VERSION 5.7 ;
  NOWIREEXTENSIONATPIN ON ;
  DIVIDERCHAR "/" ;
  BUSBITCHARS "[]" ;
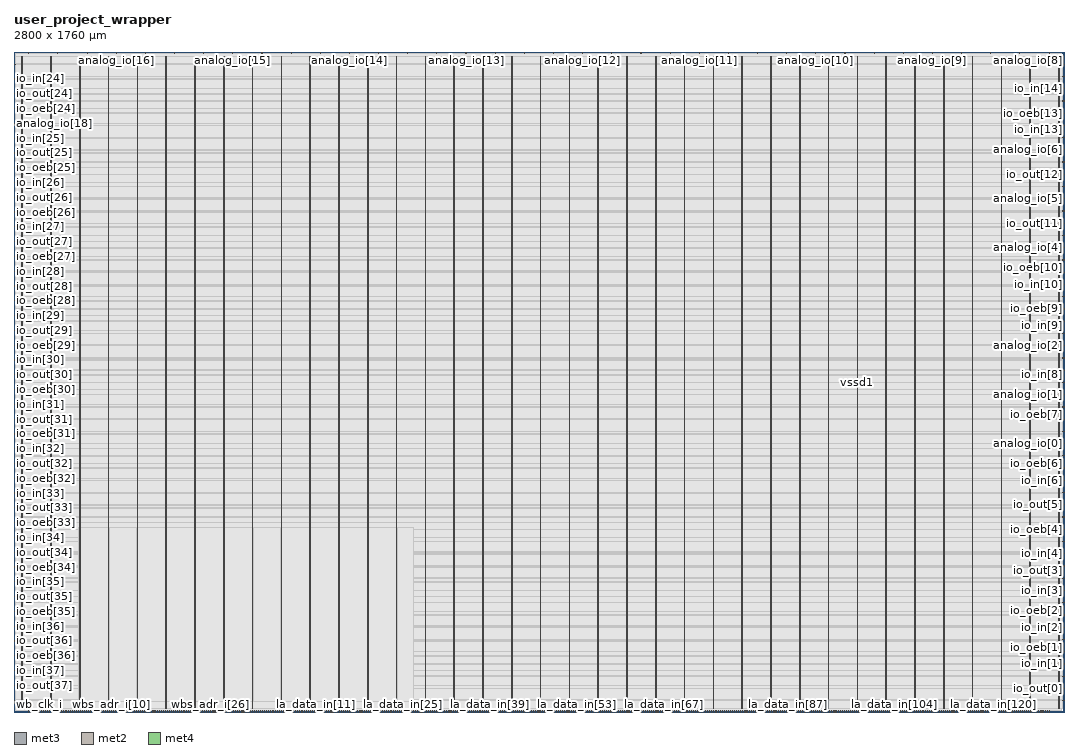
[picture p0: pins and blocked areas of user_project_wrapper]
MACRO user_project_wrapper
  CLASS BLOCK ;
  FOREIGN user_project_wrapper ;
  ORIGIN 0.000 0.000 ;
  SIZE 2800.000 BY 1760.000 ;
  PIN analog_io[0]
    DIRECTION INOUT ;
    USE SIGNAL ;
    PORT
      LAYER met3 ;
        RECT 2796.000 715.400 2800.000 716.000 ;
    END
  END analog_io[0]
  PIN analog_io[10]
    DIRECTION INOUT ;
    USE SIGNAL ;
    PORT
      LAYER met2 ;
        RECT 2138.170 1756.000 2138.450 1760.000 ;
    END
  END analog_io[10]
  PIN analog_io[11]
    DIRECTION INOUT ;
    USE SIGNAL ;
    PORT
      LAYER met2 ;
        RECT 1827.210 1756.000 1827.490 1760.000 ;
    END
  END analog_io[11]
  PIN analog_io[12]
    DIRECTION INOUT ;
    USE SIGNAL ;
    PORT
      LAYER met2 ;
        RECT 1516.250 1756.000 1516.530 1760.000 ;
    END
  END analog_io[12]
  PIN analog_io[13]
    DIRECTION INOUT ;
    USE SIGNAL ;
    PORT
      LAYER met2 ;
        RECT 1205.290 1756.000 1205.570 1760.000 ;
    END
  END analog_io[13]
  PIN analog_io[14]
    DIRECTION INOUT ;
    USE SIGNAL ;
    PORT
      LAYER met2 ;
        RECT 894.330 1756.000 894.610 1760.000 ;
    END
  END analog_io[14]
  PIN analog_io[15]
    DIRECTION INOUT ;
    USE SIGNAL ;
    PORT
      LAYER met2 ;
        RECT 583.370 1756.000 583.650 1760.000 ;
    END
  END analog_io[15]
  PIN analog_io[16]
    DIRECTION INOUT ;
    USE SIGNAL ;
    PORT
      LAYER met2 ;
        RECT 272.410 1756.000 272.690 1760.000 ;
    END
  END analog_io[16]
  PIN analog_io[17]
    DIRECTION INOUT ;
    USE SIGNAL ;
    PORT
      LAYER met3 ;
        RECT 0.000 1727.240 4.000 1727.840 ;
    END
  END analog_io[17]
  PIN analog_io[18]
    DIRECTION INOUT ;
    USE SIGNAL ;
    PORT
      LAYER met3 ;
        RECT 0.000 1569.480 4.000 1570.080 ;
    END
  END analog_io[18]
  PIN analog_io[1]
    DIRECTION INOUT ;
    USE SIGNAL ;
    PORT
      LAYER met3 ;
        RECT 2796.000 845.960 2800.000 846.560 ;
    END
  END analog_io[1]
  PIN analog_io[2]
    DIRECTION INOUT ;
    USE SIGNAL ;
    PORT
      LAYER met3 ;
        RECT 2796.000 976.520 2800.000 977.120 ;
    END
  END analog_io[2]
  PIN analog_io[3]
    DIRECTION INOUT ;
    USE SIGNAL ;
    PORT
      LAYER met3 ;
        RECT 2796.000 1107.080 2800.000 1107.680 ;
    END
  END analog_io[3]
  PIN analog_io[4]
    DIRECTION INOUT ;
    USE SIGNAL ;
    PORT
      LAYER met3 ;
        RECT 2796.000 1237.640 2800.000 1238.240 ;
    END
  END analog_io[4]
  PIN analog_io[5]
    DIRECTION INOUT ;
    USE SIGNAL ;
    PORT
      LAYER met3 ;
        RECT 2796.000 1368.200 2800.000 1368.800 ;
    END
  END analog_io[5]
  PIN analog_io[6]
    DIRECTION INOUT ;
    USE SIGNAL ;
    PORT
      LAYER met3 ;
        RECT 2796.000 1498.760 2800.000 1499.360 ;
    END
  END analog_io[6]
  PIN analog_io[7]
    DIRECTION INOUT ;
    USE SIGNAL ;
    PORT
      LAYER met3 ;
        RECT 2796.000 1629.320 2800.000 1629.920 ;
    END
  END analog_io[7]
  PIN analog_io[8]
    DIRECTION INOUT ;
    USE SIGNAL ;
    PORT
      LAYER met2 ;
        RECT 2760.090 1756.000 2760.370 1760.000 ;
    END
  END analog_io[8]
  PIN analog_io[9]
    DIRECTION INOUT ;
    USE SIGNAL ;
    PORT
      LAYER met2 ;
        RECT 2449.130 1756.000 2449.410 1760.000 ;
    END
  END analog_io[9]
  PIN io_in[0]
    DIRECTION INPUT ;
    USE SIGNAL ;
    PORT
      LAYER met3 ;
        RECT 2796.000 29.960 2800.000 30.560 ;
    END
  END io_in[0]
  PIN io_in[10]
    DIRECTION INPUT ;
    USE SIGNAL ;
    PORT
      LAYER met3 ;
        RECT 2796.000 1139.720 2800.000 1140.320 ;
    END
  END io_in[10]
  PIN io_in[11]
    DIRECTION INPUT ;
    USE SIGNAL ;
    PORT
      LAYER met3 ;
        RECT 2796.000 1270.280 2800.000 1270.880 ;
    END
  END io_in[11]
  PIN io_in[12]
    DIRECTION INPUT ;
    USE SIGNAL ;
    PORT
      LAYER met3 ;
        RECT 2796.000 1400.840 2800.000 1401.440 ;
    END
  END io_in[12]
  PIN io_in[13]
    DIRECTION INPUT ;
    USE SIGNAL ;
    PORT
      LAYER met3 ;
        RECT 2796.000 1531.400 2800.000 1532.000 ;
    END
  END io_in[13]
  PIN io_in[14]
    DIRECTION INPUT ;
    USE SIGNAL ;
    PORT
      LAYER met3 ;
        RECT 2796.000 1661.960 2800.000 1662.560 ;
    END
  END io_in[14]
  PIN io_in[15]
    DIRECTION INPUT ;
    USE SIGNAL ;
    PORT
      LAYER met2 ;
        RECT 2682.350 1756.000 2682.630 1760.000 ;
    END
  END io_in[15]
  PIN io_in[16]
    DIRECTION INPUT ;
    USE SIGNAL ;
    PORT
      LAYER met2 ;
        RECT 2371.390 1756.000 2371.670 1760.000 ;
    END
  END io_in[16]
  PIN io_in[17]
    DIRECTION INPUT ;
    USE SIGNAL ;
    PORT
      LAYER met2 ;
        RECT 2060.430 1756.000 2060.710 1760.000 ;
    END
  END io_in[17]
  PIN io_in[18]
    DIRECTION INPUT ;
    USE SIGNAL ;
    PORT
      LAYER met2 ;
        RECT 1749.470 1756.000 1749.750 1760.000 ;
    END
  END io_in[18]
  PIN io_in[19]
    DIRECTION INPUT ;
    USE SIGNAL ;
    PORT
      LAYER met2 ;
        RECT 1438.510 1756.000 1438.790 1760.000 ;
    END
  END io_in[19]
  PIN io_in[1]
    DIRECTION INPUT ;
    USE SIGNAL ;
    PORT
      LAYER met3 ;
        RECT 2796.000 127.880 2800.000 128.480 ;
    END
  END io_in[1]
  PIN io_in[20]
    DIRECTION INPUT ;
    USE SIGNAL ;
    PORT
      LAYER met2 ;
        RECT 1127.550 1756.000 1127.830 1760.000 ;
    END
  END io_in[20]
  PIN io_in[21]
    DIRECTION INPUT ;
    USE SIGNAL ;
    PORT
      LAYER met2 ;
        RECT 816.590 1756.000 816.870 1760.000 ;
    END
  END io_in[21]
  PIN io_in[22]
    DIRECTION INPUT ;
    USE SIGNAL ;
    PORT
      LAYER met2 ;
        RECT 505.630 1756.000 505.910 1760.000 ;
    END
  END io_in[22]
  PIN io_in[23]
    DIRECTION INPUT ;
    USE SIGNAL ;
    PORT
      LAYER met2 ;
        RECT 194.670 1756.000 194.950 1760.000 ;
    END
  END io_in[23]
  PIN io_in[24]
    DIRECTION INPUT ;
    USE SIGNAL ;
    PORT
      LAYER met3 ;
        RECT 0.000 1687.800 4.000 1688.400 ;
    END
  END io_in[24]
  PIN io_in[25]
    DIRECTION INPUT ;
    USE SIGNAL ;
    PORT
      LAYER met3 ;
        RECT 0.000 1530.040 4.000 1530.640 ;
    END
  END io_in[25]
  PIN io_in[26]
    DIRECTION INPUT ;
    USE SIGNAL ;
    PORT
      LAYER met3 ;
        RECT 0.000 1411.720 4.000 1412.320 ;
    END
  END io_in[26]
  PIN io_in[27]
    DIRECTION INPUT ;
    USE SIGNAL ;
    PORT
      LAYER met3 ;
        RECT 0.000 1293.400 4.000 1294.000 ;
    END
  END io_in[27]
  PIN io_in[28]
    DIRECTION INPUT ;
    USE SIGNAL ;
    PORT
      LAYER met3 ;
        RECT 0.000 1175.080 4.000 1175.680 ;
    END
  END io_in[28]
  PIN io_in[29]
    DIRECTION INPUT ;
    USE SIGNAL ;
    PORT
      LAYER met3 ;
        RECT 0.000 1056.760 4.000 1057.360 ;
    END
  END io_in[29]
  PIN io_in[2]
    DIRECTION INPUT ;
    USE SIGNAL ;
    PORT
      LAYER met3 ;
        RECT 2796.000 225.800 2800.000 226.400 ;
    END
  END io_in[2]
  PIN io_in[30]
    DIRECTION INPUT ;
    USE SIGNAL ;
    PORT
      LAYER met3 ;
        RECT 0.000 938.440 4.000 939.040 ;
    END
  END io_in[30]
  PIN io_in[31]
    DIRECTION INPUT ;
    USE SIGNAL ;
    PORT
      LAYER met3 ;
        RECT 0.000 820.120 4.000 820.720 ;
    END
  END io_in[31]
  PIN io_in[32]
    DIRECTION INPUT ;
    USE SIGNAL ;
    PORT
      LAYER met3 ;
        RECT 0.000 701.800 4.000 702.400 ;
    END
  END io_in[32]
  PIN io_in[33]
    DIRECTION INPUT ;
    USE SIGNAL ;
    PORT
      LAYER met3 ;
        RECT 0.000 583.480 4.000 584.080 ;
    END
  END io_in[33]
  PIN io_in[34]
    DIRECTION INPUT ;
    USE SIGNAL ;
    PORT
      LAYER met3 ;
        RECT 0.000 465.160 4.000 465.760 ;
    END
  END io_in[34]
  PIN io_in[35]
    DIRECTION INPUT ;
    USE SIGNAL ;
    PORT
      LAYER met3 ;
        RECT 0.000 346.840 4.000 347.440 ;
    END
  END io_in[35]
  PIN io_in[36]
    DIRECTION INPUT ;
    USE SIGNAL ;
    PORT
      LAYER met3 ;
        RECT 0.000 228.520 4.000 229.120 ;
    END
  END io_in[36]
  PIN io_in[37]
    DIRECTION INPUT ;
    USE SIGNAL ;
    PORT
      LAYER met3 ;
        RECT 0.000 110.200 4.000 110.800 ;
    END
  END io_in[37]
  PIN io_in[3]
    DIRECTION INPUT ;
    USE SIGNAL ;
    PORT
      LAYER met3 ;
        RECT 2796.000 323.720 2800.000 324.320 ;
    END
  END io_in[3]
  PIN io_in[4]
    DIRECTION INPUT ;
    USE SIGNAL ;
    PORT
      LAYER met3 ;
        RECT 2796.000 421.640 2800.000 422.240 ;
    END
  END io_in[4]
  PIN io_in[5]
    DIRECTION INPUT ;
    USE SIGNAL ;
    PORT
      LAYER met3 ;
        RECT 2796.000 519.560 2800.000 520.160 ;
    END
  END io_in[5]
  PIN io_in[6]
    DIRECTION INPUT ;
    USE SIGNAL ;
    PORT
      LAYER met3 ;
        RECT 2796.000 617.480 2800.000 618.080 ;
    END
  END io_in[6]
  PIN io_in[7]
    DIRECTION INPUT ;
    USE SIGNAL ;
    PORT
      LAYER met3 ;
        RECT 2796.000 748.040 2800.000 748.640 ;
    END
  END io_in[7]
  PIN io_in[8]
    DIRECTION INPUT ;
    USE SIGNAL ;
    ANTENNAGATEAREA 0.990000 ;
    PORT
      LAYER met3 ;
        RECT 2796.000 878.600 2800.000 879.200 ;
    END
  END io_in[8]
  PIN io_in[9]
    DIRECTION INPUT ;
    USE SIGNAL ;
    PORT
      LAYER met3 ;
        RECT 2796.000 1009.160 2800.000 1009.760 ;
    END
  END io_in[9]
  PIN io_oeb[0]
    DIRECTION OUTPUT TRISTATE ;
    USE SIGNAL ;
    PORT
      LAYER met3 ;
        RECT 2796.000 95.240 2800.000 95.840 ;
    END
  END io_oeb[0]
  PIN io_oeb[10]
    DIRECTION OUTPUT TRISTATE ;
    USE SIGNAL ;
    PORT
      LAYER met3 ;
        RECT 2796.000 1205.000 2800.000 1205.600 ;
    END
  END io_oeb[10]
  PIN io_oeb[11]
    DIRECTION OUTPUT TRISTATE ;
    USE SIGNAL ;
    PORT
      LAYER met3 ;
        RECT 2796.000 1335.560 2800.000 1336.160 ;
    END
  END io_oeb[11]
  PIN io_oeb[12]
    DIRECTION OUTPUT TRISTATE ;
    USE SIGNAL ;
    PORT
      LAYER met3 ;
        RECT 2796.000 1466.120 2800.000 1466.720 ;
    END
  END io_oeb[12]
  PIN io_oeb[13]
    DIRECTION OUTPUT TRISTATE ;
    USE SIGNAL ;
    PORT
      LAYER met3 ;
        RECT 2796.000 1596.680 2800.000 1597.280 ;
    END
  END io_oeb[13]
  PIN io_oeb[14]
    DIRECTION OUTPUT TRISTATE ;
    USE SIGNAL ;
    PORT
      LAYER met3 ;
        RECT 2796.000 1727.240 2800.000 1727.840 ;
    END
  END io_oeb[14]
  PIN io_oeb[15]
    DIRECTION OUTPUT TRISTATE ;
    USE SIGNAL ;
    PORT
      LAYER met2 ;
        RECT 2526.870 1756.000 2527.150 1760.000 ;
    END
  END io_oeb[15]
  PIN io_oeb[16]
    DIRECTION OUTPUT TRISTATE ;
    USE SIGNAL ;
    PORT
      LAYER met2 ;
        RECT 2215.910 1756.000 2216.190 1760.000 ;
    END
  END io_oeb[16]
  PIN io_oeb[17]
    DIRECTION OUTPUT TRISTATE ;
    USE SIGNAL ;
    PORT
      LAYER met2 ;
        RECT 1904.950 1756.000 1905.230 1760.000 ;
    END
  END io_oeb[17]
  PIN io_oeb[18]
    DIRECTION OUTPUT TRISTATE ;
    USE SIGNAL ;
    PORT
      LAYER met2 ;
        RECT 1593.990 1756.000 1594.270 1760.000 ;
    END
  END io_oeb[18]
  PIN io_oeb[19]
    DIRECTION OUTPUT TRISTATE ;
    USE SIGNAL ;
    PORT
      LAYER met2 ;
        RECT 1283.030 1756.000 1283.310 1760.000 ;
    END
  END io_oeb[19]
  PIN io_oeb[1]
    DIRECTION OUTPUT TRISTATE ;
    USE SIGNAL ;
    PORT
      LAYER met3 ;
        RECT 2796.000 193.160 2800.000 193.760 ;
    END
  END io_oeb[1]
  PIN io_oeb[20]
    DIRECTION OUTPUT TRISTATE ;
    USE SIGNAL ;
    PORT
      LAYER met2 ;
        RECT 972.070 1756.000 972.350 1760.000 ;
    END
  END io_oeb[20]
  PIN io_oeb[21]
    DIRECTION OUTPUT TRISTATE ;
    USE SIGNAL ;
    PORT
      LAYER met2 ;
        RECT 661.110 1756.000 661.390 1760.000 ;
    END
  END io_oeb[21]
  PIN io_oeb[22]
    DIRECTION OUTPUT TRISTATE ;
    USE SIGNAL ;
    PORT
      LAYER met2 ;
        RECT 350.150 1756.000 350.430 1760.000 ;
    END
  END io_oeb[22]
  PIN io_oeb[23]
    DIRECTION OUTPUT TRISTATE ;
    USE SIGNAL ;
    PORT
      LAYER met2 ;
        RECT 39.190 1756.000 39.470 1760.000 ;
    END
  END io_oeb[23]
  PIN io_oeb[24]
    DIRECTION OUTPUT TRISTATE ;
    USE SIGNAL ;
    PORT
      LAYER met3 ;
        RECT 0.000 1608.920 4.000 1609.520 ;
    END
  END io_oeb[24]
  PIN io_oeb[25]
    DIRECTION OUTPUT TRISTATE ;
    USE SIGNAL ;
    PORT
      LAYER met3 ;
        RECT 0.000 1451.160 4.000 1451.760 ;
    END
  END io_oeb[25]
  PIN io_oeb[26]
    DIRECTION OUTPUT TRISTATE ;
    USE SIGNAL ;
    PORT
      LAYER met3 ;
        RECT 0.000 1332.840 4.000 1333.440 ;
    END
  END io_oeb[26]
  PIN io_oeb[27]
    DIRECTION OUTPUT TRISTATE ;
    USE SIGNAL ;
    PORT
      LAYER met3 ;
        RECT 0.000 1214.520 4.000 1215.120 ;
    END
  END io_oeb[27]
  PIN io_oeb[28]
    DIRECTION OUTPUT TRISTATE ;
    USE SIGNAL ;
    PORT
      LAYER met3 ;
        RECT 0.000 1096.200 4.000 1096.800 ;
    END
  END io_oeb[28]
  PIN io_oeb[29]
    DIRECTION OUTPUT TRISTATE ;
    USE SIGNAL ;
    PORT
      LAYER met3 ;
        RECT 0.000 977.880 4.000 978.480 ;
    END
  END io_oeb[29]
  PIN io_oeb[2]
    DIRECTION OUTPUT TRISTATE ;
    USE SIGNAL ;
    PORT
      LAYER met3 ;
        RECT 2796.000 291.080 2800.000 291.680 ;
    END
  END io_oeb[2]
  PIN io_oeb[30]
    DIRECTION OUTPUT TRISTATE ;
    USE SIGNAL ;
    PORT
      LAYER met3 ;
        RECT 0.000 859.560 4.000 860.160 ;
    END
  END io_oeb[30]
  PIN io_oeb[31]
    DIRECTION OUTPUT TRISTATE ;
    USE SIGNAL ;
    PORT
      LAYER met3 ;
        RECT 0.000 741.240 4.000 741.840 ;
    END
  END io_oeb[31]
  PIN io_oeb[32]
    DIRECTION OUTPUT TRISTATE ;
    USE SIGNAL ;
    PORT
      LAYER met3 ;
        RECT 0.000 622.920 4.000 623.520 ;
    END
  END io_oeb[32]
  PIN io_oeb[33]
    DIRECTION OUTPUT TRISTATE ;
    USE SIGNAL ;
    PORT
      LAYER met3 ;
        RECT 0.000 504.600 4.000 505.200 ;
    END
  END io_oeb[33]
  PIN io_oeb[34]
    DIRECTION OUTPUT TRISTATE ;
    USE SIGNAL ;
    PORT
      LAYER met3 ;
        RECT 0.000 386.280 4.000 386.880 ;
    END
  END io_oeb[34]
  PIN io_oeb[35]
    DIRECTION OUTPUT TRISTATE ;
    USE SIGNAL ;
    PORT
      LAYER met3 ;
        RECT 0.000 267.960 4.000 268.560 ;
    END
  END io_oeb[35]
  PIN io_oeb[36]
    DIRECTION OUTPUT TRISTATE ;
    USE SIGNAL ;
    PORT
      LAYER met3 ;
        RECT 0.000 149.640 4.000 150.240 ;
    END
  END io_oeb[36]
  PIN io_oeb[37]
    DIRECTION OUTPUT TRISTATE ;
    USE SIGNAL ;
    PORT
      LAYER met3 ;
        RECT 0.000 31.320 4.000 31.920 ;
    END
  END io_oeb[37]
  PIN io_oeb[3]
    DIRECTION OUTPUT TRISTATE ;
    USE SIGNAL ;
    PORT
      LAYER met3 ;
        RECT 2796.000 389.000 2800.000 389.600 ;
    END
  END io_oeb[3]
  PIN io_oeb[4]
    DIRECTION OUTPUT TRISTATE ;
    USE SIGNAL ;
    PORT
      LAYER met3 ;
        RECT 2796.000 486.920 2800.000 487.520 ;
    END
  END io_oeb[4]
  PIN io_oeb[5]
    DIRECTION OUTPUT TRISTATE ;
    USE SIGNAL ;
    PORT
      LAYER met3 ;
        RECT 2796.000 584.840 2800.000 585.440 ;
    END
  END io_oeb[5]
  PIN io_oeb[6]
    DIRECTION OUTPUT TRISTATE ;
    USE SIGNAL ;
    PORT
      LAYER met3 ;
        RECT 2796.000 682.760 2800.000 683.360 ;
    END
  END io_oeb[6]
  PIN io_oeb[7]
    DIRECTION OUTPUT TRISTATE ;
    USE SIGNAL ;
    PORT
      LAYER met3 ;
        RECT 2796.000 813.320 2800.000 813.920 ;
    END
  END io_oeb[7]
  PIN io_oeb[8]
    DIRECTION OUTPUT TRISTATE ;
    USE SIGNAL ;
    PORT
      LAYER met3 ;
        RECT 2796.000 943.880 2800.000 944.480 ;
    END
  END io_oeb[8]
  PIN io_oeb[9]
    DIRECTION OUTPUT TRISTATE ;
    USE SIGNAL ;
    PORT
      LAYER met3 ;
        RECT 2796.000 1074.440 2800.000 1075.040 ;
    END
  END io_oeb[9]
  PIN io_out[0]
    DIRECTION OUTPUT TRISTATE ;
    USE SIGNAL ;
    PORT
      LAYER met3 ;
        RECT 2796.000 62.600 2800.000 63.200 ;
    END
  END io_out[0]
  PIN io_out[10]
    DIRECTION OUTPUT TRISTATE ;
    USE SIGNAL ;
    PORT
      LAYER met3 ;
        RECT 2796.000 1172.360 2800.000 1172.960 ;
    END
  END io_out[10]
  PIN io_out[11]
    DIRECTION OUTPUT TRISTATE ;
    USE SIGNAL ;
    PORT
      LAYER met3 ;
        RECT 2796.000 1302.920 2800.000 1303.520 ;
    END
  END io_out[11]
  PIN io_out[12]
    DIRECTION OUTPUT TRISTATE ;
    USE SIGNAL ;
    PORT
      LAYER met3 ;
        RECT 2796.000 1433.480 2800.000 1434.080 ;
    END
  END io_out[12]
  PIN io_out[13]
    DIRECTION OUTPUT TRISTATE ;
    USE SIGNAL ;
    PORT
      LAYER met3 ;
        RECT 2796.000 1564.040 2800.000 1564.640 ;
    END
  END io_out[13]
  PIN io_out[14]
    DIRECTION OUTPUT TRISTATE ;
    USE SIGNAL ;
    PORT
      LAYER met3 ;
        RECT 2796.000 1694.600 2800.000 1695.200 ;
    END
  END io_out[14]
  PIN io_out[15]
    DIRECTION OUTPUT TRISTATE ;
    USE SIGNAL ;
    PORT
      LAYER met2 ;
        RECT 2604.610 1756.000 2604.890 1760.000 ;
    END
  END io_out[15]
  PIN io_out[16]
    DIRECTION OUTPUT TRISTATE ;
    USE SIGNAL ;
    PORT
      LAYER met2 ;
        RECT 2293.650 1756.000 2293.930 1760.000 ;
    END
  END io_out[16]
  PIN io_out[17]
    DIRECTION OUTPUT TRISTATE ;
    USE SIGNAL ;
    PORT
      LAYER met2 ;
        RECT 1982.690 1756.000 1982.970 1760.000 ;
    END
  END io_out[17]
  PIN io_out[18]
    DIRECTION OUTPUT TRISTATE ;
    USE SIGNAL ;
    PORT
      LAYER met2 ;
        RECT 1671.730 1756.000 1672.010 1760.000 ;
    END
  END io_out[18]
  PIN io_out[19]
    DIRECTION OUTPUT TRISTATE ;
    USE SIGNAL ;
    PORT
      LAYER met2 ;
        RECT 1360.770 1756.000 1361.050 1760.000 ;
    END
  END io_out[19]
  PIN io_out[1]
    DIRECTION OUTPUT TRISTATE ;
    USE SIGNAL ;
    PORT
      LAYER met3 ;
        RECT 2796.000 160.520 2800.000 161.120 ;
    END
  END io_out[1]
  PIN io_out[20]
    DIRECTION OUTPUT TRISTATE ;
    USE SIGNAL ;
    PORT
      LAYER met2 ;
        RECT 1049.810 1756.000 1050.090 1760.000 ;
    END
  END io_out[20]
  PIN io_out[21]
    DIRECTION OUTPUT TRISTATE ;
    USE SIGNAL ;
    PORT
      LAYER met2 ;
        RECT 738.850 1756.000 739.130 1760.000 ;
    END
  END io_out[21]
  PIN io_out[22]
    DIRECTION OUTPUT TRISTATE ;
    USE SIGNAL ;
    PORT
      LAYER met2 ;
        RECT 427.890 1756.000 428.170 1760.000 ;
    END
  END io_out[22]
  PIN io_out[23]
    DIRECTION OUTPUT TRISTATE ;
    USE SIGNAL ;
    PORT
      LAYER met2 ;
        RECT 116.930 1756.000 117.210 1760.000 ;
    END
  END io_out[23]
  PIN io_out[24]
    DIRECTION OUTPUT TRISTATE ;
    USE SIGNAL ;
    PORT
      LAYER met3 ;
        RECT 0.000 1648.360 4.000 1648.960 ;
    END
  END io_out[24]
  PIN io_out[25]
    DIRECTION OUTPUT TRISTATE ;
    USE SIGNAL ;
    PORT
      LAYER met3 ;
        RECT 0.000 1490.600 4.000 1491.200 ;
    END
  END io_out[25]
  PIN io_out[26]
    DIRECTION OUTPUT TRISTATE ;
    USE SIGNAL ;
    PORT
      LAYER met3 ;
        RECT 0.000 1372.280 4.000 1372.880 ;
    END
  END io_out[26]
  PIN io_out[27]
    DIRECTION OUTPUT TRISTATE ;
    USE SIGNAL ;
    PORT
      LAYER met3 ;
        RECT 0.000 1253.960 4.000 1254.560 ;
    END
  END io_out[27]
  PIN io_out[28]
    DIRECTION OUTPUT TRISTATE ;
    USE SIGNAL ;
    PORT
      LAYER met3 ;
        RECT 0.000 1135.640 4.000 1136.240 ;
    END
  END io_out[28]
  PIN io_out[29]
    DIRECTION OUTPUT TRISTATE ;
    USE SIGNAL ;
    PORT
      LAYER met3 ;
        RECT 0.000 1017.320 4.000 1017.920 ;
    END
  END io_out[29]
  PIN io_out[2]
    DIRECTION OUTPUT TRISTATE ;
    USE SIGNAL ;
    PORT
      LAYER met3 ;
        RECT 2796.000 258.440 2800.000 259.040 ;
    END
  END io_out[2]
  PIN io_out[30]
    DIRECTION OUTPUT TRISTATE ;
    USE SIGNAL ;
    PORT
      LAYER met3 ;
        RECT 0.000 899.000 4.000 899.600 ;
    END
  END io_out[30]
  PIN io_out[31]
    DIRECTION OUTPUT TRISTATE ;
    USE SIGNAL ;
    PORT
      LAYER met3 ;
        RECT 0.000 780.680 4.000 781.280 ;
    END
  END io_out[31]
  PIN io_out[32]
    DIRECTION OUTPUT TRISTATE ;
    USE SIGNAL ;
    PORT
      LAYER met3 ;
        RECT 0.000 662.360 4.000 662.960 ;
    END
  END io_out[32]
  PIN io_out[33]
    DIRECTION OUTPUT TRISTATE ;
    USE SIGNAL ;
    PORT
      LAYER met3 ;
        RECT 0.000 544.040 4.000 544.640 ;
    END
  END io_out[33]
  PIN io_out[34]
    DIRECTION OUTPUT TRISTATE ;
    USE SIGNAL ;
    PORT
      LAYER met3 ;
        RECT 0.000 425.720 4.000 426.320 ;
    END
  END io_out[34]
  PIN io_out[35]
    DIRECTION OUTPUT TRISTATE ;
    USE SIGNAL ;
    PORT
      LAYER met3 ;
        RECT 0.000 307.400 4.000 308.000 ;
    END
  END io_out[35]
  PIN io_out[36]
    DIRECTION OUTPUT TRISTATE ;
    USE SIGNAL ;
    PORT
      LAYER met3 ;
        RECT 0.000 189.080 4.000 189.680 ;
    END
  END io_out[36]
  PIN io_out[37]
    DIRECTION OUTPUT TRISTATE ;
    USE SIGNAL ;
    PORT
      LAYER met3 ;
        RECT 0.000 70.760 4.000 71.360 ;
    END
  END io_out[37]
  PIN io_out[3]
    DIRECTION OUTPUT TRISTATE ;
    USE SIGNAL ;
    PORT
      LAYER met3 ;
        RECT 2796.000 356.360 2800.000 356.960 ;
    END
  END io_out[3]
  PIN io_out[4]
    DIRECTION OUTPUT TRISTATE ;
    USE SIGNAL ;
    PORT
      LAYER met3 ;
        RECT 2796.000 454.280 2800.000 454.880 ;
    END
  END io_out[4]
  PIN io_out[5]
    DIRECTION OUTPUT TRISTATE ;
    USE SIGNAL ;
    PORT
      LAYER met3 ;
        RECT 2796.000 552.200 2800.000 552.800 ;
    END
  END io_out[5]
  PIN io_out[6]
    DIRECTION OUTPUT TRISTATE ;
    USE SIGNAL ;
    PORT
      LAYER met3 ;
        RECT 2796.000 650.120 2800.000 650.720 ;
    END
  END io_out[6]
  PIN io_out[7]
    DIRECTION OUTPUT TRISTATE ;
    USE SIGNAL ;
    PORT
      LAYER met3 ;
        RECT 2796.000 780.680 2800.000 781.280 ;
    END
  END io_out[7]
  PIN io_out[8]
    DIRECTION OUTPUT TRISTATE ;
    USE SIGNAL ;
    PORT
      LAYER met3 ;
        RECT 2796.000 911.240 2800.000 911.840 ;
    END
  END io_out[8]
  PIN io_out[9]
    DIRECTION OUTPUT TRISTATE ;
    USE SIGNAL ;
    ANTENNADIFFAREA 2.673000 ;
    PORT
      LAYER met3 ;
        RECT 2796.000 1041.800 2800.000 1042.400 ;
    END
  END io_out[9]
  PIN la_data_in[0]
    DIRECTION INPUT ;
    USE SIGNAL ;
    PORT
      LAYER met2 ;
        RECT 624.310 0.000 624.590 4.000 ;
    END
  END la_data_in[0]
  PIN la_data_in[100]
    DIRECTION INPUT ;
    USE SIGNAL ;
    PORT
      LAYER met2 ;
        RECT 2280.310 0.000 2280.590 4.000 ;
    END
  END la_data_in[100]
  PIN la_data_in[101]
    DIRECTION INPUT ;
    USE SIGNAL ;
    PORT
      LAYER met2 ;
        RECT 2296.870 0.000 2297.150 4.000 ;
    END
  END la_data_in[101]
  PIN la_data_in[102]
    DIRECTION INPUT ;
    USE SIGNAL ;
    PORT
      LAYER met2 ;
        RECT 2313.430 0.000 2313.710 4.000 ;
    END
  END la_data_in[102]
  PIN la_data_in[103]
    DIRECTION INPUT ;
    USE SIGNAL ;
    PORT
      LAYER met2 ;
        RECT 2329.990 0.000 2330.270 4.000 ;
    END
  END la_data_in[103]
  PIN la_data_in[104]
    DIRECTION INPUT ;
    USE SIGNAL ;
    PORT
      LAYER met2 ;
        RECT 2346.550 0.000 2346.830 4.000 ;
    END
  END la_data_in[104]
  PIN la_data_in[105]
    DIRECTION INPUT ;
    USE SIGNAL ;
    PORT
      LAYER met2 ;
        RECT 2363.110 0.000 2363.390 4.000 ;
    END
  END la_data_in[105]
  PIN la_data_in[106]
    DIRECTION INPUT ;
    USE SIGNAL ;
    PORT
      LAYER met2 ;
        RECT 2379.670 0.000 2379.950 4.000 ;
    END
  END la_data_in[106]
  PIN la_data_in[107]
    DIRECTION INPUT ;
    USE SIGNAL ;
    PORT
      LAYER met2 ;
        RECT 2396.230 0.000 2396.510 4.000 ;
    END
  END la_data_in[107]
  PIN la_data_in[108]
    DIRECTION INPUT ;
    USE SIGNAL ;
    PORT
      LAYER met2 ;
        RECT 2412.790 0.000 2413.070 4.000 ;
    END
  END la_data_in[108]
  PIN la_data_in[109]
    DIRECTION INPUT ;
    USE SIGNAL ;
    PORT
      LAYER met2 ;
        RECT 2429.350 0.000 2429.630 4.000 ;
    END
  END la_data_in[109]
  PIN la_data_in[10]
    DIRECTION INPUT ;
    USE SIGNAL ;
    PORT
      LAYER met2 ;
        RECT 789.910 0.000 790.190 4.000 ;
    END
  END la_data_in[10]
  PIN la_data_in[110]
    DIRECTION INPUT ;
    USE SIGNAL ;
    PORT
      LAYER met2 ;
        RECT 2445.910 0.000 2446.190 4.000 ;
    END
  END la_data_in[110]
  PIN la_data_in[111]
    DIRECTION INPUT ;
    USE SIGNAL ;
    PORT
      LAYER met2 ;
        RECT 2462.470 0.000 2462.750 4.000 ;
    END
  END la_data_in[111]
  PIN la_data_in[112]
    DIRECTION INPUT ;
    USE SIGNAL ;
    PORT
      LAYER met2 ;
        RECT 2479.030 0.000 2479.310 4.000 ;
    END
  END la_data_in[112]
  PIN la_data_in[113]
    DIRECTION INPUT ;
    USE SIGNAL ;
    PORT
      LAYER met2 ;
        RECT 2495.590 0.000 2495.870 4.000 ;
    END
  END la_data_in[113]
  PIN la_data_in[114]
    DIRECTION INPUT ;
    USE SIGNAL ;
    PORT
      LAYER met2 ;
        RECT 2512.150 0.000 2512.430 4.000 ;
    END
  END la_data_in[114]
  PIN la_data_in[115]
    DIRECTION INPUT ;
    USE SIGNAL ;
    PORT
      LAYER met2 ;
        RECT 2528.710 0.000 2528.990 4.000 ;
    END
  END la_data_in[115]
  PIN la_data_in[116]
    DIRECTION INPUT ;
    USE SIGNAL ;
    PORT
      LAYER met2 ;
        RECT 2545.270 0.000 2545.550 4.000 ;
    END
  END la_data_in[116]
  PIN la_data_in[117]
    DIRECTION INPUT ;
    USE SIGNAL ;
    PORT
      LAYER met2 ;
        RECT 2561.830 0.000 2562.110 4.000 ;
    END
  END la_data_in[117]
  PIN la_data_in[118]
    DIRECTION INPUT ;
    USE SIGNAL ;
    PORT
      LAYER met2 ;
        RECT 2578.390 0.000 2578.670 4.000 ;
    END
  END la_data_in[118]
  PIN la_data_in[119]
    DIRECTION INPUT ;
    USE SIGNAL ;
    PORT
      LAYER met2 ;
        RECT 2594.950 0.000 2595.230 4.000 ;
    END
  END la_data_in[119]
  PIN la_data_in[11]
    DIRECTION INPUT ;
    USE SIGNAL ;
    PORT
      LAYER met2 ;
        RECT 806.470 0.000 806.750 4.000 ;
    END
  END la_data_in[11]
  PIN la_data_in[120]
    DIRECTION INPUT ;
    USE SIGNAL ;
    PORT
      LAYER met2 ;
        RECT 2611.510 0.000 2611.790 4.000 ;
    END
  END la_data_in[120]
  PIN la_data_in[121]
    DIRECTION INPUT ;
    USE SIGNAL ;
    PORT
      LAYER met2 ;
        RECT 2628.070 0.000 2628.350 4.000 ;
    END
  END la_data_in[121]
  PIN la_data_in[122]
    DIRECTION INPUT ;
    USE SIGNAL ;
    PORT
      LAYER met2 ;
        RECT 2644.630 0.000 2644.910 4.000 ;
    END
  END la_data_in[122]
  PIN la_data_in[123]
    DIRECTION INPUT ;
    USE SIGNAL ;
    PORT
      LAYER met2 ;
        RECT 2661.190 0.000 2661.470 4.000 ;
    END
  END la_data_in[123]
  PIN la_data_in[124]
    DIRECTION INPUT ;
    USE SIGNAL ;
    PORT
      LAYER met2 ;
        RECT 2677.750 0.000 2678.030 4.000 ;
    END
  END la_data_in[124]
  PIN la_data_in[125]
    DIRECTION INPUT ;
    USE SIGNAL ;
    PORT
      LAYER met2 ;
        RECT 2694.310 0.000 2694.590 4.000 ;
    END
  END la_data_in[125]
  PIN la_data_in[126]
    DIRECTION INPUT ;
    USE SIGNAL ;
    PORT
      LAYER met2 ;
        RECT 2710.870 0.000 2711.150 4.000 ;
    END
  END la_data_in[126]
  PIN la_data_in[127]
    DIRECTION INPUT ;
    USE SIGNAL ;
    PORT
      LAYER met2 ;
        RECT 2727.430 0.000 2727.710 4.000 ;
    END
  END la_data_in[127]
  PIN la_data_in[12]
    DIRECTION INPUT ;
    USE SIGNAL ;
    PORT
      LAYER met2 ;
        RECT 823.030 0.000 823.310 4.000 ;
    END
  END la_data_in[12]
  PIN la_data_in[13]
    DIRECTION INPUT ;
    USE SIGNAL ;
    PORT
      LAYER met2 ;
        RECT 839.590 0.000 839.870 4.000 ;
    END
  END la_data_in[13]
  PIN la_data_in[14]
    DIRECTION INPUT ;
    USE SIGNAL ;
    PORT
      LAYER met2 ;
        RECT 856.150 0.000 856.430 4.000 ;
    END
  END la_data_in[14]
  PIN la_data_in[15]
    DIRECTION INPUT ;
    USE SIGNAL ;
    PORT
      LAYER met2 ;
        RECT 872.710 0.000 872.990 4.000 ;
    END
  END la_data_in[15]
  PIN la_data_in[16]
    DIRECTION INPUT ;
    USE SIGNAL ;
    PORT
      LAYER met2 ;
        RECT 889.270 0.000 889.550 4.000 ;
    END
  END la_data_in[16]
  PIN la_data_in[17]
    DIRECTION INPUT ;
    USE SIGNAL ;
    PORT
      LAYER met2 ;
        RECT 905.830 0.000 906.110 4.000 ;
    END
  END la_data_in[17]
  PIN la_data_in[18]
    DIRECTION INPUT ;
    USE SIGNAL ;
    PORT
      LAYER met2 ;
        RECT 922.390 0.000 922.670 4.000 ;
    END
  END la_data_in[18]
  PIN la_data_in[19]
    DIRECTION INPUT ;
    USE SIGNAL ;
    PORT
      LAYER met2 ;
        RECT 938.950 0.000 939.230 4.000 ;
    END
  END la_data_in[19]
  PIN la_data_in[1]
    DIRECTION INPUT ;
    USE SIGNAL ;
    PORT
      LAYER met2 ;
        RECT 640.870 0.000 641.150 4.000 ;
    END
  END la_data_in[1]
  PIN la_data_in[20]
    DIRECTION INPUT ;
    USE SIGNAL ;
    PORT
      LAYER met2 ;
        RECT 955.510 0.000 955.790 4.000 ;
    END
  END la_data_in[20]
  PIN la_data_in[21]
    DIRECTION INPUT ;
    USE SIGNAL ;
    PORT
      LAYER met2 ;
        RECT 972.070 0.000 972.350 4.000 ;
    END
  END la_data_in[21]
  PIN la_data_in[22]
    DIRECTION INPUT ;
    USE SIGNAL ;
    PORT
      LAYER met2 ;
        RECT 988.630 0.000 988.910 4.000 ;
    END
  END la_data_in[22]
  PIN la_data_in[23]
    DIRECTION INPUT ;
    USE SIGNAL ;
    PORT
      LAYER met2 ;
        RECT 1005.190 0.000 1005.470 4.000 ;
    END
  END la_data_in[23]
  PIN la_data_in[24]
    DIRECTION INPUT ;
    USE SIGNAL ;
    PORT
      LAYER met2 ;
        RECT 1021.750 0.000 1022.030 4.000 ;
    END
  END la_data_in[24]
  PIN la_data_in[25]
    DIRECTION INPUT ;
    USE SIGNAL ;
    PORT
      LAYER met2 ;
        RECT 1038.310 0.000 1038.590 4.000 ;
    END
  END la_data_in[25]
  PIN la_data_in[26]
    DIRECTION INPUT ;
    USE SIGNAL ;
    PORT
      LAYER met2 ;
        RECT 1054.870 0.000 1055.150 4.000 ;
    END
  END la_data_in[26]
  PIN la_data_in[27]
    DIRECTION INPUT ;
    USE SIGNAL ;
    PORT
      LAYER met2 ;
        RECT 1071.430 0.000 1071.710 4.000 ;
    END
  END la_data_in[27]
  PIN la_data_in[28]
    DIRECTION INPUT ;
    USE SIGNAL ;
    PORT
      LAYER met2 ;
        RECT 1087.990 0.000 1088.270 4.000 ;
    END
  END la_data_in[28]
  PIN la_data_in[29]
    DIRECTION INPUT ;
    USE SIGNAL ;
    PORT
      LAYER met2 ;
        RECT 1104.550 0.000 1104.830 4.000 ;
    END
  END la_data_in[29]
  PIN la_data_in[2]
    DIRECTION INPUT ;
    USE SIGNAL ;
    PORT
      LAYER met2 ;
        RECT 657.430 0.000 657.710 4.000 ;
    END
  END la_data_in[2]
  PIN la_data_in[30]
    DIRECTION INPUT ;
    USE SIGNAL ;
    PORT
      LAYER met2 ;
        RECT 1121.110 0.000 1121.390 4.000 ;
    END
  END la_data_in[30]
  PIN la_data_in[31]
    DIRECTION INPUT ;
    USE SIGNAL ;
    PORT
      LAYER met2 ;
        RECT 1137.670 0.000 1137.950 4.000 ;
    END
  END la_data_in[31]
  PIN la_data_in[32]
    DIRECTION INPUT ;
    USE SIGNAL ;
    PORT
      LAYER met2 ;
        RECT 1154.230 0.000 1154.510 4.000 ;
    END
  END la_data_in[32]
  PIN la_data_in[33]
    DIRECTION INPUT ;
    USE SIGNAL ;
    PORT
      LAYER met2 ;
        RECT 1170.790 0.000 1171.070 4.000 ;
    END
  END la_data_in[33]
  PIN la_data_in[34]
    DIRECTION INPUT ;
    USE SIGNAL ;
    PORT
      LAYER met2 ;
        RECT 1187.350 0.000 1187.630 4.000 ;
    END
  END la_data_in[34]
  PIN la_data_in[35]
    DIRECTION INPUT ;
    USE SIGNAL ;
    PORT
      LAYER met2 ;
        RECT 1203.910 0.000 1204.190 4.000 ;
    END
  END la_data_in[35]
  PIN la_data_in[36]
    DIRECTION INPUT ;
    USE SIGNAL ;
    PORT
      LAYER met2 ;
        RECT 1220.470 0.000 1220.750 4.000 ;
    END
  END la_data_in[36]
  PIN la_data_in[37]
    DIRECTION INPUT ;
    USE SIGNAL ;
    PORT
      LAYER met2 ;
        RECT 1237.030 0.000 1237.310 4.000 ;
    END
  END la_data_in[37]
  PIN la_data_in[38]
    DIRECTION INPUT ;
    USE SIGNAL ;
    PORT
      LAYER met2 ;
        RECT 1253.590 0.000 1253.870 4.000 ;
    END
  END la_data_in[38]
  PIN la_data_in[39]
    DIRECTION INPUT ;
    USE SIGNAL ;
    PORT
      LAYER met2 ;
        RECT 1270.150 0.000 1270.430 4.000 ;
    END
  END la_data_in[39]
  PIN la_data_in[3]
    DIRECTION INPUT ;
    USE SIGNAL ;
    PORT
      LAYER met2 ;
        RECT 673.990 0.000 674.270 4.000 ;
    END
  END la_data_in[3]
  PIN la_data_in[40]
    DIRECTION INPUT ;
    USE SIGNAL ;
    PORT
      LAYER met2 ;
        RECT 1286.710 0.000 1286.990 4.000 ;
    END
  END la_data_in[40]
  PIN la_data_in[41]
    DIRECTION INPUT ;
    USE SIGNAL ;
    PORT
      LAYER met2 ;
        RECT 1303.270 0.000 1303.550 4.000 ;
    END
  END la_data_in[41]
  PIN la_data_in[42]
    DIRECTION INPUT ;
    USE SIGNAL ;
    PORT
      LAYER met2 ;
        RECT 1319.830 0.000 1320.110 4.000 ;
    END
  END la_data_in[42]
  PIN la_data_in[43]
    DIRECTION INPUT ;
    USE SIGNAL ;
    PORT
      LAYER met2 ;
        RECT 1336.390 0.000 1336.670 4.000 ;
    END
  END la_data_in[43]
  PIN la_data_in[44]
    DIRECTION INPUT ;
    USE SIGNAL ;
    PORT
      LAYER met2 ;
        RECT 1352.950 0.000 1353.230 4.000 ;
    END
  END la_data_in[44]
  PIN la_data_in[45]
    DIRECTION INPUT ;
    USE SIGNAL ;
    PORT
      LAYER met2 ;
        RECT 1369.510 0.000 1369.790 4.000 ;
    END
  END la_data_in[45]
  PIN la_data_in[46]
    DIRECTION INPUT ;
    USE SIGNAL ;
    PORT
      LAYER met2 ;
        RECT 1386.070 0.000 1386.350 4.000 ;
    END
  END la_data_in[46]
  PIN la_data_in[47]
    DIRECTION INPUT ;
    USE SIGNAL ;
    PORT
      LAYER met2 ;
        RECT 1402.630 0.000 1402.910 4.000 ;
    END
  END la_data_in[47]
  PIN la_data_in[48]
    DIRECTION INPUT ;
    USE SIGNAL ;
    PORT
      LAYER met2 ;
        RECT 1419.190 0.000 1419.470 4.000 ;
    END
  END la_data_in[48]
  PIN la_data_in[49]
    DIRECTION INPUT ;
    USE SIGNAL ;
    PORT
      LAYER met2 ;
        RECT 1435.750 0.000 1436.030 4.000 ;
    END
  END la_data_in[49]
  PIN la_data_in[4]
    DIRECTION INPUT ;
    USE SIGNAL ;
    PORT
      LAYER met2 ;
        RECT 690.550 0.000 690.830 4.000 ;
    END
  END la_data_in[4]
  PIN la_data_in[50]
    DIRECTION INPUT ;
    USE SIGNAL ;
    PORT
      LAYER met2 ;
        RECT 1452.310 0.000 1452.590 4.000 ;
    END
  END la_data_in[50]
  PIN la_data_in[51]
    DIRECTION INPUT ;
    USE SIGNAL ;
    PORT
      LAYER met2 ;
        RECT 1468.870 0.000 1469.150 4.000 ;
    END
  END la_data_in[51]
  PIN la_data_in[52]
    DIRECTION INPUT ;
    USE SIGNAL ;
    PORT
      LAYER met2 ;
        RECT 1485.430 0.000 1485.710 4.000 ;
    END
  END la_data_in[52]
  PIN la_data_in[53]
    DIRECTION INPUT ;
    USE SIGNAL ;
    PORT
      LAYER met2 ;
        RECT 1501.990 0.000 1502.270 4.000 ;
    END
  END la_data_in[53]
  PIN la_data_in[54]
    DIRECTION INPUT ;
    USE SIGNAL ;
    PORT
      LAYER met2 ;
        RECT 1518.550 0.000 1518.830 4.000 ;
    END
  END la_data_in[54]
  PIN la_data_in[55]
    DIRECTION INPUT ;
    USE SIGNAL ;
    PORT
      LAYER met2 ;
        RECT 1535.110 0.000 1535.390 4.000 ;
    END
  END la_data_in[55]
  PIN la_data_in[56]
    DIRECTION INPUT ;
    USE SIGNAL ;
    PORT
      LAYER met2 ;
        RECT 1551.670 0.000 1551.950 4.000 ;
    END
  END la_data_in[56]
  PIN la_data_in[57]
    DIRECTION INPUT ;
    USE SIGNAL ;
    PORT
      LAYER met2 ;
        RECT 1568.230 0.000 1568.510 4.000 ;
    END
  END la_data_in[57]
  PIN la_data_in[58]
    DIRECTION INPUT ;
    USE SIGNAL ;
    PORT
      LAYER met2 ;
        RECT 1584.790 0.000 1585.070 4.000 ;
    END
  END la_data_in[58]
  PIN la_data_in[59]
    DIRECTION INPUT ;
    USE SIGNAL ;
    PORT
      LAYER met2 ;
        RECT 1601.350 0.000 1601.630 4.000 ;
    END
  END la_data_in[59]
  PIN la_data_in[5]
    DIRECTION INPUT ;
    USE SIGNAL ;
    PORT
      LAYER met2 ;
        RECT 707.110 0.000 707.390 4.000 ;
    END
  END la_data_in[5]
  PIN la_data_in[60]
    DIRECTION INPUT ;
    USE SIGNAL ;
    PORT
      LAYER met2 ;
        RECT 1617.910 0.000 1618.190 4.000 ;
    END
  END la_data_in[60]
  PIN la_data_in[61]
    DIRECTION INPUT ;
    USE SIGNAL ;
    PORT
      LAYER met2 ;
        RECT 1634.470 0.000 1634.750 4.000 ;
    END
  END la_data_in[61]
  PIN la_data_in[62]
    DIRECTION INPUT ;
    USE SIGNAL ;
    PORT
      LAYER met2 ;
        RECT 1651.030 0.000 1651.310 4.000 ;
    END
  END la_data_in[62]
  PIN la_data_in[63]
    DIRECTION INPUT ;
    USE SIGNAL ;
    PORT
      LAYER met2 ;
        RECT 1667.590 0.000 1667.870 4.000 ;
    END
  END la_data_in[63]
  PIN la_data_in[64]
    DIRECTION INPUT ;
    USE SIGNAL ;
    PORT
      LAYER met2 ;
        RECT 1684.150 0.000 1684.430 4.000 ;
    END
  END la_data_in[64]
  PIN la_data_in[65]
    DIRECTION INPUT ;
    USE SIGNAL ;
    PORT
      LAYER met2 ;
        RECT 1700.710 0.000 1700.990 4.000 ;
    END
  END la_data_in[65]
  PIN la_data_in[66]
    DIRECTION INPUT ;
    USE SIGNAL ;
    PORT
      LAYER met2 ;
        RECT 1717.270 0.000 1717.550 4.000 ;
    END
  END la_data_in[66]
  PIN la_data_in[67]
    DIRECTION INPUT ;
    USE SIGNAL ;
    PORT
      LAYER met2 ;
        RECT 1733.830 0.000 1734.110 4.000 ;
    END
  END la_data_in[67]
  PIN la_data_in[68]
    DIRECTION INPUT ;
    USE SIGNAL ;
    PORT
      LAYER met2 ;
        RECT 1750.390 0.000 1750.670 4.000 ;
    END
  END la_data_in[68]
  PIN la_data_in[69]
    DIRECTION INPUT ;
    USE SIGNAL ;
    PORT
      LAYER met2 ;
        RECT 1766.950 0.000 1767.230 4.000 ;
    END
  END la_data_in[69]
  PIN la_data_in[6]
    DIRECTION INPUT ;
    USE SIGNAL ;
    PORT
      LAYER met2 ;
        RECT 723.670 0.000 723.950 4.000 ;
    END
  END la_data_in[6]
  PIN la_data_in[70]
    DIRECTION INPUT ;
    USE SIGNAL ;
    PORT
      LAYER met2 ;
        RECT 1783.510 0.000 1783.790 4.000 ;
    END
  END la_data_in[70]
  PIN la_data_in[71]
    DIRECTION INPUT ;
    USE SIGNAL ;
    PORT
      LAYER met2 ;
        RECT 1800.070 0.000 1800.350 4.000 ;
    END
  END la_data_in[71]
  PIN la_data_in[72]
    DIRECTION INPUT ;
    USE SIGNAL ;
    PORT
      LAYER met2 ;
        RECT 1816.630 0.000 1816.910 4.000 ;
    END
  END la_data_in[72]
  PIN la_data_in[73]
    DIRECTION INPUT ;
    USE SIGNAL ;
    PORT
      LAYER met2 ;
        RECT 1833.190 0.000 1833.470 4.000 ;
    END
  END la_data_in[73]
  PIN la_data_in[74]
    DIRECTION INPUT ;
    USE SIGNAL ;
    PORT
      LAYER met2 ;
        RECT 1849.750 0.000 1850.030 4.000 ;
    END
  END la_data_in[74]
  PIN la_data_in[75]
    DIRECTION INPUT ;
    USE SIGNAL ;
    PORT
      LAYER met2 ;
        RECT 1866.310 0.000 1866.590 4.000 ;
    END
  END la_data_in[75]
  PIN la_data_in[76]
    DIRECTION INPUT ;
    USE SIGNAL ;
    PORT
      LAYER met2 ;
        RECT 1882.870 0.000 1883.150 4.000 ;
    END
  END la_data_in[76]
  PIN la_data_in[77]
    DIRECTION INPUT ;
    USE SIGNAL ;
    PORT
      LAYER met2 ;
        RECT 1899.430 0.000 1899.710 4.000 ;
    END
  END la_data_in[77]
  PIN la_data_in[78]
    DIRECTION INPUT ;
    USE SIGNAL ;
    PORT
      LAYER met2 ;
        RECT 1915.990 0.000 1916.270 4.000 ;
    END
  END la_data_in[78]
  PIN la_data_in[79]
    DIRECTION INPUT ;
    USE SIGNAL ;
    PORT
      LAYER met2 ;
        RECT 1932.550 0.000 1932.830 4.000 ;
    END
  END la_data_in[79]
  PIN la_data_in[7]
    DIRECTION INPUT ;
    USE SIGNAL ;
    PORT
      LAYER met2 ;
        RECT 740.230 0.000 740.510 4.000 ;
    END
  END la_data_in[7]
  PIN la_data_in[80]
    DIRECTION INPUT ;
    USE SIGNAL ;
    PORT
      LAYER met2 ;
        RECT 1949.110 0.000 1949.390 4.000 ;
    END
  END la_data_in[80]
  PIN la_data_in[81]
    DIRECTION INPUT ;
    USE SIGNAL ;
    PORT
      LAYER met2 ;
        RECT 1965.670 0.000 1965.950 4.000 ;
    END
  END la_data_in[81]
  PIN la_data_in[82]
    DIRECTION INPUT ;
    USE SIGNAL ;
    PORT
      LAYER met2 ;
        RECT 1982.230 0.000 1982.510 4.000 ;
    END
  END la_data_in[82]
  PIN la_data_in[83]
    DIRECTION INPUT ;
    USE SIGNAL ;
    PORT
      LAYER met2 ;
        RECT 1998.790 0.000 1999.070 4.000 ;
    END
  END la_data_in[83]
  PIN la_data_in[84]
    DIRECTION INPUT ;
    USE SIGNAL ;
    PORT
      LAYER met2 ;
        RECT 2015.350 0.000 2015.630 4.000 ;
    END
  END la_data_in[84]
  PIN la_data_in[85]
    DIRECTION INPUT ;
    USE SIGNAL ;
    PORT
      LAYER met2 ;
        RECT 2031.910 0.000 2032.190 4.000 ;
    END
  END la_data_in[85]
  PIN la_data_in[86]
    DIRECTION INPUT ;
    USE SIGNAL ;
    PORT
      LAYER met2 ;
        RECT 2048.470 0.000 2048.750 4.000 ;
    END
  END la_data_in[86]
  PIN la_data_in[87]
    DIRECTION INPUT ;
    USE SIGNAL ;
    PORT
      LAYER met2 ;
        RECT 2065.030 0.000 2065.310 4.000 ;
    END
  END la_data_in[87]
  PIN la_data_in[88]
    DIRECTION INPUT ;
    USE SIGNAL ;
    PORT
      LAYER met2 ;
        RECT 2081.590 0.000 2081.870 4.000 ;
    END
  END la_data_in[88]
  PIN la_data_in[89]
    DIRECTION INPUT ;
    USE SIGNAL ;
    PORT
      LAYER met2 ;
        RECT 2098.150 0.000 2098.430 4.000 ;
    END
  END la_data_in[89]
  PIN la_data_in[8]
    DIRECTION INPUT ;
    USE SIGNAL ;
    PORT
      LAYER met2 ;
        RECT 756.790 0.000 757.070 4.000 ;
    END
  END la_data_in[8]
  PIN la_data_in[90]
    DIRECTION INPUT ;
    USE SIGNAL ;
    PORT
      LAYER met2 ;
        RECT 2114.710 0.000 2114.990 4.000 ;
    END
  END la_data_in[90]
  PIN la_data_in[91]
    DIRECTION INPUT ;
    USE SIGNAL ;
    PORT
      LAYER met2 ;
        RECT 2131.270 0.000 2131.550 4.000 ;
    END
  END la_data_in[91]
  PIN la_data_in[92]
    DIRECTION INPUT ;
    USE SIGNAL ;
    PORT
      LAYER met2 ;
        RECT 2147.830 0.000 2148.110 4.000 ;
    END
  END la_data_in[92]
  PIN la_data_in[93]
    DIRECTION INPUT ;
    USE SIGNAL ;
    PORT
      LAYER met2 ;
        RECT 2164.390 0.000 2164.670 4.000 ;
    END
  END la_data_in[93]
  PIN la_data_in[94]
    DIRECTION INPUT ;
    USE SIGNAL ;
    PORT
      LAYER met2 ;
        RECT 2180.950 0.000 2181.230 4.000 ;
    END
  END la_data_in[94]
  PIN la_data_in[95]
    DIRECTION INPUT ;
    USE SIGNAL ;
    PORT
      LAYER met2 ;
        RECT 2197.510 0.000 2197.790 4.000 ;
    END
  END la_data_in[95]
  PIN la_data_in[96]
    DIRECTION INPUT ;
    USE SIGNAL ;
    PORT
      LAYER met2 ;
        RECT 2214.070 0.000 2214.350 4.000 ;
    END
  END la_data_in[96]
  PIN la_data_in[97]
    DIRECTION INPUT ;
    USE SIGNAL ;
    PORT
      LAYER met2 ;
        RECT 2230.630 0.000 2230.910 4.000 ;
    END
  END la_data_in[97]
  PIN la_data_in[98]
    DIRECTION INPUT ;
    USE SIGNAL ;
    PORT
      LAYER met2 ;
        RECT 2247.190 0.000 2247.470 4.000 ;
    END
  END la_data_in[98]
  PIN la_data_in[99]
    DIRECTION INPUT ;
    USE SIGNAL ;
    PORT
      LAYER met2 ;
        RECT 2263.750 0.000 2264.030 4.000 ;
    END
  END la_data_in[99]
  PIN la_data_in[9]
    DIRECTION INPUT ;
    USE SIGNAL ;
    PORT
      LAYER met2 ;
        RECT 773.350 0.000 773.630 4.000 ;
    END
  END la_data_in[9]
  PIN la_data_out[0]
    DIRECTION OUTPUT TRISTATE ;
    USE SIGNAL ;
    PORT
      LAYER met2 ;
        RECT 629.830 0.000 630.110 4.000 ;
    END
  END la_data_out[0]
  PIN la_data_out[100]
    DIRECTION OUTPUT TRISTATE ;
    USE SIGNAL ;
    PORT
      LAYER met2 ;
        RECT 2285.830 0.000 2286.110 4.000 ;
    END
  END la_data_out[100]
  PIN la_data_out[101]
    DIRECTION OUTPUT TRISTATE ;
    USE SIGNAL ;
    PORT
      LAYER met2 ;
        RECT 2302.390 0.000 2302.670 4.000 ;
    END
  END la_data_out[101]
  PIN la_data_out[102]
    DIRECTION OUTPUT TRISTATE ;
    USE SIGNAL ;
    PORT
      LAYER met2 ;
        RECT 2318.950 0.000 2319.230 4.000 ;
    END
  END la_data_out[102]
  PIN la_data_out[103]
    DIRECTION OUTPUT TRISTATE ;
    USE SIGNAL ;
    PORT
      LAYER met2 ;
        RECT 2335.510 0.000 2335.790 4.000 ;
    END
  END la_data_out[103]
  PIN la_data_out[104]
    DIRECTION OUTPUT TRISTATE ;
    USE SIGNAL ;
    PORT
      LAYER met2 ;
        RECT 2352.070 0.000 2352.350 4.000 ;
    END
  END la_data_out[104]
  PIN la_data_out[105]
    DIRECTION OUTPUT TRISTATE ;
    USE SIGNAL ;
    PORT
      LAYER met2 ;
        RECT 2368.630 0.000 2368.910 4.000 ;
    END
  END la_data_out[105]
  PIN la_data_out[106]
    DIRECTION OUTPUT TRISTATE ;
    USE SIGNAL ;
    PORT
      LAYER met2 ;
        RECT 2385.190 0.000 2385.470 4.000 ;
    END
  END la_data_out[106]
  PIN la_data_out[107]
    DIRECTION OUTPUT TRISTATE ;
    USE SIGNAL ;
    PORT
      LAYER met2 ;
        RECT 2401.750 0.000 2402.030 4.000 ;
    END
  END la_data_out[107]
  PIN la_data_out[108]
    DIRECTION OUTPUT TRISTATE ;
    USE SIGNAL ;
    PORT
      LAYER met2 ;
        RECT 2418.310 0.000 2418.590 4.000 ;
    END
  END la_data_out[108]
  PIN la_data_out[109]
    DIRECTION OUTPUT TRISTATE ;
    USE SIGNAL ;
    PORT
      LAYER met2 ;
        RECT 2434.870 0.000 2435.150 4.000 ;
    END
  END la_data_out[109]
  PIN la_data_out[10]
    DIRECTION OUTPUT TRISTATE ;
    USE SIGNAL ;
    PORT
      LAYER met2 ;
        RECT 795.430 0.000 795.710 4.000 ;
    END
  END la_data_out[10]
  PIN la_data_out[110]
    DIRECTION OUTPUT TRISTATE ;
    USE SIGNAL ;
    PORT
      LAYER met2 ;
        RECT 2451.430 0.000 2451.710 4.000 ;
    END
  END la_data_out[110]
  PIN la_data_out[111]
    DIRECTION OUTPUT TRISTATE ;
    USE SIGNAL ;
    PORT
      LAYER met2 ;
        RECT 2467.990 0.000 2468.270 4.000 ;
    END
  END la_data_out[111]
  PIN la_data_out[112]
    DIRECTION OUTPUT TRISTATE ;
    USE SIGNAL ;
    PORT
      LAYER met2 ;
        RECT 2484.550 0.000 2484.830 4.000 ;
    END
  END la_data_out[112]
  PIN la_data_out[113]
    DIRECTION OUTPUT TRISTATE ;
    USE SIGNAL ;
    PORT
      LAYER met2 ;
        RECT 2501.110 0.000 2501.390 4.000 ;
    END
  END la_data_out[113]
  PIN la_data_out[114]
    DIRECTION OUTPUT TRISTATE ;
    USE SIGNAL ;
    PORT
      LAYER met2 ;
        RECT 2517.670 0.000 2517.950 4.000 ;
    END
  END la_data_out[114]
  PIN la_data_out[115]
    DIRECTION OUTPUT TRISTATE ;
    USE SIGNAL ;
    PORT
      LAYER met2 ;
        RECT 2534.230 0.000 2534.510 4.000 ;
    END
  END la_data_out[115]
  PIN la_data_out[116]
    DIRECTION OUTPUT TRISTATE ;
    USE SIGNAL ;
    PORT
      LAYER met2 ;
        RECT 2550.790 0.000 2551.070 4.000 ;
    END
  END la_data_out[116]
  PIN la_data_out[117]
    DIRECTION OUTPUT TRISTATE ;
    USE SIGNAL ;
    PORT
      LAYER met2 ;
        RECT 2567.350 0.000 2567.630 4.000 ;
    END
  END la_data_out[117]
  PIN la_data_out[118]
    DIRECTION OUTPUT TRISTATE ;
    USE SIGNAL ;
    PORT
      LAYER met2 ;
        RECT 2583.910 0.000 2584.190 4.000 ;
    END
  END la_data_out[118]
  PIN la_data_out[119]
    DIRECTION OUTPUT TRISTATE ;
    USE SIGNAL ;
    PORT
      LAYER met2 ;
        RECT 2600.470 0.000 2600.750 4.000 ;
    END
  END la_data_out[119]
  PIN la_data_out[11]
    DIRECTION OUTPUT TRISTATE ;
    USE SIGNAL ;
    PORT
      LAYER met2 ;
        RECT 811.990 0.000 812.270 4.000 ;
    END
  END la_data_out[11]
  PIN la_data_out[120]
    DIRECTION OUTPUT TRISTATE ;
    USE SIGNAL ;
    PORT
      LAYER met2 ;
        RECT 2617.030 0.000 2617.310 4.000 ;
    END
  END la_data_out[120]
  PIN la_data_out[121]
    DIRECTION OUTPUT TRISTATE ;
    USE SIGNAL ;
    PORT
      LAYER met2 ;
        RECT 2633.590 0.000 2633.870 4.000 ;
    END
  END la_data_out[121]
  PIN la_data_out[122]
    DIRECTION OUTPUT TRISTATE ;
    USE SIGNAL ;
    PORT
      LAYER met2 ;
        RECT 2650.150 0.000 2650.430 4.000 ;
    END
  END la_data_out[122]
  PIN la_data_out[123]
    DIRECTION OUTPUT TRISTATE ;
    USE SIGNAL ;
    PORT
      LAYER met2 ;
        RECT 2666.710 0.000 2666.990 4.000 ;
    END
  END la_data_out[123]
  PIN la_data_out[124]
    DIRECTION OUTPUT TRISTATE ;
    USE SIGNAL ;
    PORT
      LAYER met2 ;
        RECT 2683.270 0.000 2683.550 4.000 ;
    END
  END la_data_out[124]
  PIN la_data_out[125]
    DIRECTION OUTPUT TRISTATE ;
    USE SIGNAL ;
    PORT
      LAYER met2 ;
        RECT 2699.830 0.000 2700.110 4.000 ;
    END
  END la_data_out[125]
  PIN la_data_out[126]
    DIRECTION OUTPUT TRISTATE ;
    USE SIGNAL ;
    PORT
      LAYER met2 ;
        RECT 2716.390 0.000 2716.670 4.000 ;
    END
  END la_data_out[126]
  PIN la_data_out[127]
    DIRECTION OUTPUT TRISTATE ;
    USE SIGNAL ;
    PORT
      LAYER met2 ;
        RECT 2732.950 0.000 2733.230 4.000 ;
    END
  END la_data_out[127]
  PIN la_data_out[12]
    DIRECTION OUTPUT TRISTATE ;
    USE SIGNAL ;
    PORT
      LAYER met2 ;
        RECT 828.550 0.000 828.830 4.000 ;
    END
  END la_data_out[12]
  PIN la_data_out[13]
    DIRECTION OUTPUT TRISTATE ;
    USE SIGNAL ;
    PORT
      LAYER met2 ;
        RECT 845.110 0.000 845.390 4.000 ;
    END
  END la_data_out[13]
  PIN la_data_out[14]
    DIRECTION OUTPUT TRISTATE ;
    USE SIGNAL ;
    PORT
      LAYER met2 ;
        RECT 861.670 0.000 861.950 4.000 ;
    END
  END la_data_out[14]
  PIN la_data_out[15]
    DIRECTION OUTPUT TRISTATE ;
    USE SIGNAL ;
    PORT
      LAYER met2 ;
        RECT 878.230 0.000 878.510 4.000 ;
    END
  END la_data_out[15]
  PIN la_data_out[16]
    DIRECTION OUTPUT TRISTATE ;
    USE SIGNAL ;
    PORT
      LAYER met2 ;
        RECT 894.790 0.000 895.070 4.000 ;
    END
  END la_data_out[16]
  PIN la_data_out[17]
    DIRECTION OUTPUT TRISTATE ;
    USE SIGNAL ;
    PORT
      LAYER met2 ;
        RECT 911.350 0.000 911.630 4.000 ;
    END
  END la_data_out[17]
  PIN la_data_out[18]
    DIRECTION OUTPUT TRISTATE ;
    USE SIGNAL ;
    PORT
      LAYER met2 ;
        RECT 927.910 0.000 928.190 4.000 ;
    END
  END la_data_out[18]
  PIN la_data_out[19]
    DIRECTION OUTPUT TRISTATE ;
    USE SIGNAL ;
    PORT
      LAYER met2 ;
        RECT 944.470 0.000 944.750 4.000 ;
    END
  END la_data_out[19]
  PIN la_data_out[1]
    DIRECTION OUTPUT TRISTATE ;
    USE SIGNAL ;
    PORT
      LAYER met2 ;
        RECT 646.390 0.000 646.670 4.000 ;
    END
  END la_data_out[1]
  PIN la_data_out[20]
    DIRECTION OUTPUT TRISTATE ;
    USE SIGNAL ;
    PORT
      LAYER met2 ;
        RECT 961.030 0.000 961.310 4.000 ;
    END
  END la_data_out[20]
  PIN la_data_out[21]
    DIRECTION OUTPUT TRISTATE ;
    USE SIGNAL ;
    PORT
      LAYER met2 ;
        RECT 977.590 0.000 977.870 4.000 ;
    END
  END la_data_out[21]
  PIN la_data_out[22]
    DIRECTION OUTPUT TRISTATE ;
    USE SIGNAL ;
    PORT
      LAYER met2 ;
        RECT 994.150 0.000 994.430 4.000 ;
    END
  END la_data_out[22]
  PIN la_data_out[23]
    DIRECTION OUTPUT TRISTATE ;
    USE SIGNAL ;
    PORT
      LAYER met2 ;
        RECT 1010.710 0.000 1010.990 4.000 ;
    END
  END la_data_out[23]
  PIN la_data_out[24]
    DIRECTION OUTPUT TRISTATE ;
    USE SIGNAL ;
    PORT
      LAYER met2 ;
        RECT 1027.270 0.000 1027.550 4.000 ;
    END
  END la_data_out[24]
  PIN la_data_out[25]
    DIRECTION OUTPUT TRISTATE ;
    USE SIGNAL ;
    PORT
      LAYER met2 ;
        RECT 1043.830 0.000 1044.110 4.000 ;
    END
  END la_data_out[25]
  PIN la_data_out[26]
    DIRECTION OUTPUT TRISTATE ;
    USE SIGNAL ;
    PORT
      LAYER met2 ;
        RECT 1060.390 0.000 1060.670 4.000 ;
    END
  END la_data_out[26]
  PIN la_data_out[27]
    DIRECTION OUTPUT TRISTATE ;
    USE SIGNAL ;
    PORT
      LAYER met2 ;
        RECT 1076.950 0.000 1077.230 4.000 ;
    END
  END la_data_out[27]
  PIN la_data_out[28]
    DIRECTION OUTPUT TRISTATE ;
    USE SIGNAL ;
    PORT
      LAYER met2 ;
        RECT 1093.510 0.000 1093.790 4.000 ;
    END
  END la_data_out[28]
  PIN la_data_out[29]
    DIRECTION OUTPUT TRISTATE ;
    USE SIGNAL ;
    PORT
      LAYER met2 ;
        RECT 1110.070 0.000 1110.350 4.000 ;
    END
  END la_data_out[29]
  PIN la_data_out[2]
    DIRECTION OUTPUT TRISTATE ;
    USE SIGNAL ;
    PORT
      LAYER met2 ;
        RECT 662.950 0.000 663.230 4.000 ;
    END
  END la_data_out[2]
  PIN la_data_out[30]
    DIRECTION OUTPUT TRISTATE ;
    USE SIGNAL ;
    PORT
      LAYER met2 ;
        RECT 1126.630 0.000 1126.910 4.000 ;
    END
  END la_data_out[30]
  PIN la_data_out[31]
    DIRECTION OUTPUT TRISTATE ;
    USE SIGNAL ;
    PORT
      LAYER met2 ;
        RECT 1143.190 0.000 1143.470 4.000 ;
    END
  END la_data_out[31]
  PIN la_data_out[32]
    DIRECTION OUTPUT TRISTATE ;
    USE SIGNAL ;
    PORT
      LAYER met2 ;
        RECT 1159.750 0.000 1160.030 4.000 ;
    END
  END la_data_out[32]
  PIN la_data_out[33]
    DIRECTION OUTPUT TRISTATE ;
    USE SIGNAL ;
    PORT
      LAYER met2 ;
        RECT 1176.310 0.000 1176.590 4.000 ;
    END
  END la_data_out[33]
  PIN la_data_out[34]
    DIRECTION OUTPUT TRISTATE ;
    USE SIGNAL ;
    PORT
      LAYER met2 ;
        RECT 1192.870 0.000 1193.150 4.000 ;
    END
  END la_data_out[34]
  PIN la_data_out[35]
    DIRECTION OUTPUT TRISTATE ;
    USE SIGNAL ;
    PORT
      LAYER met2 ;
        RECT 1209.430 0.000 1209.710 4.000 ;
    END
  END la_data_out[35]
  PIN la_data_out[36]
    DIRECTION OUTPUT TRISTATE ;
    USE SIGNAL ;
    PORT
      LAYER met2 ;
        RECT 1225.990 0.000 1226.270 4.000 ;
    END
  END la_data_out[36]
  PIN la_data_out[37]
    DIRECTION OUTPUT TRISTATE ;
    USE SIGNAL ;
    PORT
      LAYER met2 ;
        RECT 1242.550 0.000 1242.830 4.000 ;
    END
  END la_data_out[37]
  PIN la_data_out[38]
    DIRECTION OUTPUT TRISTATE ;
    USE SIGNAL ;
    PORT
      LAYER met2 ;
        RECT 1259.110 0.000 1259.390 4.000 ;
    END
  END la_data_out[38]
  PIN la_data_out[39]
    DIRECTION OUTPUT TRISTATE ;
    USE SIGNAL ;
    PORT
      LAYER met2 ;
        RECT 1275.670 0.000 1275.950 4.000 ;
    END
  END la_data_out[39]
  PIN la_data_out[3]
    DIRECTION OUTPUT TRISTATE ;
    USE SIGNAL ;
    PORT
      LAYER met2 ;
        RECT 679.510 0.000 679.790 4.000 ;
    END
  END la_data_out[3]
  PIN la_data_out[40]
    DIRECTION OUTPUT TRISTATE ;
    USE SIGNAL ;
    PORT
      LAYER met2 ;
        RECT 1292.230 0.000 1292.510 4.000 ;
    END
  END la_data_out[40]
  PIN la_data_out[41]
    DIRECTION OUTPUT TRISTATE ;
    USE SIGNAL ;
    PORT
      LAYER met2 ;
        RECT 1308.790 0.000 1309.070 4.000 ;
    END
  END la_data_out[41]
  PIN la_data_out[42]
    DIRECTION OUTPUT TRISTATE ;
    USE SIGNAL ;
    PORT
      LAYER met2 ;
        RECT 1325.350 0.000 1325.630 4.000 ;
    END
  END la_data_out[42]
  PIN la_data_out[43]
    DIRECTION OUTPUT TRISTATE ;
    USE SIGNAL ;
    PORT
      LAYER met2 ;
        RECT 1341.910 0.000 1342.190 4.000 ;
    END
  END la_data_out[43]
  PIN la_data_out[44]
    DIRECTION OUTPUT TRISTATE ;
    USE SIGNAL ;
    PORT
      LAYER met2 ;
        RECT 1358.470 0.000 1358.750 4.000 ;
    END
  END la_data_out[44]
  PIN la_data_out[45]
    DIRECTION OUTPUT TRISTATE ;
    USE SIGNAL ;
    PORT
      LAYER met2 ;
        RECT 1375.030 0.000 1375.310 4.000 ;
    END
  END la_data_out[45]
  PIN la_data_out[46]
    DIRECTION OUTPUT TRISTATE ;
    USE SIGNAL ;
    PORT
      LAYER met2 ;
        RECT 1391.590 0.000 1391.870 4.000 ;
    END
  END la_data_out[46]
  PIN la_data_out[47]
    DIRECTION OUTPUT TRISTATE ;
    USE SIGNAL ;
    PORT
      LAYER met2 ;
        RECT 1408.150 0.000 1408.430 4.000 ;
    END
  END la_data_out[47]
  PIN la_data_out[48]
    DIRECTION OUTPUT TRISTATE ;
    USE SIGNAL ;
    PORT
      LAYER met2 ;
        RECT 1424.710 0.000 1424.990 4.000 ;
    END
  END la_data_out[48]
  PIN la_data_out[49]
    DIRECTION OUTPUT TRISTATE ;
    USE SIGNAL ;
    PORT
      LAYER met2 ;
        RECT 1441.270 0.000 1441.550 4.000 ;
    END
  END la_data_out[49]
  PIN la_data_out[4]
    DIRECTION OUTPUT TRISTATE ;
    USE SIGNAL ;
    PORT
      LAYER met2 ;
        RECT 696.070 0.000 696.350 4.000 ;
    END
  END la_data_out[4]
  PIN la_data_out[50]
    DIRECTION OUTPUT TRISTATE ;
    USE SIGNAL ;
    PORT
      LAYER met2 ;
        RECT 1457.830 0.000 1458.110 4.000 ;
    END
  END la_data_out[50]
  PIN la_data_out[51]
    DIRECTION OUTPUT TRISTATE ;
    USE SIGNAL ;
    PORT
      LAYER met2 ;
        RECT 1474.390 0.000 1474.670 4.000 ;
    END
  END la_data_out[51]
  PIN la_data_out[52]
    DIRECTION OUTPUT TRISTATE ;
    USE SIGNAL ;
    PORT
      LAYER met2 ;
        RECT 1490.950 0.000 1491.230 4.000 ;
    END
  END la_data_out[52]
  PIN la_data_out[53]
    DIRECTION OUTPUT TRISTATE ;
    USE SIGNAL ;
    PORT
      LAYER met2 ;
        RECT 1507.510 0.000 1507.790 4.000 ;
    END
  END la_data_out[53]
  PIN la_data_out[54]
    DIRECTION OUTPUT TRISTATE ;
    USE SIGNAL ;
    PORT
      LAYER met2 ;
        RECT 1524.070 0.000 1524.350 4.000 ;
    END
  END la_data_out[54]
  PIN la_data_out[55]
    DIRECTION OUTPUT TRISTATE ;
    USE SIGNAL ;
    PORT
      LAYER met2 ;
        RECT 1540.630 0.000 1540.910 4.000 ;
    END
  END la_data_out[55]
  PIN la_data_out[56]
    DIRECTION OUTPUT TRISTATE ;
    USE SIGNAL ;
    PORT
      LAYER met2 ;
        RECT 1557.190 0.000 1557.470 4.000 ;
    END
  END la_data_out[56]
  PIN la_data_out[57]
    DIRECTION OUTPUT TRISTATE ;
    USE SIGNAL ;
    PORT
      LAYER met2 ;
        RECT 1573.750 0.000 1574.030 4.000 ;
    END
  END la_data_out[57]
  PIN la_data_out[58]
    DIRECTION OUTPUT TRISTATE ;
    USE SIGNAL ;
    PORT
      LAYER met2 ;
        RECT 1590.310 0.000 1590.590 4.000 ;
    END
  END la_data_out[58]
  PIN la_data_out[59]
    DIRECTION OUTPUT TRISTATE ;
    USE SIGNAL ;
    PORT
      LAYER met2 ;
        RECT 1606.870 0.000 1607.150 4.000 ;
    END
  END la_data_out[59]
  PIN la_data_out[5]
    DIRECTION OUTPUT TRISTATE ;
    USE SIGNAL ;
    PORT
      LAYER met2 ;
        RECT 712.630 0.000 712.910 4.000 ;
    END
  END la_data_out[5]
  PIN la_data_out[60]
    DIRECTION OUTPUT TRISTATE ;
    USE SIGNAL ;
    PORT
      LAYER met2 ;
        RECT 1623.430 0.000 1623.710 4.000 ;
    END
  END la_data_out[60]
  PIN la_data_out[61]
    DIRECTION OUTPUT TRISTATE ;
    USE SIGNAL ;
    PORT
      LAYER met2 ;
        RECT 1639.990 0.000 1640.270 4.000 ;
    END
  END la_data_out[61]
  PIN la_data_out[62]
    DIRECTION OUTPUT TRISTATE ;
    USE SIGNAL ;
    PORT
      LAYER met2 ;
        RECT 1656.550 0.000 1656.830 4.000 ;
    END
  END la_data_out[62]
  PIN la_data_out[63]
    DIRECTION OUTPUT TRISTATE ;
    USE SIGNAL ;
    PORT
      LAYER met2 ;
        RECT 1673.110 0.000 1673.390 4.000 ;
    END
  END la_data_out[63]
  PIN la_data_out[64]
    DIRECTION OUTPUT TRISTATE ;
    USE SIGNAL ;
    PORT
      LAYER met2 ;
        RECT 1689.670 0.000 1689.950 4.000 ;
    END
  END la_data_out[64]
  PIN la_data_out[65]
    DIRECTION OUTPUT TRISTATE ;
    USE SIGNAL ;
    PORT
      LAYER met2 ;
        RECT 1706.230 0.000 1706.510 4.000 ;
    END
  END la_data_out[65]
  PIN la_data_out[66]
    DIRECTION OUTPUT TRISTATE ;
    USE SIGNAL ;
    PORT
      LAYER met2 ;
        RECT 1722.790 0.000 1723.070 4.000 ;
    END
  END la_data_out[66]
  PIN la_data_out[67]
    DIRECTION OUTPUT TRISTATE ;
    USE SIGNAL ;
    PORT
      LAYER met2 ;
        RECT 1739.350 0.000 1739.630 4.000 ;
    END
  END la_data_out[67]
  PIN la_data_out[68]
    DIRECTION OUTPUT TRISTATE ;
    USE SIGNAL ;
    PORT
      LAYER met2 ;
        RECT 1755.910 0.000 1756.190 4.000 ;
    END
  END la_data_out[68]
  PIN la_data_out[69]
    DIRECTION OUTPUT TRISTATE ;
    USE SIGNAL ;
    PORT
      LAYER met2 ;
        RECT 1772.470 0.000 1772.750 4.000 ;
    END
  END la_data_out[69]
  PIN la_data_out[6]
    DIRECTION OUTPUT TRISTATE ;
    USE SIGNAL ;
    PORT
      LAYER met2 ;
        RECT 729.190 0.000 729.470 4.000 ;
    END
  END la_data_out[6]
  PIN la_data_out[70]
    DIRECTION OUTPUT TRISTATE ;
    USE SIGNAL ;
    PORT
      LAYER met2 ;
        RECT 1789.030 0.000 1789.310 4.000 ;
    END
  END la_data_out[70]
  PIN la_data_out[71]
    DIRECTION OUTPUT TRISTATE ;
    USE SIGNAL ;
    PORT
      LAYER met2 ;
        RECT 1805.590 0.000 1805.870 4.000 ;
    END
  END la_data_out[71]
  PIN la_data_out[72]
    DIRECTION OUTPUT TRISTATE ;
    USE SIGNAL ;
    PORT
      LAYER met2 ;
        RECT 1822.150 0.000 1822.430 4.000 ;
    END
  END la_data_out[72]
  PIN la_data_out[73]
    DIRECTION OUTPUT TRISTATE ;
    USE SIGNAL ;
    PORT
      LAYER met2 ;
        RECT 1838.710 0.000 1838.990 4.000 ;
    END
  END la_data_out[73]
  PIN la_data_out[74]
    DIRECTION OUTPUT TRISTATE ;
    USE SIGNAL ;
    PORT
      LAYER met2 ;
        RECT 1855.270 0.000 1855.550 4.000 ;
    END
  END la_data_out[74]
  PIN la_data_out[75]
    DIRECTION OUTPUT TRISTATE ;
    USE SIGNAL ;
    PORT
      LAYER met2 ;
        RECT 1871.830 0.000 1872.110 4.000 ;
    END
  END la_data_out[75]
  PIN la_data_out[76]
    DIRECTION OUTPUT TRISTATE ;
    USE SIGNAL ;
    PORT
      LAYER met2 ;
        RECT 1888.390 0.000 1888.670 4.000 ;
    END
  END la_data_out[76]
  PIN la_data_out[77]
    DIRECTION OUTPUT TRISTATE ;
    USE SIGNAL ;
    PORT
      LAYER met2 ;
        RECT 1904.950 0.000 1905.230 4.000 ;
    END
  END la_data_out[77]
  PIN la_data_out[78]
    DIRECTION OUTPUT TRISTATE ;
    USE SIGNAL ;
    PORT
      LAYER met2 ;
        RECT 1921.510 0.000 1921.790 4.000 ;
    END
  END la_data_out[78]
  PIN la_data_out[79]
    DIRECTION OUTPUT TRISTATE ;
    USE SIGNAL ;
    PORT
      LAYER met2 ;
        RECT 1938.070 0.000 1938.350 4.000 ;
    END
  END la_data_out[79]
  PIN la_data_out[7]
    DIRECTION OUTPUT TRISTATE ;
    USE SIGNAL ;
    PORT
      LAYER met2 ;
        RECT 745.750 0.000 746.030 4.000 ;
    END
  END la_data_out[7]
  PIN la_data_out[80]
    DIRECTION OUTPUT TRISTATE ;
    USE SIGNAL ;
    PORT
      LAYER met2 ;
        RECT 1954.630 0.000 1954.910 4.000 ;
    END
  END la_data_out[80]
  PIN la_data_out[81]
    DIRECTION OUTPUT TRISTATE ;
    USE SIGNAL ;
    PORT
      LAYER met2 ;
        RECT 1971.190 0.000 1971.470 4.000 ;
    END
  END la_data_out[81]
  PIN la_data_out[82]
    DIRECTION OUTPUT TRISTATE ;
    USE SIGNAL ;
    PORT
      LAYER met2 ;
        RECT 1987.750 0.000 1988.030 4.000 ;
    END
  END la_data_out[82]
  PIN la_data_out[83]
    DIRECTION OUTPUT TRISTATE ;
    USE SIGNAL ;
    PORT
      LAYER met2 ;
        RECT 2004.310 0.000 2004.590 4.000 ;
    END
  END la_data_out[83]
  PIN la_data_out[84]
    DIRECTION OUTPUT TRISTATE ;
    USE SIGNAL ;
    PORT
      LAYER met2 ;
        RECT 2020.870 0.000 2021.150 4.000 ;
    END
  END la_data_out[84]
  PIN la_data_out[85]
    DIRECTION OUTPUT TRISTATE ;
    USE SIGNAL ;
    PORT
      LAYER met2 ;
        RECT 2037.430 0.000 2037.710 4.000 ;
    END
  END la_data_out[85]
  PIN la_data_out[86]
    DIRECTION OUTPUT TRISTATE ;
    USE SIGNAL ;
    PORT
      LAYER met2 ;
        RECT 2053.990 0.000 2054.270 4.000 ;
    END
  END la_data_out[86]
  PIN la_data_out[87]
    DIRECTION OUTPUT TRISTATE ;
    USE SIGNAL ;
    PORT
      LAYER met2 ;
        RECT 2070.550 0.000 2070.830 4.000 ;
    END
  END la_data_out[87]
  PIN la_data_out[88]
    DIRECTION OUTPUT TRISTATE ;
    USE SIGNAL ;
    PORT
      LAYER met2 ;
        RECT 2087.110 0.000 2087.390 4.000 ;
    END
  END la_data_out[88]
  PIN la_data_out[89]
    DIRECTION OUTPUT TRISTATE ;
    USE SIGNAL ;
    PORT
      LAYER met2 ;
        RECT 2103.670 0.000 2103.950 4.000 ;
    END
  END la_data_out[89]
  PIN la_data_out[8]
    DIRECTION OUTPUT TRISTATE ;
    USE SIGNAL ;
    PORT
      LAYER met2 ;
        RECT 762.310 0.000 762.590 4.000 ;
    END
  END la_data_out[8]
  PIN la_data_out[90]
    DIRECTION OUTPUT TRISTATE ;
    USE SIGNAL ;
    PORT
      LAYER met2 ;
        RECT 2120.230 0.000 2120.510 4.000 ;
    END
  END la_data_out[90]
  PIN la_data_out[91]
    DIRECTION OUTPUT TRISTATE ;
    USE SIGNAL ;
    PORT
      LAYER met2 ;
        RECT 2136.790 0.000 2137.070 4.000 ;
    END
  END la_data_out[91]
  PIN la_data_out[92]
    DIRECTION OUTPUT TRISTATE ;
    USE SIGNAL ;
    PORT
      LAYER met2 ;
        RECT 2153.350 0.000 2153.630 4.000 ;
    END
  END la_data_out[92]
  PIN la_data_out[93]
    DIRECTION OUTPUT TRISTATE ;
    USE SIGNAL ;
    PORT
      LAYER met2 ;
        RECT 2169.910 0.000 2170.190 4.000 ;
    END
  END la_data_out[93]
  PIN la_data_out[94]
    DIRECTION OUTPUT TRISTATE ;
    USE SIGNAL ;
    PORT
      LAYER met2 ;
        RECT 2186.470 0.000 2186.750 4.000 ;
    END
  END la_data_out[94]
  PIN la_data_out[95]
    DIRECTION OUTPUT TRISTATE ;
    USE SIGNAL ;
    PORT
      LAYER met2 ;
        RECT 2203.030 0.000 2203.310 4.000 ;
    END
  END la_data_out[95]
  PIN la_data_out[96]
    DIRECTION OUTPUT TRISTATE ;
    USE SIGNAL ;
    PORT
      LAYER met2 ;
        RECT 2219.590 0.000 2219.870 4.000 ;
    END
  END la_data_out[96]
  PIN la_data_out[97]
    DIRECTION OUTPUT TRISTATE ;
    USE SIGNAL ;
    PORT
      LAYER met2 ;
        RECT 2236.150 0.000 2236.430 4.000 ;
    END
  END la_data_out[97]
  PIN la_data_out[98]
    DIRECTION OUTPUT TRISTATE ;
    USE SIGNAL ;
    PORT
      LAYER met2 ;
        RECT 2252.710 0.000 2252.990 4.000 ;
    END
  END la_data_out[98]
  PIN la_data_out[99]
    DIRECTION OUTPUT TRISTATE ;
    USE SIGNAL ;
    PORT
      LAYER met2 ;
        RECT 2269.270 0.000 2269.550 4.000 ;
    END
  END la_data_out[99]
  PIN la_data_out[9]
    DIRECTION OUTPUT TRISTATE ;
    USE SIGNAL ;
    PORT
      LAYER met2 ;
        RECT 778.870 0.000 779.150 4.000 ;
    END
  END la_data_out[9]
  PIN la_oenb[0]
    DIRECTION INPUT ;
    USE SIGNAL ;
    PORT
      LAYER met2 ;
        RECT 635.350 0.000 635.630 4.000 ;
    END
  END la_oenb[0]
  PIN la_oenb[100]
    DIRECTION INPUT ;
    USE SIGNAL ;
    PORT
      LAYER met2 ;
        RECT 2291.350 0.000 2291.630 4.000 ;
    END
  END la_oenb[100]
  PIN la_oenb[101]
    DIRECTION INPUT ;
    USE SIGNAL ;
    PORT
      LAYER met2 ;
        RECT 2307.910 0.000 2308.190 4.000 ;
    END
  END la_oenb[101]
  PIN la_oenb[102]
    DIRECTION INPUT ;
    USE SIGNAL ;
    PORT
      LAYER met2 ;
        RECT 2324.470 0.000 2324.750 4.000 ;
    END
  END la_oenb[102]
  PIN la_oenb[103]
    DIRECTION INPUT ;
    USE SIGNAL ;
    PORT
      LAYER met2 ;
        RECT 2341.030 0.000 2341.310 4.000 ;
    END
  END la_oenb[103]
  PIN la_oenb[104]
    DIRECTION INPUT ;
    USE SIGNAL ;
    PORT
      LAYER met2 ;
        RECT 2357.590 0.000 2357.870 4.000 ;
    END
  END la_oenb[104]
  PIN la_oenb[105]
    DIRECTION INPUT ;
    USE SIGNAL ;
    PORT
      LAYER met2 ;
        RECT 2374.150 0.000 2374.430 4.000 ;
    END
  END la_oenb[105]
  PIN la_oenb[106]
    DIRECTION INPUT ;
    USE SIGNAL ;
    PORT
      LAYER met2 ;
        RECT 2390.710 0.000 2390.990 4.000 ;
    END
  END la_oenb[106]
  PIN la_oenb[107]
    DIRECTION INPUT ;
    USE SIGNAL ;
    PORT
      LAYER met2 ;
        RECT 2407.270 0.000 2407.550 4.000 ;
    END
  END la_oenb[107]
  PIN la_oenb[108]
    DIRECTION INPUT ;
    USE SIGNAL ;
    PORT
      LAYER met2 ;
        RECT 2423.830 0.000 2424.110 4.000 ;
    END
  END la_oenb[108]
  PIN la_oenb[109]
    DIRECTION INPUT ;
    USE SIGNAL ;
    PORT
      LAYER met2 ;
        RECT 2440.390 0.000 2440.670 4.000 ;
    END
  END la_oenb[109]
  PIN la_oenb[10]
    DIRECTION INPUT ;
    USE SIGNAL ;
    PORT
      LAYER met2 ;
        RECT 800.950 0.000 801.230 4.000 ;
    END
  END la_oenb[10]
  PIN la_oenb[110]
    DIRECTION INPUT ;
    USE SIGNAL ;
    PORT
      LAYER met2 ;
        RECT 2456.950 0.000 2457.230 4.000 ;
    END
  END la_oenb[110]
  PIN la_oenb[111]
    DIRECTION INPUT ;
    USE SIGNAL ;
    PORT
      LAYER met2 ;
        RECT 2473.510 0.000 2473.790 4.000 ;
    END
  END la_oenb[111]
  PIN la_oenb[112]
    DIRECTION INPUT ;
    USE SIGNAL ;
    PORT
      LAYER met2 ;
        RECT 2490.070 0.000 2490.350 4.000 ;
    END
  END la_oenb[112]
  PIN la_oenb[113]
    DIRECTION INPUT ;
    USE SIGNAL ;
    PORT
      LAYER met2 ;
        RECT 2506.630 0.000 2506.910 4.000 ;
    END
  END la_oenb[113]
  PIN la_oenb[114]
    DIRECTION INPUT ;
    USE SIGNAL ;
    PORT
      LAYER met2 ;
        RECT 2523.190 0.000 2523.470 4.000 ;
    END
  END la_oenb[114]
  PIN la_oenb[115]
    DIRECTION INPUT ;
    USE SIGNAL ;
    PORT
      LAYER met2 ;
        RECT 2539.750 0.000 2540.030 4.000 ;
    END
  END la_oenb[115]
  PIN la_oenb[116]
    DIRECTION INPUT ;
    USE SIGNAL ;
    PORT
      LAYER met2 ;
        RECT 2556.310 0.000 2556.590 4.000 ;
    END
  END la_oenb[116]
  PIN la_oenb[117]
    DIRECTION INPUT ;
    USE SIGNAL ;
    PORT
      LAYER met2 ;
        RECT 2572.870 0.000 2573.150 4.000 ;
    END
  END la_oenb[117]
  PIN la_oenb[118]
    DIRECTION INPUT ;
    USE SIGNAL ;
    PORT
      LAYER met2 ;
        RECT 2589.430 0.000 2589.710 4.000 ;
    END
  END la_oenb[118]
  PIN la_oenb[119]
    DIRECTION INPUT ;
    USE SIGNAL ;
    PORT
      LAYER met2 ;
        RECT 2605.990 0.000 2606.270 4.000 ;
    END
  END la_oenb[119]
  PIN la_oenb[11]
    DIRECTION INPUT ;
    USE SIGNAL ;
    PORT
      LAYER met2 ;
        RECT 817.510 0.000 817.790 4.000 ;
    END
  END la_oenb[11]
  PIN la_oenb[120]
    DIRECTION INPUT ;
    USE SIGNAL ;
    PORT
      LAYER met2 ;
        RECT 2622.550 0.000 2622.830 4.000 ;
    END
  END la_oenb[120]
  PIN la_oenb[121]
    DIRECTION INPUT ;
    USE SIGNAL ;
    PORT
      LAYER met2 ;
        RECT 2639.110 0.000 2639.390 4.000 ;
    END
  END la_oenb[121]
  PIN la_oenb[122]
    DIRECTION INPUT ;
    USE SIGNAL ;
    PORT
      LAYER met2 ;
        RECT 2655.670 0.000 2655.950 4.000 ;
    END
  END la_oenb[122]
  PIN la_oenb[123]
    DIRECTION INPUT ;
    USE SIGNAL ;
    PORT
      LAYER met2 ;
        RECT 2672.230 0.000 2672.510 4.000 ;
    END
  END la_oenb[123]
  PIN la_oenb[124]
    DIRECTION INPUT ;
    USE SIGNAL ;
    PORT
      LAYER met2 ;
        RECT 2688.790 0.000 2689.070 4.000 ;
    END
  END la_oenb[124]
  PIN la_oenb[125]
    DIRECTION INPUT ;
    USE SIGNAL ;
    PORT
      LAYER met2 ;
        RECT 2705.350 0.000 2705.630 4.000 ;
    END
  END la_oenb[125]
  PIN la_oenb[126]
    DIRECTION INPUT ;
    USE SIGNAL ;
    PORT
      LAYER met2 ;
        RECT 2721.910 0.000 2722.190 4.000 ;
    END
  END la_oenb[126]
  PIN la_oenb[127]
    DIRECTION INPUT ;
    USE SIGNAL ;
    PORT
      LAYER met2 ;
        RECT 2738.470 0.000 2738.750 4.000 ;
    END
  END la_oenb[127]
  PIN la_oenb[12]
    DIRECTION INPUT ;
    USE SIGNAL ;
    PORT
      LAYER met2 ;
        RECT 834.070 0.000 834.350 4.000 ;
    END
  END la_oenb[12]
  PIN la_oenb[13]
    DIRECTION INPUT ;
    USE SIGNAL ;
    PORT
      LAYER met2 ;
        RECT 850.630 0.000 850.910 4.000 ;
    END
  END la_oenb[13]
  PIN la_oenb[14]
    DIRECTION INPUT ;
    USE SIGNAL ;
    PORT
      LAYER met2 ;
        RECT 867.190 0.000 867.470 4.000 ;
    END
  END la_oenb[14]
  PIN la_oenb[15]
    DIRECTION INPUT ;
    USE SIGNAL ;
    PORT
      LAYER met2 ;
        RECT 883.750 0.000 884.030 4.000 ;
    END
  END la_oenb[15]
  PIN la_oenb[16]
    DIRECTION INPUT ;
    USE SIGNAL ;
    PORT
      LAYER met2 ;
        RECT 900.310 0.000 900.590 4.000 ;
    END
  END la_oenb[16]
  PIN la_oenb[17]
    DIRECTION INPUT ;
    USE SIGNAL ;
    PORT
      LAYER met2 ;
        RECT 916.870 0.000 917.150 4.000 ;
    END
  END la_oenb[17]
  PIN la_oenb[18]
    DIRECTION INPUT ;
    USE SIGNAL ;
    PORT
      LAYER met2 ;
        RECT 933.430 0.000 933.710 4.000 ;
    END
  END la_oenb[18]
  PIN la_oenb[19]
    DIRECTION INPUT ;
    USE SIGNAL ;
    PORT
      LAYER met2 ;
        RECT 949.990 0.000 950.270 4.000 ;
    END
  END la_oenb[19]
  PIN la_oenb[1]
    DIRECTION INPUT ;
    USE SIGNAL ;
    PORT
      LAYER met2 ;
        RECT 651.910 0.000 652.190 4.000 ;
    END
  END la_oenb[1]
  PIN la_oenb[20]
    DIRECTION INPUT ;
    USE SIGNAL ;
    PORT
      LAYER met2 ;
        RECT 966.550 0.000 966.830 4.000 ;
    END
  END la_oenb[20]
  PIN la_oenb[21]
    DIRECTION INPUT ;
    USE SIGNAL ;
    PORT
      LAYER met2 ;
        RECT 983.110 0.000 983.390 4.000 ;
    END
  END la_oenb[21]
  PIN la_oenb[22]
    DIRECTION INPUT ;
    USE SIGNAL ;
    PORT
      LAYER met2 ;
        RECT 999.670 0.000 999.950 4.000 ;
    END
  END la_oenb[22]
  PIN la_oenb[23]
    DIRECTION INPUT ;
    USE SIGNAL ;
    PORT
      LAYER met2 ;
        RECT 1016.230 0.000 1016.510 4.000 ;
    END
  END la_oenb[23]
  PIN la_oenb[24]
    DIRECTION INPUT ;
    USE SIGNAL ;
    PORT
      LAYER met2 ;
        RECT 1032.790 0.000 1033.070 4.000 ;
    END
  END la_oenb[24]
  PIN la_oenb[25]
    DIRECTION INPUT ;
    USE SIGNAL ;
    PORT
      LAYER met2 ;
        RECT 1049.350 0.000 1049.630 4.000 ;
    END
  END la_oenb[25]
  PIN la_oenb[26]
    DIRECTION INPUT ;
    USE SIGNAL ;
    PORT
      LAYER met2 ;
        RECT 1065.910 0.000 1066.190 4.000 ;
    END
  END la_oenb[26]
  PIN la_oenb[27]
    DIRECTION INPUT ;
    USE SIGNAL ;
    PORT
      LAYER met2 ;
        RECT 1082.470 0.000 1082.750 4.000 ;
    END
  END la_oenb[27]
  PIN la_oenb[28]
    DIRECTION INPUT ;
    USE SIGNAL ;
    PORT
      LAYER met2 ;
        RECT 1099.030 0.000 1099.310 4.000 ;
    END
  END la_oenb[28]
  PIN la_oenb[29]
    DIRECTION INPUT ;
    USE SIGNAL ;
    PORT
      LAYER met2 ;
        RECT 1115.590 0.000 1115.870 4.000 ;
    END
  END la_oenb[29]
  PIN la_oenb[2]
    DIRECTION INPUT ;
    USE SIGNAL ;
    PORT
      LAYER met2 ;
        RECT 668.470 0.000 668.750 4.000 ;
    END
  END la_oenb[2]
  PIN la_oenb[30]
    DIRECTION INPUT ;
    USE SIGNAL ;
    PORT
      LAYER met2 ;
        RECT 1132.150 0.000 1132.430 4.000 ;
    END
  END la_oenb[30]
  PIN la_oenb[31]
    DIRECTION INPUT ;
    USE SIGNAL ;
    PORT
      LAYER met2 ;
        RECT 1148.710 0.000 1148.990 4.000 ;
    END
  END la_oenb[31]
  PIN la_oenb[32]
    DIRECTION INPUT ;
    USE SIGNAL ;
    PORT
      LAYER met2 ;
        RECT 1165.270 0.000 1165.550 4.000 ;
    END
  END la_oenb[32]
  PIN la_oenb[33]
    DIRECTION INPUT ;
    USE SIGNAL ;
    PORT
      LAYER met2 ;
        RECT 1181.830 0.000 1182.110 4.000 ;
    END
  END la_oenb[33]
  PIN la_oenb[34]
    DIRECTION INPUT ;
    USE SIGNAL ;
    PORT
      LAYER met2 ;
        RECT 1198.390 0.000 1198.670 4.000 ;
    END
  END la_oenb[34]
  PIN la_oenb[35]
    DIRECTION INPUT ;
    USE SIGNAL ;
    PORT
      LAYER met2 ;
        RECT 1214.950 0.000 1215.230 4.000 ;
    END
  END la_oenb[35]
  PIN la_oenb[36]
    DIRECTION INPUT ;
    USE SIGNAL ;
    PORT
      LAYER met2 ;
        RECT 1231.510 0.000 1231.790 4.000 ;
    END
  END la_oenb[36]
  PIN la_oenb[37]
    DIRECTION INPUT ;
    USE SIGNAL ;
    PORT
      LAYER met2 ;
        RECT 1248.070 0.000 1248.350 4.000 ;
    END
  END la_oenb[37]
  PIN la_oenb[38]
    DIRECTION INPUT ;
    USE SIGNAL ;
    PORT
      LAYER met2 ;
        RECT 1264.630 0.000 1264.910 4.000 ;
    END
  END la_oenb[38]
  PIN la_oenb[39]
    DIRECTION INPUT ;
    USE SIGNAL ;
    PORT
      LAYER met2 ;
        RECT 1281.190 0.000 1281.470 4.000 ;
    END
  END la_oenb[39]
  PIN la_oenb[3]
    DIRECTION INPUT ;
    USE SIGNAL ;
    PORT
      LAYER met2 ;
        RECT 685.030 0.000 685.310 4.000 ;
    END
  END la_oenb[3]
  PIN la_oenb[40]
    DIRECTION INPUT ;
    USE SIGNAL ;
    PORT
      LAYER met2 ;
        RECT 1297.750 0.000 1298.030 4.000 ;
    END
  END la_oenb[40]
  PIN la_oenb[41]
    DIRECTION INPUT ;
    USE SIGNAL ;
    PORT
      LAYER met2 ;
        RECT 1314.310 0.000 1314.590 4.000 ;
    END
  END la_oenb[41]
  PIN la_oenb[42]
    DIRECTION INPUT ;
    USE SIGNAL ;
    PORT
      LAYER met2 ;
        RECT 1330.870 0.000 1331.150 4.000 ;
    END
  END la_oenb[42]
  PIN la_oenb[43]
    DIRECTION INPUT ;
    USE SIGNAL ;
    PORT
      LAYER met2 ;
        RECT 1347.430 0.000 1347.710 4.000 ;
    END
  END la_oenb[43]
  PIN la_oenb[44]
    DIRECTION INPUT ;
    USE SIGNAL ;
    PORT
      LAYER met2 ;
        RECT 1363.990 0.000 1364.270 4.000 ;
    END
  END la_oenb[44]
  PIN la_oenb[45]
    DIRECTION INPUT ;
    USE SIGNAL ;
    PORT
      LAYER met2 ;
        RECT 1380.550 0.000 1380.830 4.000 ;
    END
  END la_oenb[45]
  PIN la_oenb[46]
    DIRECTION INPUT ;
    USE SIGNAL ;
    PORT
      LAYER met2 ;
        RECT 1397.110 0.000 1397.390 4.000 ;
    END
  END la_oenb[46]
  PIN la_oenb[47]
    DIRECTION INPUT ;
    USE SIGNAL ;
    PORT
      LAYER met2 ;
        RECT 1413.670 0.000 1413.950 4.000 ;
    END
  END la_oenb[47]
  PIN la_oenb[48]
    DIRECTION INPUT ;
    USE SIGNAL ;
    PORT
      LAYER met2 ;
        RECT 1430.230 0.000 1430.510 4.000 ;
    END
  END la_oenb[48]
  PIN la_oenb[49]
    DIRECTION INPUT ;
    USE SIGNAL ;
    PORT
      LAYER met2 ;
        RECT 1446.790 0.000 1447.070 4.000 ;
    END
  END la_oenb[49]
  PIN la_oenb[4]
    DIRECTION INPUT ;
    USE SIGNAL ;
    PORT
      LAYER met2 ;
        RECT 701.590 0.000 701.870 4.000 ;
    END
  END la_oenb[4]
  PIN la_oenb[50]
    DIRECTION INPUT ;
    USE SIGNAL ;
    PORT
      LAYER met2 ;
        RECT 1463.350 0.000 1463.630 4.000 ;
    END
  END la_oenb[50]
  PIN la_oenb[51]
    DIRECTION INPUT ;
    USE SIGNAL ;
    PORT
      LAYER met2 ;
        RECT 1479.910 0.000 1480.190 4.000 ;
    END
  END la_oenb[51]
  PIN la_oenb[52]
    DIRECTION INPUT ;
    USE SIGNAL ;
    PORT
      LAYER met2 ;
        RECT 1496.470 0.000 1496.750 4.000 ;
    END
  END la_oenb[52]
  PIN la_oenb[53]
    DIRECTION INPUT ;
    USE SIGNAL ;
    PORT
      LAYER met2 ;
        RECT 1513.030 0.000 1513.310 4.000 ;
    END
  END la_oenb[53]
  PIN la_oenb[54]
    DIRECTION INPUT ;
    USE SIGNAL ;
    PORT
      LAYER met2 ;
        RECT 1529.590 0.000 1529.870 4.000 ;
    END
  END la_oenb[54]
  PIN la_oenb[55]
    DIRECTION INPUT ;
    USE SIGNAL ;
    PORT
      LAYER met2 ;
        RECT 1546.150 0.000 1546.430 4.000 ;
    END
  END la_oenb[55]
  PIN la_oenb[56]
    DIRECTION INPUT ;
    USE SIGNAL ;
    PORT
      LAYER met2 ;
        RECT 1562.710 0.000 1562.990 4.000 ;
    END
  END la_oenb[56]
  PIN la_oenb[57]
    DIRECTION INPUT ;
    USE SIGNAL ;
    PORT
      LAYER met2 ;
        RECT 1579.270 0.000 1579.550 4.000 ;
    END
  END la_oenb[57]
  PIN la_oenb[58]
    DIRECTION INPUT ;
    USE SIGNAL ;
    PORT
      LAYER met2 ;
        RECT 1595.830 0.000 1596.110 4.000 ;
    END
  END la_oenb[58]
  PIN la_oenb[59]
    DIRECTION INPUT ;
    USE SIGNAL ;
    PORT
      LAYER met2 ;
        RECT 1612.390 0.000 1612.670 4.000 ;
    END
  END la_oenb[59]
  PIN la_oenb[5]
    DIRECTION INPUT ;
    USE SIGNAL ;
    PORT
      LAYER met2 ;
        RECT 718.150 0.000 718.430 4.000 ;
    END
  END la_oenb[5]
  PIN la_oenb[60]
    DIRECTION INPUT ;
    USE SIGNAL ;
    PORT
      LAYER met2 ;
        RECT 1628.950 0.000 1629.230 4.000 ;
    END
  END la_oenb[60]
  PIN la_oenb[61]
    DIRECTION INPUT ;
    USE SIGNAL ;
    PORT
      LAYER met2 ;
        RECT 1645.510 0.000 1645.790 4.000 ;
    END
  END la_oenb[61]
  PIN la_oenb[62]
    DIRECTION INPUT ;
    USE SIGNAL ;
    PORT
      LAYER met2 ;
        RECT 1662.070 0.000 1662.350 4.000 ;
    END
  END la_oenb[62]
  PIN la_oenb[63]
    DIRECTION INPUT ;
    USE SIGNAL ;
    PORT
      LAYER met2 ;
        RECT 1678.630 0.000 1678.910 4.000 ;
    END
  END la_oenb[63]
  PIN la_oenb[64]
    DIRECTION INPUT ;
    USE SIGNAL ;
    PORT
      LAYER met2 ;
        RECT 1695.190 0.000 1695.470 4.000 ;
    END
  END la_oenb[64]
  PIN la_oenb[65]
    DIRECTION INPUT ;
    USE SIGNAL ;
    PORT
      LAYER met2 ;
        RECT 1711.750 0.000 1712.030 4.000 ;
    END
  END la_oenb[65]
  PIN la_oenb[66]
    DIRECTION INPUT ;
    USE SIGNAL ;
    PORT
      LAYER met2 ;
        RECT 1728.310 0.000 1728.590 4.000 ;
    END
  END la_oenb[66]
  PIN la_oenb[67]
    DIRECTION INPUT ;
    USE SIGNAL ;
    PORT
      LAYER met2 ;
        RECT 1744.870 0.000 1745.150 4.000 ;
    END
  END la_oenb[67]
  PIN la_oenb[68]
    DIRECTION INPUT ;
    USE SIGNAL ;
    PORT
      LAYER met2 ;
        RECT 1761.430 0.000 1761.710 4.000 ;
    END
  END la_oenb[68]
  PIN la_oenb[69]
    DIRECTION INPUT ;
    USE SIGNAL ;
    PORT
      LAYER met2 ;
        RECT 1777.990 0.000 1778.270 4.000 ;
    END
  END la_oenb[69]
  PIN la_oenb[6]
    DIRECTION INPUT ;
    USE SIGNAL ;
    PORT
      LAYER met2 ;
        RECT 734.710 0.000 734.990 4.000 ;
    END
  END la_oenb[6]
  PIN la_oenb[70]
    DIRECTION INPUT ;
    USE SIGNAL ;
    PORT
      LAYER met2 ;
        RECT 1794.550 0.000 1794.830 4.000 ;
    END
  END la_oenb[70]
  PIN la_oenb[71]
    DIRECTION INPUT ;
    USE SIGNAL ;
    PORT
      LAYER met2 ;
        RECT 1811.110 0.000 1811.390 4.000 ;
    END
  END la_oenb[71]
  PIN la_oenb[72]
    DIRECTION INPUT ;
    USE SIGNAL ;
    PORT
      LAYER met2 ;
        RECT 1827.670 0.000 1827.950 4.000 ;
    END
  END la_oenb[72]
  PIN la_oenb[73]
    DIRECTION INPUT ;
    USE SIGNAL ;
    PORT
      LAYER met2 ;
        RECT 1844.230 0.000 1844.510 4.000 ;
    END
  END la_oenb[73]
  PIN la_oenb[74]
    DIRECTION INPUT ;
    USE SIGNAL ;
    PORT
      LAYER met2 ;
        RECT 1860.790 0.000 1861.070 4.000 ;
    END
  END la_oenb[74]
  PIN la_oenb[75]
    DIRECTION INPUT ;
    USE SIGNAL ;
    PORT
      LAYER met2 ;
        RECT 1877.350 0.000 1877.630 4.000 ;
    END
  END la_oenb[75]
  PIN la_oenb[76]
    DIRECTION INPUT ;
    USE SIGNAL ;
    PORT
      LAYER met2 ;
        RECT 1893.910 0.000 1894.190 4.000 ;
    END
  END la_oenb[76]
  PIN la_oenb[77]
    DIRECTION INPUT ;
    USE SIGNAL ;
    PORT
      LAYER met2 ;
        RECT 1910.470 0.000 1910.750 4.000 ;
    END
  END la_oenb[77]
  PIN la_oenb[78]
    DIRECTION INPUT ;
    USE SIGNAL ;
    PORT
      LAYER met2 ;
        RECT 1927.030 0.000 1927.310 4.000 ;
    END
  END la_oenb[78]
  PIN la_oenb[79]
    DIRECTION INPUT ;
    USE SIGNAL ;
    PORT
      LAYER met2 ;
        RECT 1943.590 0.000 1943.870 4.000 ;
    END
  END la_oenb[79]
  PIN la_oenb[7]
    DIRECTION INPUT ;
    USE SIGNAL ;
    PORT
      LAYER met2 ;
        RECT 751.270 0.000 751.550 4.000 ;
    END
  END la_oenb[7]
  PIN la_oenb[80]
    DIRECTION INPUT ;
    USE SIGNAL ;
    PORT
      LAYER met2 ;
        RECT 1960.150 0.000 1960.430 4.000 ;
    END
  END la_oenb[80]
  PIN la_oenb[81]
    DIRECTION INPUT ;
    USE SIGNAL ;
    PORT
      LAYER met2 ;
        RECT 1976.710 0.000 1976.990 4.000 ;
    END
  END la_oenb[81]
  PIN la_oenb[82]
    DIRECTION INPUT ;
    USE SIGNAL ;
    PORT
      LAYER met2 ;
        RECT 1993.270 0.000 1993.550 4.000 ;
    END
  END la_oenb[82]
  PIN la_oenb[83]
    DIRECTION INPUT ;
    USE SIGNAL ;
    PORT
      LAYER met2 ;
        RECT 2009.830 0.000 2010.110 4.000 ;
    END
  END la_oenb[83]
  PIN la_oenb[84]
    DIRECTION INPUT ;
    USE SIGNAL ;
    PORT
      LAYER met2 ;
        RECT 2026.390 0.000 2026.670 4.000 ;
    END
  END la_oenb[84]
  PIN la_oenb[85]
    DIRECTION INPUT ;
    USE SIGNAL ;
    PORT
      LAYER met2 ;
        RECT 2042.950 0.000 2043.230 4.000 ;
    END
  END la_oenb[85]
  PIN la_oenb[86]
    DIRECTION INPUT ;
    USE SIGNAL ;
    PORT
      LAYER met2 ;
        RECT 2059.510 0.000 2059.790 4.000 ;
    END
  END la_oenb[86]
  PIN la_oenb[87]
    DIRECTION INPUT ;
    USE SIGNAL ;
    PORT
      LAYER met2 ;
        RECT 2076.070 0.000 2076.350 4.000 ;
    END
  END la_oenb[87]
  PIN la_oenb[88]
    DIRECTION INPUT ;
    USE SIGNAL ;
    PORT
      LAYER met2 ;
        RECT 2092.630 0.000 2092.910 4.000 ;
    END
  END la_oenb[88]
  PIN la_oenb[89]
    DIRECTION INPUT ;
    USE SIGNAL ;
    PORT
      LAYER met2 ;
        RECT 2109.190 0.000 2109.470 4.000 ;
    END
  END la_oenb[89]
  PIN la_oenb[8]
    DIRECTION INPUT ;
    USE SIGNAL ;
    PORT
      LAYER met2 ;
        RECT 767.830 0.000 768.110 4.000 ;
    END
  END la_oenb[8]
  PIN la_oenb[90]
    DIRECTION INPUT ;
    USE SIGNAL ;
    PORT
      LAYER met2 ;
        RECT 2125.750 0.000 2126.030 4.000 ;
    END
  END la_oenb[90]
  PIN la_oenb[91]
    DIRECTION INPUT ;
    USE SIGNAL ;
    PORT
      LAYER met2 ;
        RECT 2142.310 0.000 2142.590 4.000 ;
    END
  END la_oenb[91]
  PIN la_oenb[92]
    DIRECTION INPUT ;
    USE SIGNAL ;
    PORT
      LAYER met2 ;
        RECT 2158.870 0.000 2159.150 4.000 ;
    END
  END la_oenb[92]
  PIN la_oenb[93]
    DIRECTION INPUT ;
    USE SIGNAL ;
    PORT
      LAYER met2 ;
        RECT 2175.430 0.000 2175.710 4.000 ;
    END
  END la_oenb[93]
  PIN la_oenb[94]
    DIRECTION INPUT ;
    USE SIGNAL ;
    PORT
      LAYER met2 ;
        RECT 2191.990 0.000 2192.270 4.000 ;
    END
  END la_oenb[94]
  PIN la_oenb[95]
    DIRECTION INPUT ;
    USE SIGNAL ;
    PORT
      LAYER met2 ;
        RECT 2208.550 0.000 2208.830 4.000 ;
    END
  END la_oenb[95]
  PIN la_oenb[96]
    DIRECTION INPUT ;
    USE SIGNAL ;
    PORT
      LAYER met2 ;
        RECT 2225.110 0.000 2225.390 4.000 ;
    END
  END la_oenb[96]
  PIN la_oenb[97]
    DIRECTION INPUT ;
    USE SIGNAL ;
    PORT
      LAYER met2 ;
        RECT 2241.670 0.000 2241.950 4.000 ;
    END
  END la_oenb[97]
  PIN la_oenb[98]
    DIRECTION INPUT ;
    USE SIGNAL ;
    PORT
      LAYER met2 ;
        RECT 2258.230 0.000 2258.510 4.000 ;
    END
  END la_oenb[98]
  PIN la_oenb[99]
    DIRECTION INPUT ;
    USE SIGNAL ;
    PORT
      LAYER met2 ;
        RECT 2274.790 0.000 2275.070 4.000 ;
    END
  END la_oenb[99]
  PIN la_oenb[9]
    DIRECTION INPUT ;
    USE SIGNAL ;
    PORT
      LAYER met2 ;
        RECT 784.390 0.000 784.670 4.000 ;
    END
  END la_oenb[9]
  PIN user_clock2
    DIRECTION INPUT ;
    USE SIGNAL ;
    PORT
      LAYER met2 ;
        RECT 2743.990 0.000 2744.270 4.000 ;
    END
  END user_clock2
  PIN user_irq[0]
    DIRECTION OUTPUT TRISTATE ;
    USE SIGNAL ;
    PORT
      LAYER met2 ;
        RECT 2749.510 0.000 2749.790 4.000 ;
    END
  END user_irq[0]
  PIN user_irq[1]
    DIRECTION OUTPUT TRISTATE ;
    USE SIGNAL ;
    PORT
      LAYER met2 ;
        RECT 2755.030 0.000 2755.310 4.000 ;
    END
  END user_irq[1]
  PIN user_irq[2]
    DIRECTION OUTPUT TRISTATE ;
    USE SIGNAL ;
    PORT
      LAYER met2 ;
        RECT 2760.550 0.000 2760.830 4.000 ;
    END
  END user_irq[2]
  PIN vccd1
    DIRECTION INOUT ;
    USE POWER ;
    PORT
      LAYER met4 ;
        RECT 21.040 10.640 22.640 1749.200 ;
    END
    PORT
      LAYER met4 ;
        RECT 174.640 10.640 176.240 1749.200 ;
    END
    PORT
      LAYER met4 ;
        RECT 328.240 10.640 329.840 1749.200 ;
    END
    PORT
      LAYER met4 ;
        RECT 481.840 10.640 483.440 1749.200 ;
    END
    PORT
      LAYER met4 ;
        RECT 635.440 10.640 637.040 1749.200 ;
    END
    PORT
      LAYER met4 ;
        RECT 789.040 10.640 790.640 1749.200 ;
    END
    PORT
      LAYER met4 ;
        RECT 942.640 10.640 944.240 1749.200 ;
    END
    PORT
      LAYER met4 ;
        RECT 1096.240 10.640 1097.840 1749.200 ;
    END
    PORT
      LAYER met4 ;
        RECT 1249.840 10.640 1251.440 1749.200 ;
    END
    PORT
      LAYER met4 ;
        RECT 1403.440 10.640 1405.040 1749.200 ;
    END
    PORT
      LAYER met4 ;
        RECT 1557.040 10.640 1558.640 1749.200 ;
    END
    PORT
      LAYER met4 ;
        RECT 1710.640 10.640 1712.240 1749.200 ;
    END
    PORT
      LAYER met4 ;
        RECT 1864.240 10.640 1865.840 1749.200 ;
    END
    PORT
      LAYER met4 ;
        RECT 2017.840 10.640 2019.440 1749.200 ;
    END
    PORT
      LAYER met4 ;
        RECT 2171.440 10.640 2173.040 1749.200 ;
    END
    PORT
      LAYER met4 ;
        RECT 2325.040 10.640 2326.640 1749.200 ;
    END
    PORT
      LAYER met4 ;
        RECT 2478.640 10.640 2480.240 1749.200 ;
    END
    PORT
      LAYER met4 ;
        RECT 2632.240 10.640 2633.840 1749.200 ;
    END
    PORT
      LAYER met4 ;
        RECT 2785.840 10.640 2787.440 1749.200 ;
    END
  END vccd1
  PIN vssd1
    DIRECTION INOUT ;
    USE GROUND ;
    PORT
      LAYER met4 ;
        RECT 97.840 10.640 99.440 1749.200 ;
    END
    PORT
      LAYER met4 ;
        RECT 251.440 10.640 253.040 1749.200 ;
    END
    PORT
      LAYER met4 ;
        RECT 405.040 10.640 406.640 1749.200 ;
    END
    PORT
      LAYER met4 ;
        RECT 558.640 10.640 560.240 1749.200 ;
    END
    PORT
      LAYER met4 ;
        RECT 712.240 10.640 713.840 1749.200 ;
    END
    PORT
      LAYER met4 ;
        RECT 865.840 10.640 867.440 1749.200 ;
    END
    PORT
      LAYER met4 ;
        RECT 1019.440 10.640 1021.040 1749.200 ;
    END
    PORT
      LAYER met4 ;
        RECT 1173.040 10.640 1174.640 1749.200 ;
    END
    PORT
      LAYER met4 ;
        RECT 1326.640 10.640 1328.240 1749.200 ;
    END
    PORT
      LAYER met4 ;
        RECT 1480.240 10.640 1481.840 1749.200 ;
    END
    PORT
      LAYER met4 ;
        RECT 1633.840 10.640 1635.440 1749.200 ;
    END
    PORT
      LAYER met4 ;
        RECT 1787.440 10.640 1789.040 1749.200 ;
    END
    PORT
      LAYER met4 ;
        RECT 1941.040 10.640 1942.640 1749.200 ;
    END
    PORT
      LAYER met4 ;
        RECT 2094.640 10.640 2096.240 1749.200 ;
    END
    PORT
      LAYER met4 ;
        RECT 2248.240 10.640 2249.840 1749.200 ;
    END
    PORT
      LAYER met4 ;
        RECT 2401.840 10.640 2403.440 1749.200 ;
    END
    PORT
      LAYER met4 ;
        RECT 2555.440 10.640 2557.040 1749.200 ;
    END
    PORT
      LAYER met4 ;
        RECT 2709.040 10.640 2710.640 1749.200 ;
    END
  END vssd1
  PIN wb_clk_i
    DIRECTION INPUT ;
    USE SIGNAL ;
    ANTENNAGATEAREA 0.852000 ;
    PORT
      LAYER met2 ;
        RECT 39.190 0.000 39.470 4.000 ;
    END
  END wb_clk_i
  PIN wb_rst_i
    DIRECTION INPUT ;
    USE SIGNAL ;
    ANTENNAGATEAREA 0.990000 ;
    PORT
      LAYER met2 ;
        RECT 44.710 0.000 44.990 4.000 ;
    END
  END wb_rst_i
  PIN wbs_ack_o
    DIRECTION OUTPUT TRISTATE ;
    USE SIGNAL ;
    ANTENNADIFFAREA 2.673000 ;
    PORT
      LAYER met2 ;
        RECT 50.230 0.000 50.510 4.000 ;
    END
  END wbs_ack_o
  PIN wbs_adr_i[0]
    DIRECTION INPUT ;
    USE SIGNAL ;
    PORT
      LAYER met2 ;
        RECT 72.310 0.000 72.590 4.000 ;
    END
  END wbs_adr_i[0]
  PIN wbs_adr_i[10]
    DIRECTION INPUT ;
    USE SIGNAL ;
    PORT
      LAYER met2 ;
        RECT 259.990 0.000 260.270 4.000 ;
    END
  END wbs_adr_i[10]
  PIN wbs_adr_i[11]
    DIRECTION INPUT ;
    USE SIGNAL ;
    PORT
      LAYER met2 ;
        RECT 276.550 0.000 276.830 4.000 ;
    END
  END wbs_adr_i[11]
  PIN wbs_adr_i[12]
    DIRECTION INPUT ;
    USE SIGNAL ;
    PORT
      LAYER met2 ;
        RECT 293.110 0.000 293.390 4.000 ;
    END
  END wbs_adr_i[12]
  PIN wbs_adr_i[13]
    DIRECTION INPUT ;
    USE SIGNAL ;
    PORT
      LAYER met2 ;
        RECT 309.670 0.000 309.950 4.000 ;
    END
  END wbs_adr_i[13]
  PIN wbs_adr_i[14]
    DIRECTION INPUT ;
    USE SIGNAL ;
    PORT
      LAYER met2 ;
        RECT 326.230 0.000 326.510 4.000 ;
    END
  END wbs_adr_i[14]
  PIN wbs_adr_i[15]
    DIRECTION INPUT ;
    USE SIGNAL ;
    PORT
      LAYER met2 ;
        RECT 342.790 0.000 343.070 4.000 ;
    END
  END wbs_adr_i[15]
  PIN wbs_adr_i[16]
    DIRECTION INPUT ;
    USE SIGNAL ;
    PORT
      LAYER met2 ;
        RECT 359.350 0.000 359.630 4.000 ;
    END
  END wbs_adr_i[16]
  PIN wbs_adr_i[17]
    DIRECTION INPUT ;
    USE SIGNAL ;
    PORT
      LAYER met2 ;
        RECT 375.910 0.000 376.190 4.000 ;
    END
  END wbs_adr_i[17]
  PIN wbs_adr_i[18]
    DIRECTION INPUT ;
    USE SIGNAL ;
    PORT
      LAYER met2 ;
        RECT 392.470 0.000 392.750 4.000 ;
    END
  END wbs_adr_i[18]
  PIN wbs_adr_i[19]
    DIRECTION INPUT ;
    USE SIGNAL ;
    PORT
      LAYER met2 ;
        RECT 409.030 0.000 409.310 4.000 ;
    END
  END wbs_adr_i[19]
  PIN wbs_adr_i[1]
    DIRECTION INPUT ;
    USE SIGNAL ;
    PORT
      LAYER met2 ;
        RECT 94.390 0.000 94.670 4.000 ;
    END
  END wbs_adr_i[1]
  PIN wbs_adr_i[20]
    DIRECTION INPUT ;
    USE SIGNAL ;
    PORT
      LAYER met2 ;
        RECT 425.590 0.000 425.870 4.000 ;
    END
  END wbs_adr_i[20]
  PIN wbs_adr_i[21]
    DIRECTION INPUT ;
    USE SIGNAL ;
    PORT
      LAYER met2 ;
        RECT 442.150 0.000 442.430 4.000 ;
    END
  END wbs_adr_i[21]
  PIN wbs_adr_i[22]
    DIRECTION INPUT ;
    USE SIGNAL ;
    PORT
      LAYER met2 ;
        RECT 458.710 0.000 458.990 4.000 ;
    END
  END wbs_adr_i[22]
  PIN wbs_adr_i[23]
    DIRECTION INPUT ;
    USE SIGNAL ;
    PORT
      LAYER met2 ;
        RECT 475.270 0.000 475.550 4.000 ;
    END
  END wbs_adr_i[23]
  PIN wbs_adr_i[24]
    DIRECTION INPUT ;
    USE SIGNAL ;
    PORT
      LAYER met2 ;
        RECT 491.830 0.000 492.110 4.000 ;
    END
  END wbs_adr_i[24]
  PIN wbs_adr_i[25]
    DIRECTION INPUT ;
    USE SIGNAL ;
    PORT
      LAYER met2 ;
        RECT 508.390 0.000 508.670 4.000 ;
    END
  END wbs_adr_i[25]
  PIN wbs_adr_i[26]
    DIRECTION INPUT ;
    USE SIGNAL ;
    PORT
      LAYER met2 ;
        RECT 524.950 0.000 525.230 4.000 ;
    END
  END wbs_adr_i[26]
  PIN wbs_adr_i[27]
    DIRECTION INPUT ;
    USE SIGNAL ;
    PORT
      LAYER met2 ;
        RECT 541.510 0.000 541.790 4.000 ;
    END
  END wbs_adr_i[27]
  PIN wbs_adr_i[28]
    DIRECTION INPUT ;
    USE SIGNAL ;
    PORT
      LAYER met2 ;
        RECT 558.070 0.000 558.350 4.000 ;
    END
  END wbs_adr_i[28]
  PIN wbs_adr_i[29]
    DIRECTION INPUT ;
    USE SIGNAL ;
    PORT
      LAYER met2 ;
        RECT 574.630 0.000 574.910 4.000 ;
    END
  END wbs_adr_i[29]
  PIN wbs_adr_i[2]
    DIRECTION INPUT ;
    USE SIGNAL ;
    ANTENNAGATEAREA 0.126000 ;
    PORT
      LAYER met2 ;
        RECT 116.470 0.000 116.750 4.000 ;
    END
  END wbs_adr_i[2]
  PIN wbs_adr_i[30]
    DIRECTION INPUT ;
    USE SIGNAL ;
    PORT
      LAYER met2 ;
        RECT 591.190 0.000 591.470 4.000 ;
    END
  END wbs_adr_i[30]
  PIN wbs_adr_i[31]
    DIRECTION INPUT ;
    USE SIGNAL ;
    PORT
      LAYER met2 ;
        RECT 607.750 0.000 608.030 4.000 ;
    END
  END wbs_adr_i[31]
  PIN wbs_adr_i[3]
    DIRECTION INPUT ;
    USE SIGNAL ;
    ANTENNAGATEAREA 0.126000 ;
    PORT
      LAYER met2 ;
        RECT 138.550 0.000 138.830 4.000 ;
    END
  END wbs_adr_i[3]
  PIN wbs_adr_i[4]
    DIRECTION INPUT ;
    USE SIGNAL ;
    ANTENNAGATEAREA 0.126000 ;
    PORT
      LAYER met2 ;
        RECT 160.630 0.000 160.910 4.000 ;
    END
  END wbs_adr_i[4]
  PIN wbs_adr_i[5]
    DIRECTION INPUT ;
    USE SIGNAL ;
    ANTENNAGATEAREA 0.126000 ;
    PORT
      LAYER met2 ;
        RECT 177.190 0.000 177.470 4.000 ;
    END
  END wbs_adr_i[5]
  PIN wbs_adr_i[6]
    DIRECTION INPUT ;
    USE SIGNAL ;
    ANTENNAGATEAREA 0.126000 ;
    PORT
      LAYER met2 ;
        RECT 193.750 0.000 194.030 4.000 ;
    END
  END wbs_adr_i[6]
  PIN wbs_adr_i[7]
    DIRECTION INPUT ;
    USE SIGNAL ;
    PORT
      LAYER met2 ;
        RECT 210.310 0.000 210.590 4.000 ;
    END
  END wbs_adr_i[7]
  PIN wbs_adr_i[8]
    DIRECTION INPUT ;
    USE SIGNAL ;
    PORT
      LAYER met2 ;
        RECT 226.870 0.000 227.150 4.000 ;
    END
  END wbs_adr_i[8]
  PIN wbs_adr_i[9]
    DIRECTION INPUT ;
    USE SIGNAL ;
    PORT
      LAYER met2 ;
        RECT 243.430 0.000 243.710 4.000 ;
    END
  END wbs_adr_i[9]
  PIN wbs_cyc_i
    DIRECTION INPUT ;
    USE SIGNAL ;
    ANTENNAGATEAREA 0.126000 ;
    PORT
      LAYER met2 ;
        RECT 55.750 0.000 56.030 4.000 ;
    END
  END wbs_cyc_i
  PIN wbs_dat_i[0]
    DIRECTION INPUT ;
    USE SIGNAL ;
    ANTENNAGATEAREA 0.126000 ;
    PORT
      LAYER met2 ;
        RECT 77.830 0.000 78.110 4.000 ;
    END
  END wbs_dat_i[0]
  PIN wbs_dat_i[10]
    DIRECTION INPUT ;
    USE SIGNAL ;
    ANTENNAGATEAREA 0.126000 ;
    PORT
      LAYER met2 ;
        RECT 265.510 0.000 265.790 4.000 ;
    END
  END wbs_dat_i[10]
  PIN wbs_dat_i[11]
    DIRECTION INPUT ;
    USE SIGNAL ;
    ANTENNAGATEAREA 0.126000 ;
    PORT
      LAYER met2 ;
        RECT 282.070 0.000 282.350 4.000 ;
    END
  END wbs_dat_i[11]
  PIN wbs_dat_i[12]
    DIRECTION INPUT ;
    USE SIGNAL ;
    ANTENNAGATEAREA 0.126000 ;
    PORT
      LAYER met2 ;
        RECT 298.630 0.000 298.910 4.000 ;
    END
  END wbs_dat_i[12]
  PIN wbs_dat_i[13]
    DIRECTION INPUT ;
    USE SIGNAL ;
    ANTENNAGATEAREA 0.126000 ;
    PORT
      LAYER met2 ;
        RECT 315.190 0.000 315.470 4.000 ;
    END
  END wbs_dat_i[13]
  PIN wbs_dat_i[14]
    DIRECTION INPUT ;
    USE SIGNAL ;
    ANTENNAGATEAREA 0.126000 ;
    PORT
      LAYER met2 ;
        RECT 331.750 0.000 332.030 4.000 ;
    END
  END wbs_dat_i[14]
  PIN wbs_dat_i[15]
    DIRECTION INPUT ;
    USE SIGNAL ;
    ANTENNAGATEAREA 0.126000 ;
    PORT
      LAYER met2 ;
        RECT 348.310 0.000 348.590 4.000 ;
    END
  END wbs_dat_i[15]
  PIN wbs_dat_i[16]
    DIRECTION INPUT ;
    USE SIGNAL ;
    ANTENNAGATEAREA 0.126000 ;
    PORT
      LAYER met2 ;
        RECT 364.870 0.000 365.150 4.000 ;
    END
  END wbs_dat_i[16]
  PIN wbs_dat_i[17]
    DIRECTION INPUT ;
    USE SIGNAL ;
    ANTENNAGATEAREA 0.126000 ;
    PORT
      LAYER met2 ;
        RECT 381.430 0.000 381.710 4.000 ;
    END
  END wbs_dat_i[17]
  PIN wbs_dat_i[18]
    DIRECTION INPUT ;
    USE SIGNAL ;
    ANTENNAGATEAREA 0.126000 ;
    PORT
      LAYER met2 ;
        RECT 397.990 0.000 398.270 4.000 ;
    END
  END wbs_dat_i[18]
  PIN wbs_dat_i[19]
    DIRECTION INPUT ;
    USE SIGNAL ;
    ANTENNAGATEAREA 0.126000 ;
    PORT
      LAYER met2 ;
        RECT 414.550 0.000 414.830 4.000 ;
    END
  END wbs_dat_i[19]
  PIN wbs_dat_i[1]
    DIRECTION INPUT ;
    USE SIGNAL ;
    ANTENNAGATEAREA 0.126000 ;
    PORT
      LAYER met2 ;
        RECT 99.910 0.000 100.190 4.000 ;
    END
  END wbs_dat_i[1]
  PIN wbs_dat_i[20]
    DIRECTION INPUT ;
    USE SIGNAL ;
    ANTENNAGATEAREA 0.126000 ;
    PORT
      LAYER met2 ;
        RECT 431.110 0.000 431.390 4.000 ;
    END
  END wbs_dat_i[20]
  PIN wbs_dat_i[21]
    DIRECTION INPUT ;
    USE SIGNAL ;
    ANTENNAGATEAREA 0.126000 ;
    PORT
      LAYER met2 ;
        RECT 447.670 0.000 447.950 4.000 ;
    END
  END wbs_dat_i[21]
  PIN wbs_dat_i[22]
    DIRECTION INPUT ;
    USE SIGNAL ;
    ANTENNAGATEAREA 0.126000 ;
    PORT
      LAYER met2 ;
        RECT 464.230 0.000 464.510 4.000 ;
    END
  END wbs_dat_i[22]
  PIN wbs_dat_i[23]
    DIRECTION INPUT ;
    USE SIGNAL ;
    ANTENNAGATEAREA 0.126000 ;
    PORT
      LAYER met2 ;
        RECT 480.790 0.000 481.070 4.000 ;
    END
  END wbs_dat_i[23]
  PIN wbs_dat_i[24]
    DIRECTION INPUT ;
    USE SIGNAL ;
    ANTENNAGATEAREA 0.126000 ;
    PORT
      LAYER met2 ;
        RECT 497.350 0.000 497.630 4.000 ;
    END
  END wbs_dat_i[24]
  PIN wbs_dat_i[25]
    DIRECTION INPUT ;
    USE SIGNAL ;
    ANTENNAGATEAREA 0.126000 ;
    PORT
      LAYER met2 ;
        RECT 513.910 0.000 514.190 4.000 ;
    END
  END wbs_dat_i[25]
  PIN wbs_dat_i[26]
    DIRECTION INPUT ;
    USE SIGNAL ;
    ANTENNAGATEAREA 0.126000 ;
    PORT
      LAYER met2 ;
        RECT 530.470 0.000 530.750 4.000 ;
    END
  END wbs_dat_i[26]
  PIN wbs_dat_i[27]
    DIRECTION INPUT ;
    USE SIGNAL ;
    ANTENNAGATEAREA 0.126000 ;
    PORT
      LAYER met2 ;
        RECT 547.030 0.000 547.310 4.000 ;
    END
  END wbs_dat_i[27]
  PIN wbs_dat_i[28]
    DIRECTION INPUT ;
    USE SIGNAL ;
    ANTENNAGATEAREA 0.126000 ;
    PORT
      LAYER met2 ;
        RECT 563.590 0.000 563.870 4.000 ;
    END
  END wbs_dat_i[28]
  PIN wbs_dat_i[29]
    DIRECTION INPUT ;
    USE SIGNAL ;
    ANTENNAGATEAREA 0.126000 ;
    PORT
      LAYER met2 ;
        RECT 580.150 0.000 580.430 4.000 ;
    END
  END wbs_dat_i[29]
  PIN wbs_dat_i[2]
    DIRECTION INPUT ;
    USE SIGNAL ;
    ANTENNAGATEAREA 0.126000 ;
    PORT
      LAYER met2 ;
        RECT 121.990 0.000 122.270 4.000 ;
    END
  END wbs_dat_i[2]
  PIN wbs_dat_i[30]
    DIRECTION INPUT ;
    USE SIGNAL ;
    ANTENNAGATEAREA 0.126000 ;
    PORT
      LAYER met2 ;
        RECT 596.710 0.000 596.990 4.000 ;
    END
  END wbs_dat_i[30]
  PIN wbs_dat_i[31]
    DIRECTION INPUT ;
    USE SIGNAL ;
    ANTENNAGATEAREA 0.126000 ;
    PORT
      LAYER met2 ;
        RECT 613.270 0.000 613.550 4.000 ;
    END
  END wbs_dat_i[31]
  PIN wbs_dat_i[3]
    DIRECTION INPUT ;
    USE SIGNAL ;
    ANTENNAGATEAREA 0.126000 ;
    PORT
      LAYER met2 ;
        RECT 144.070 0.000 144.350 4.000 ;
    END
  END wbs_dat_i[3]
  PIN wbs_dat_i[4]
    DIRECTION INPUT ;
    USE SIGNAL ;
    ANTENNAGATEAREA 0.126000 ;
    PORT
      LAYER met2 ;
        RECT 166.150 0.000 166.430 4.000 ;
    END
  END wbs_dat_i[4]
  PIN wbs_dat_i[5]
    DIRECTION INPUT ;
    USE SIGNAL ;
    ANTENNAGATEAREA 0.126000 ;
    PORT
      LAYER met2 ;
        RECT 182.710 0.000 182.990 4.000 ;
    END
  END wbs_dat_i[5]
  PIN wbs_dat_i[6]
    DIRECTION INPUT ;
    USE SIGNAL ;
    ANTENNAGATEAREA 0.126000 ;
    PORT
      LAYER met2 ;
        RECT 199.270 0.000 199.550 4.000 ;
    END
  END wbs_dat_i[6]
  PIN wbs_dat_i[7]
    DIRECTION INPUT ;
    USE SIGNAL ;
    ANTENNAGATEAREA 0.126000 ;
    PORT
      LAYER met2 ;
        RECT 215.830 0.000 216.110 4.000 ;
    END
  END wbs_dat_i[7]
  PIN wbs_dat_i[8]
    DIRECTION INPUT ;
    USE SIGNAL ;
    ANTENNAGATEAREA 0.126000 ;
    PORT
      LAYER met2 ;
        RECT 232.390 0.000 232.670 4.000 ;
    END
  END wbs_dat_i[8]
  PIN wbs_dat_i[9]
    DIRECTION INPUT ;
    USE SIGNAL ;
    ANTENNAGATEAREA 0.126000 ;
    PORT
      LAYER met2 ;
        RECT 248.950 0.000 249.230 4.000 ;
    END
  END wbs_dat_i[9]
  PIN wbs_dat_o[0]
    DIRECTION OUTPUT TRISTATE ;
    USE SIGNAL ;
    ANTENNADIFFAREA 2.673000 ;
    PORT
      LAYER met2 ;
        RECT 83.350 0.000 83.630 4.000 ;
    END
  END wbs_dat_o[0]
  PIN wbs_dat_o[10]
    DIRECTION OUTPUT TRISTATE ;
    USE SIGNAL ;
    ANTENNADIFFAREA 2.673000 ;
    PORT
      LAYER met2 ;
        RECT 271.030 0.000 271.310 4.000 ;
    END
  END wbs_dat_o[10]
  PIN wbs_dat_o[11]
    DIRECTION OUTPUT TRISTATE ;
    USE SIGNAL ;
    ANTENNADIFFAREA 2.673000 ;
    PORT
      LAYER met2 ;
        RECT 287.590 0.000 287.870 4.000 ;
    END
  END wbs_dat_o[11]
  PIN wbs_dat_o[12]
    DIRECTION OUTPUT TRISTATE ;
    USE SIGNAL ;
    ANTENNADIFFAREA 2.673000 ;
    PORT
      LAYER met2 ;
        RECT 304.150 0.000 304.430 4.000 ;
    END
  END wbs_dat_o[12]
  PIN wbs_dat_o[13]
    DIRECTION OUTPUT TRISTATE ;
    USE SIGNAL ;
    ANTENNADIFFAREA 2.673000 ;
    PORT
      LAYER met2 ;
        RECT 320.710 0.000 320.990 4.000 ;
    END
  END wbs_dat_o[13]
  PIN wbs_dat_o[14]
    DIRECTION OUTPUT TRISTATE ;
    USE SIGNAL ;
    ANTENNADIFFAREA 2.673000 ;
    PORT
      LAYER met2 ;
        RECT 337.270 0.000 337.550 4.000 ;
    END
  END wbs_dat_o[14]
  PIN wbs_dat_o[15]
    DIRECTION OUTPUT TRISTATE ;
    USE SIGNAL ;
    ANTENNADIFFAREA 2.673000 ;
    PORT
      LAYER met2 ;
        RECT 353.830 0.000 354.110 4.000 ;
    END
  END wbs_dat_o[15]
  PIN wbs_dat_o[16]
    DIRECTION OUTPUT TRISTATE ;
    USE SIGNAL ;
    ANTENNADIFFAREA 2.673000 ;
    PORT
      LAYER met2 ;
        RECT 370.390 0.000 370.670 4.000 ;
    END
  END wbs_dat_o[16]
  PIN wbs_dat_o[17]
    DIRECTION OUTPUT TRISTATE ;
    USE SIGNAL ;
    ANTENNADIFFAREA 2.673000 ;
    PORT
      LAYER met2 ;
        RECT 386.950 0.000 387.230 4.000 ;
    END
  END wbs_dat_o[17]
  PIN wbs_dat_o[18]
    DIRECTION OUTPUT TRISTATE ;
    USE SIGNAL ;
    ANTENNADIFFAREA 2.673000 ;
    PORT
      LAYER met2 ;
        RECT 403.510 0.000 403.790 4.000 ;
    END
  END wbs_dat_o[18]
  PIN wbs_dat_o[19]
    DIRECTION OUTPUT TRISTATE ;
    USE SIGNAL ;
    ANTENNADIFFAREA 2.673000 ;
    PORT
      LAYER met2 ;
        RECT 420.070 0.000 420.350 4.000 ;
    END
  END wbs_dat_o[19]
  PIN wbs_dat_o[1]
    DIRECTION OUTPUT TRISTATE ;
    USE SIGNAL ;
    ANTENNADIFFAREA 2.673000 ;
    PORT
      LAYER met2 ;
        RECT 105.430 0.000 105.710 4.000 ;
    END
  END wbs_dat_o[1]
  PIN wbs_dat_o[20]
    DIRECTION OUTPUT TRISTATE ;
    USE SIGNAL ;
    ANTENNADIFFAREA 2.673000 ;
    PORT
      LAYER met2 ;
        RECT 436.630 0.000 436.910 4.000 ;
    END
  END wbs_dat_o[20]
  PIN wbs_dat_o[21]
    DIRECTION OUTPUT TRISTATE ;
    USE SIGNAL ;
    ANTENNADIFFAREA 2.673000 ;
    PORT
      LAYER met2 ;
        RECT 453.190 0.000 453.470 4.000 ;
    END
  END wbs_dat_o[21]
  PIN wbs_dat_o[22]
    DIRECTION OUTPUT TRISTATE ;
    USE SIGNAL ;
    ANTENNADIFFAREA 2.673000 ;
    PORT
      LAYER met2 ;
        RECT 469.750 0.000 470.030 4.000 ;
    END
  END wbs_dat_o[22]
  PIN wbs_dat_o[23]
    DIRECTION OUTPUT TRISTATE ;
    USE SIGNAL ;
    ANTENNADIFFAREA 2.673000 ;
    PORT
      LAYER met2 ;
        RECT 486.310 0.000 486.590 4.000 ;
    END
  END wbs_dat_o[23]
  PIN wbs_dat_o[24]
    DIRECTION OUTPUT TRISTATE ;
    USE SIGNAL ;
    ANTENNADIFFAREA 2.673000 ;
    PORT
      LAYER met2 ;
        RECT 502.870 0.000 503.150 4.000 ;
    END
  END wbs_dat_o[24]
  PIN wbs_dat_o[25]
    DIRECTION OUTPUT TRISTATE ;
    USE SIGNAL ;
    ANTENNADIFFAREA 2.673000 ;
    PORT
      LAYER met2 ;
        RECT 519.430 0.000 519.710 4.000 ;
    END
  END wbs_dat_o[25]
  PIN wbs_dat_o[26]
    DIRECTION OUTPUT TRISTATE ;
    USE SIGNAL ;
    ANTENNADIFFAREA 2.673000 ;
    PORT
      LAYER met2 ;
        RECT 535.990 0.000 536.270 4.000 ;
    END
  END wbs_dat_o[26]
  PIN wbs_dat_o[27]
    DIRECTION OUTPUT TRISTATE ;
    USE SIGNAL ;
    ANTENNADIFFAREA 2.673000 ;
    PORT
      LAYER met2 ;
        RECT 552.550 0.000 552.830 4.000 ;
    END
  END wbs_dat_o[27]
  PIN wbs_dat_o[28]
    DIRECTION OUTPUT TRISTATE ;
    USE SIGNAL ;
    ANTENNADIFFAREA 2.673000 ;
    PORT
      LAYER met2 ;
        RECT 569.110 0.000 569.390 4.000 ;
    END
  END wbs_dat_o[28]
  PIN wbs_dat_o[29]
    DIRECTION OUTPUT TRISTATE ;
    USE SIGNAL ;
    ANTENNADIFFAREA 2.673000 ;
    PORT
      LAYER met2 ;
        RECT 585.670 0.000 585.950 4.000 ;
    END
  END wbs_dat_o[29]
  PIN wbs_dat_o[2]
    DIRECTION OUTPUT TRISTATE ;
    USE SIGNAL ;
    ANTENNADIFFAREA 2.673000 ;
    PORT
      LAYER met2 ;
        RECT 127.510 0.000 127.790 4.000 ;
    END
  END wbs_dat_o[2]
  PIN wbs_dat_o[30]
    DIRECTION OUTPUT TRISTATE ;
    USE SIGNAL ;
    ANTENNADIFFAREA 2.673000 ;
    PORT
      LAYER met2 ;
        RECT 602.230 0.000 602.510 4.000 ;
    END
  END wbs_dat_o[30]
  PIN wbs_dat_o[31]
    DIRECTION OUTPUT TRISTATE ;
    USE SIGNAL ;
    ANTENNADIFFAREA 2.673000 ;
    PORT
      LAYER met2 ;
        RECT 618.790 0.000 619.070 4.000 ;
    END
  END wbs_dat_o[31]
  PIN wbs_dat_o[3]
    DIRECTION OUTPUT TRISTATE ;
    USE SIGNAL ;
    ANTENNADIFFAREA 2.673000 ;
    PORT
      LAYER met2 ;
        RECT 149.590 0.000 149.870 4.000 ;
    END
  END wbs_dat_o[3]
  PIN wbs_dat_o[4]
    DIRECTION OUTPUT TRISTATE ;
    USE SIGNAL ;
    ANTENNADIFFAREA 2.673000 ;
    PORT
      LAYER met2 ;
        RECT 171.670 0.000 171.950 4.000 ;
    END
  END wbs_dat_o[4]
  PIN wbs_dat_o[5]
    DIRECTION OUTPUT TRISTATE ;
    USE SIGNAL ;
    ANTENNADIFFAREA 2.673000 ;
    PORT
      LAYER met2 ;
        RECT 188.230 0.000 188.510 4.000 ;
    END
  END wbs_dat_o[5]
  PIN wbs_dat_o[6]
    DIRECTION OUTPUT TRISTATE ;
    USE SIGNAL ;
    ANTENNADIFFAREA 2.673000 ;
    PORT
      LAYER met2 ;
        RECT 204.790 0.000 205.070 4.000 ;
    END
  END wbs_dat_o[6]
  PIN wbs_dat_o[7]
    DIRECTION OUTPUT TRISTATE ;
    USE SIGNAL ;
    ANTENNADIFFAREA 2.673000 ;
    PORT
      LAYER met2 ;
        RECT 221.350 0.000 221.630 4.000 ;
    END
  END wbs_dat_o[7]
  PIN wbs_dat_o[8]
    DIRECTION OUTPUT TRISTATE ;
    USE SIGNAL ;
    ANTENNADIFFAREA 2.673000 ;
    PORT
      LAYER met2 ;
        RECT 237.910 0.000 238.190 4.000 ;
    END
  END wbs_dat_o[8]
  PIN wbs_dat_o[9]
    DIRECTION OUTPUT TRISTATE ;
    USE SIGNAL ;
    ANTENNADIFFAREA 2.673000 ;
    PORT
      LAYER met2 ;
        RECT 254.470 0.000 254.750 4.000 ;
    END
  END wbs_dat_o[9]
  PIN wbs_sel_i[0]
    DIRECTION INPUT ;
    USE SIGNAL ;
    PORT
      LAYER met2 ;
        RECT 88.870 0.000 89.150 4.000 ;
    END
  END wbs_sel_i[0]
  PIN wbs_sel_i[1]
    DIRECTION INPUT ;
    USE SIGNAL ;
    PORT
      LAYER met2 ;
        RECT 110.950 0.000 111.230 4.000 ;
    END
  END wbs_sel_i[1]
  PIN wbs_sel_i[2]
    DIRECTION INPUT ;
    USE SIGNAL ;
    PORT
      LAYER met2 ;
        RECT 133.030 0.000 133.310 4.000 ;
    END
  END wbs_sel_i[2]
  PIN wbs_sel_i[3]
    DIRECTION INPUT ;
    USE SIGNAL ;
    PORT
      LAYER met2 ;
        RECT 155.110 0.000 155.390 4.000 ;
    END
  END wbs_sel_i[3]
  PIN wbs_stb_i
    DIRECTION INPUT ;
    USE SIGNAL ;
    ANTENNAGATEAREA 0.196500 ;
    PORT
      LAYER met2 ;
        RECT 61.270 0.000 61.550 4.000 ;
    END
  END wbs_stb_i
  PIN wbs_we_i
    DIRECTION INPUT ;
    USE SIGNAL ;
    ANTENNAGATEAREA 0.126000 ;
    PORT
      LAYER met2 ;
        RECT 66.790 0.000 67.070 4.000 ;
    END
  END wbs_we_i
  OBS
      LAYER li1 ;
        RECT 5.520 10.795 2794.040 1749.045 ;
      LAYER met1 ;
        RECT 4.670 7.520 2794.040 1749.200 ;
      LAYER met2 ;
        RECT 4.690 1755.720 38.910 1756.000 ;
        RECT 39.750 1755.720 116.650 1756.000 ;
        RECT 117.490 1755.720 194.390 1756.000 ;
        RECT 195.230 1755.720 272.130 1756.000 ;
        RECT 272.970 1755.720 349.870 1756.000 ;
        RECT 350.710 1755.720 427.610 1756.000 ;
        RECT 428.450 1755.720 505.350 1756.000 ;
        RECT 506.190 1755.720 583.090 1756.000 ;
        RECT 583.930 1755.720 660.830 1756.000 ;
        RECT 661.670 1755.720 738.570 1756.000 ;
        RECT 739.410 1755.720 816.310 1756.000 ;
        RECT 817.150 1755.720 894.050 1756.000 ;
        RECT 894.890 1755.720 971.790 1756.000 ;
        RECT 972.630 1755.720 1049.530 1756.000 ;
        RECT 1050.370 1755.720 1127.270 1756.000 ;
        RECT 1128.110 1755.720 1205.010 1756.000 ;
        RECT 1205.850 1755.720 1282.750 1756.000 ;
        RECT 1283.590 1755.720 1360.490 1756.000 ;
        RECT 1361.330 1755.720 1438.230 1756.000 ;
        RECT 1439.070 1755.720 1515.970 1756.000 ;
        RECT 1516.810 1755.720 1593.710 1756.000 ;
        RECT 1594.550 1755.720 1671.450 1756.000 ;
        RECT 1672.290 1755.720 1749.190 1756.000 ;
        RECT 1750.030 1755.720 1826.930 1756.000 ;
        RECT 1827.770 1755.720 1904.670 1756.000 ;
        RECT 1905.510 1755.720 1982.410 1756.000 ;
        RECT 1983.250 1755.720 2060.150 1756.000 ;
        RECT 2060.990 1755.720 2137.890 1756.000 ;
        RECT 2138.730 1755.720 2215.630 1756.000 ;
        RECT 2216.470 1755.720 2293.370 1756.000 ;
        RECT 2294.210 1755.720 2371.110 1756.000 ;
        RECT 2371.950 1755.720 2448.850 1756.000 ;
        RECT 2449.690 1755.720 2526.590 1756.000 ;
        RECT 2527.430 1755.720 2604.330 1756.000 ;
        RECT 2605.170 1755.720 2682.070 1756.000 ;
        RECT 2682.910 1755.720 2759.810 1756.000 ;
        RECT 2760.650 1755.720 2792.570 1756.000 ;
        RECT 4.690 4.280 2792.570 1755.720 ;
        RECT 4.690 3.670 38.910 4.280 ;
        RECT 39.750 3.670 44.430 4.280 ;
        RECT 45.270 3.670 49.950 4.280 ;
        RECT 50.790 3.670 55.470 4.280 ;
        RECT 56.310 3.670 60.990 4.280 ;
        RECT 61.830 3.670 66.510 4.280 ;
        RECT 67.350 3.670 72.030 4.280 ;
        RECT 72.870 3.670 77.550 4.280 ;
        RECT 78.390 3.670 83.070 4.280 ;
        RECT 83.910 3.670 88.590 4.280 ;
        RECT 89.430 3.670 94.110 4.280 ;
        RECT 94.950 3.670 99.630 4.280 ;
        RECT 100.470 3.670 105.150 4.280 ;
        RECT 105.990 3.670 110.670 4.280 ;
        RECT 111.510 3.670 116.190 4.280 ;
        RECT 117.030 3.670 121.710 4.280 ;
        RECT 122.550 3.670 127.230 4.280 ;
        RECT 128.070 3.670 132.750 4.280 ;
        RECT 133.590 3.670 138.270 4.280 ;
        RECT 139.110 3.670 143.790 4.280 ;
        RECT 144.630 3.670 149.310 4.280 ;
        RECT 150.150 3.670 154.830 4.280 ;
        RECT 155.670 3.670 160.350 4.280 ;
        RECT 161.190 3.670 165.870 4.280 ;
        RECT 166.710 3.670 171.390 4.280 ;
        RECT 172.230 3.670 176.910 4.280 ;
        RECT 177.750 3.670 182.430 4.280 ;
        RECT 183.270 3.670 187.950 4.280 ;
        RECT 188.790 3.670 193.470 4.280 ;
        RECT 194.310 3.670 198.990 4.280 ;
        RECT 199.830 3.670 204.510 4.280 ;
        RECT 205.350 3.670 210.030 4.280 ;
        RECT 210.870 3.670 215.550 4.280 ;
        RECT 216.390 3.670 221.070 4.280 ;
        RECT 221.910 3.670 226.590 4.280 ;
        RECT 227.430 3.670 232.110 4.280 ;
        RECT 232.950 3.670 237.630 4.280 ;
        RECT 238.470 3.670 243.150 4.280 ;
        RECT 243.990 3.670 248.670 4.280 ;
        RECT 249.510 3.670 254.190 4.280 ;
        RECT 255.030 3.670 259.710 4.280 ;
        RECT 260.550 3.670 265.230 4.280 ;
        RECT 266.070 3.670 270.750 4.280 ;
        RECT 271.590 3.670 276.270 4.280 ;
        RECT 277.110 3.670 281.790 4.280 ;
        RECT 282.630 3.670 287.310 4.280 ;
        RECT 288.150 3.670 292.830 4.280 ;
        RECT 293.670 3.670 298.350 4.280 ;
        RECT 299.190 3.670 303.870 4.280 ;
        RECT 304.710 3.670 309.390 4.280 ;
        RECT 310.230 3.670 314.910 4.280 ;
        RECT 315.750 3.670 320.430 4.280 ;
        RECT 321.270 3.670 325.950 4.280 ;
        RECT 326.790 3.670 331.470 4.280 ;
        RECT 332.310 3.670 336.990 4.280 ;
        RECT 337.830 3.670 342.510 4.280 ;
        RECT 343.350 3.670 348.030 4.280 ;
        RECT 348.870 3.670 353.550 4.280 ;
        RECT 354.390 3.670 359.070 4.280 ;
        RECT 359.910 3.670 364.590 4.280 ;
        RECT 365.430 3.670 370.110 4.280 ;
        RECT 370.950 3.670 375.630 4.280 ;
        RECT 376.470 3.670 381.150 4.280 ;
        RECT 381.990 3.670 386.670 4.280 ;
        RECT 387.510 3.670 392.190 4.280 ;
        RECT 393.030 3.670 397.710 4.280 ;
        RECT 398.550 3.670 403.230 4.280 ;
        RECT 404.070 3.670 408.750 4.280 ;
        RECT 409.590 3.670 414.270 4.280 ;
        RECT 415.110 3.670 419.790 4.280 ;
        RECT 420.630 3.670 425.310 4.280 ;
        RECT 426.150 3.670 430.830 4.280 ;
        RECT 431.670 3.670 436.350 4.280 ;
        RECT 437.190 3.670 441.870 4.280 ;
        RECT 442.710 3.670 447.390 4.280 ;
        RECT 448.230 3.670 452.910 4.280 ;
        RECT 453.750 3.670 458.430 4.280 ;
        RECT 459.270 3.670 463.950 4.280 ;
        RECT 464.790 3.670 469.470 4.280 ;
        RECT 470.310 3.670 474.990 4.280 ;
        RECT 475.830 3.670 480.510 4.280 ;
        RECT 481.350 3.670 486.030 4.280 ;
        RECT 486.870 3.670 491.550 4.280 ;
        RECT 492.390 3.670 497.070 4.280 ;
        RECT 497.910 3.670 502.590 4.280 ;
        RECT 503.430 3.670 508.110 4.280 ;
        RECT 508.950 3.670 513.630 4.280 ;
        RECT 514.470 3.670 519.150 4.280 ;
        RECT 519.990 3.670 524.670 4.280 ;
        RECT 525.510 3.670 530.190 4.280 ;
        RECT 531.030 3.670 535.710 4.280 ;
        RECT 536.550 3.670 541.230 4.280 ;
        RECT 542.070 3.670 546.750 4.280 ;
        RECT 547.590 3.670 552.270 4.280 ;
        RECT 553.110 3.670 557.790 4.280 ;
        RECT 558.630 3.670 563.310 4.280 ;
        RECT 564.150 3.670 568.830 4.280 ;
        RECT 569.670 3.670 574.350 4.280 ;
        RECT 575.190 3.670 579.870 4.280 ;
        RECT 580.710 3.670 585.390 4.280 ;
        RECT 586.230 3.670 590.910 4.280 ;
        RECT 591.750 3.670 596.430 4.280 ;
        RECT 597.270 3.670 601.950 4.280 ;
        RECT 602.790 3.670 607.470 4.280 ;
        RECT 608.310 3.670 612.990 4.280 ;
        RECT 613.830 3.670 618.510 4.280 ;
        RECT 619.350 3.670 624.030 4.280 ;
        RECT 624.870 3.670 629.550 4.280 ;
        RECT 630.390 3.670 635.070 4.280 ;
        RECT 635.910 3.670 640.590 4.280 ;
        RECT 641.430 3.670 646.110 4.280 ;
        RECT 646.950 3.670 651.630 4.280 ;
        RECT 652.470 3.670 657.150 4.280 ;
        RECT 657.990 3.670 662.670 4.280 ;
        RECT 663.510 3.670 668.190 4.280 ;
        RECT 669.030 3.670 673.710 4.280 ;
        RECT 674.550 3.670 679.230 4.280 ;
        RECT 680.070 3.670 684.750 4.280 ;
        RECT 685.590 3.670 690.270 4.280 ;
        RECT 691.110 3.670 695.790 4.280 ;
        RECT 696.630 3.670 701.310 4.280 ;
        RECT 702.150 3.670 706.830 4.280 ;
        RECT 707.670 3.670 712.350 4.280 ;
        RECT 713.190 3.670 717.870 4.280 ;
        RECT 718.710 3.670 723.390 4.280 ;
        RECT 724.230 3.670 728.910 4.280 ;
        RECT 729.750 3.670 734.430 4.280 ;
        RECT 735.270 3.670 739.950 4.280 ;
        RECT 740.790 3.670 745.470 4.280 ;
        RECT 746.310 3.670 750.990 4.280 ;
        RECT 751.830 3.670 756.510 4.280 ;
        RECT 757.350 3.670 762.030 4.280 ;
        RECT 762.870 3.670 767.550 4.280 ;
        RECT 768.390 3.670 773.070 4.280 ;
        RECT 773.910 3.670 778.590 4.280 ;
        RECT 779.430 3.670 784.110 4.280 ;
        RECT 784.950 3.670 789.630 4.280 ;
        RECT 790.470 3.670 795.150 4.280 ;
        RECT 795.990 3.670 800.670 4.280 ;
        RECT 801.510 3.670 806.190 4.280 ;
        RECT 807.030 3.670 811.710 4.280 ;
        RECT 812.550 3.670 817.230 4.280 ;
        RECT 818.070 3.670 822.750 4.280 ;
        RECT 823.590 3.670 828.270 4.280 ;
        RECT 829.110 3.670 833.790 4.280 ;
        RECT 834.630 3.670 839.310 4.280 ;
        RECT 840.150 3.670 844.830 4.280 ;
        RECT 845.670 3.670 850.350 4.280 ;
        RECT 851.190 3.670 855.870 4.280 ;
        RECT 856.710 3.670 861.390 4.280 ;
        RECT 862.230 3.670 866.910 4.280 ;
        RECT 867.750 3.670 872.430 4.280 ;
        RECT 873.270 3.670 877.950 4.280 ;
        RECT 878.790 3.670 883.470 4.280 ;
        RECT 884.310 3.670 888.990 4.280 ;
        RECT 889.830 3.670 894.510 4.280 ;
        RECT 895.350 3.670 900.030 4.280 ;
        RECT 900.870 3.670 905.550 4.280 ;
        RECT 906.390 3.670 911.070 4.280 ;
        RECT 911.910 3.670 916.590 4.280 ;
        RECT 917.430 3.670 922.110 4.280 ;
        RECT 922.950 3.670 927.630 4.280 ;
        RECT 928.470 3.670 933.150 4.280 ;
        RECT 933.990 3.670 938.670 4.280 ;
        RECT 939.510 3.670 944.190 4.280 ;
        RECT 945.030 3.670 949.710 4.280 ;
        RECT 950.550 3.670 955.230 4.280 ;
        RECT 956.070 3.670 960.750 4.280 ;
        RECT 961.590 3.670 966.270 4.280 ;
        RECT 967.110 3.670 971.790 4.280 ;
        RECT 972.630 3.670 977.310 4.280 ;
        RECT 978.150 3.670 982.830 4.280 ;
        RECT 983.670 3.670 988.350 4.280 ;
        RECT 989.190 3.670 993.870 4.280 ;
        RECT 994.710 3.670 999.390 4.280 ;
        RECT 1000.230 3.670 1004.910 4.280 ;
        RECT 1005.750 3.670 1010.430 4.280 ;
        RECT 1011.270 3.670 1015.950 4.280 ;
        RECT 1016.790 3.670 1021.470 4.280 ;
        RECT 1022.310 3.670 1026.990 4.280 ;
        RECT 1027.830 3.670 1032.510 4.280 ;
        RECT 1033.350 3.670 1038.030 4.280 ;
        RECT 1038.870 3.670 1043.550 4.280 ;
        RECT 1044.390 3.670 1049.070 4.280 ;
        RECT 1049.910 3.670 1054.590 4.280 ;
        RECT 1055.430 3.670 1060.110 4.280 ;
        RECT 1060.950 3.670 1065.630 4.280 ;
        RECT 1066.470 3.670 1071.150 4.280 ;
        RECT 1071.990 3.670 1076.670 4.280 ;
        RECT 1077.510 3.670 1082.190 4.280 ;
        RECT 1083.030 3.670 1087.710 4.280 ;
        RECT 1088.550 3.670 1093.230 4.280 ;
        RECT 1094.070 3.670 1098.750 4.280 ;
        RECT 1099.590 3.670 1104.270 4.280 ;
        RECT 1105.110 3.670 1109.790 4.280 ;
        RECT 1110.630 3.670 1115.310 4.280 ;
        RECT 1116.150 3.670 1120.830 4.280 ;
        RECT 1121.670 3.670 1126.350 4.280 ;
        RECT 1127.190 3.670 1131.870 4.280 ;
        RECT 1132.710 3.670 1137.390 4.280 ;
        RECT 1138.230 3.670 1142.910 4.280 ;
        RECT 1143.750 3.670 1148.430 4.280 ;
        RECT 1149.270 3.670 1153.950 4.280 ;
        RECT 1154.790 3.670 1159.470 4.280 ;
        RECT 1160.310 3.670 1164.990 4.280 ;
        RECT 1165.830 3.670 1170.510 4.280 ;
        RECT 1171.350 3.670 1176.030 4.280 ;
        RECT 1176.870 3.670 1181.550 4.280 ;
        RECT 1182.390 3.670 1187.070 4.280 ;
        RECT 1187.910 3.670 1192.590 4.280 ;
        RECT 1193.430 3.670 1198.110 4.280 ;
        RECT 1198.950 3.670 1203.630 4.280 ;
        RECT 1204.470 3.670 1209.150 4.280 ;
        RECT 1209.990 3.670 1214.670 4.280 ;
        RECT 1215.510 3.670 1220.190 4.280 ;
        RECT 1221.030 3.670 1225.710 4.280 ;
        RECT 1226.550 3.670 1231.230 4.280 ;
        RECT 1232.070 3.670 1236.750 4.280 ;
        RECT 1237.590 3.670 1242.270 4.280 ;
        RECT 1243.110 3.670 1247.790 4.280 ;
        RECT 1248.630 3.670 1253.310 4.280 ;
        RECT 1254.150 3.670 1258.830 4.280 ;
        RECT 1259.670 3.670 1264.350 4.280 ;
        RECT 1265.190 3.670 1269.870 4.280 ;
        RECT 1270.710 3.670 1275.390 4.280 ;
        RECT 1276.230 3.670 1280.910 4.280 ;
        RECT 1281.750 3.670 1286.430 4.280 ;
        RECT 1287.270 3.670 1291.950 4.280 ;
        RECT 1292.790 3.670 1297.470 4.280 ;
        RECT 1298.310 3.670 1302.990 4.280 ;
        RECT 1303.830 3.670 1308.510 4.280 ;
        RECT 1309.350 3.670 1314.030 4.280 ;
        RECT 1314.870 3.670 1319.550 4.280 ;
        RECT 1320.390 3.670 1325.070 4.280 ;
        RECT 1325.910 3.670 1330.590 4.280 ;
        RECT 1331.430 3.670 1336.110 4.280 ;
        RECT 1336.950 3.670 1341.630 4.280 ;
        RECT 1342.470 3.670 1347.150 4.280 ;
        RECT 1347.990 3.670 1352.670 4.280 ;
        RECT 1353.510 3.670 1358.190 4.280 ;
        RECT 1359.030 3.670 1363.710 4.280 ;
        RECT 1364.550 3.670 1369.230 4.280 ;
        RECT 1370.070 3.670 1374.750 4.280 ;
        RECT 1375.590 3.670 1380.270 4.280 ;
        RECT 1381.110 3.670 1385.790 4.280 ;
        RECT 1386.630 3.670 1391.310 4.280 ;
        RECT 1392.150 3.670 1396.830 4.280 ;
        RECT 1397.670 3.670 1402.350 4.280 ;
        RECT 1403.190 3.670 1407.870 4.280 ;
        RECT 1408.710 3.670 1413.390 4.280 ;
        RECT 1414.230 3.670 1418.910 4.280 ;
        RECT 1419.750 3.670 1424.430 4.280 ;
        RECT 1425.270 3.670 1429.950 4.280 ;
        RECT 1430.790 3.670 1435.470 4.280 ;
        RECT 1436.310 3.670 1440.990 4.280 ;
        RECT 1441.830 3.670 1446.510 4.280 ;
        RECT 1447.350 3.670 1452.030 4.280 ;
        RECT 1452.870 3.670 1457.550 4.280 ;
        RECT 1458.390 3.670 1463.070 4.280 ;
        RECT 1463.910 3.670 1468.590 4.280 ;
        RECT 1469.430 3.670 1474.110 4.280 ;
        RECT 1474.950 3.670 1479.630 4.280 ;
        RECT 1480.470 3.670 1485.150 4.280 ;
        RECT 1485.990 3.670 1490.670 4.280 ;
        RECT 1491.510 3.670 1496.190 4.280 ;
        RECT 1497.030 3.670 1501.710 4.280 ;
        RECT 1502.550 3.670 1507.230 4.280 ;
        RECT 1508.070 3.670 1512.750 4.280 ;
        RECT 1513.590 3.670 1518.270 4.280 ;
        RECT 1519.110 3.670 1523.790 4.280 ;
        RECT 1524.630 3.670 1529.310 4.280 ;
        RECT 1530.150 3.670 1534.830 4.280 ;
        RECT 1535.670 3.670 1540.350 4.280 ;
        RECT 1541.190 3.670 1545.870 4.280 ;
        RECT 1546.710 3.670 1551.390 4.280 ;
        RECT 1552.230 3.670 1556.910 4.280 ;
        RECT 1557.750 3.670 1562.430 4.280 ;
        RECT 1563.270 3.670 1567.950 4.280 ;
        RECT 1568.790 3.670 1573.470 4.280 ;
        RECT 1574.310 3.670 1578.990 4.280 ;
        RECT 1579.830 3.670 1584.510 4.280 ;
        RECT 1585.350 3.670 1590.030 4.280 ;
        RECT 1590.870 3.670 1595.550 4.280 ;
        RECT 1596.390 3.670 1601.070 4.280 ;
        RECT 1601.910 3.670 1606.590 4.280 ;
        RECT 1607.430 3.670 1612.110 4.280 ;
        RECT 1612.950 3.670 1617.630 4.280 ;
        RECT 1618.470 3.670 1623.150 4.280 ;
        RECT 1623.990 3.670 1628.670 4.280 ;
        RECT 1629.510 3.670 1634.190 4.280 ;
        RECT 1635.030 3.670 1639.710 4.280 ;
        RECT 1640.550 3.670 1645.230 4.280 ;
        RECT 1646.070 3.670 1650.750 4.280 ;
        RECT 1651.590 3.670 1656.270 4.280 ;
        RECT 1657.110 3.670 1661.790 4.280 ;
        RECT 1662.630 3.670 1667.310 4.280 ;
        RECT 1668.150 3.670 1672.830 4.280 ;
        RECT 1673.670 3.670 1678.350 4.280 ;
        RECT 1679.190 3.670 1683.870 4.280 ;
        RECT 1684.710 3.670 1689.390 4.280 ;
        RECT 1690.230 3.670 1694.910 4.280 ;
        RECT 1695.750 3.670 1700.430 4.280 ;
        RECT 1701.270 3.670 1705.950 4.280 ;
        RECT 1706.790 3.670 1711.470 4.280 ;
        RECT 1712.310 3.670 1716.990 4.280 ;
        RECT 1717.830 3.670 1722.510 4.280 ;
        RECT 1723.350 3.670 1728.030 4.280 ;
        RECT 1728.870 3.670 1733.550 4.280 ;
        RECT 1734.390 3.670 1739.070 4.280 ;
        RECT 1739.910 3.670 1744.590 4.280 ;
        RECT 1745.430 3.670 1750.110 4.280 ;
        RECT 1750.950 3.670 1755.630 4.280 ;
        RECT 1756.470 3.670 1761.150 4.280 ;
        RECT 1761.990 3.670 1766.670 4.280 ;
        RECT 1767.510 3.670 1772.190 4.280 ;
        RECT 1773.030 3.670 1777.710 4.280 ;
        RECT 1778.550 3.670 1783.230 4.280 ;
        RECT 1784.070 3.670 1788.750 4.280 ;
        RECT 1789.590 3.670 1794.270 4.280 ;
        RECT 1795.110 3.670 1799.790 4.280 ;
        RECT 1800.630 3.670 1805.310 4.280 ;
        RECT 1806.150 3.670 1810.830 4.280 ;
        RECT 1811.670 3.670 1816.350 4.280 ;
        RECT 1817.190 3.670 1821.870 4.280 ;
        RECT 1822.710 3.670 1827.390 4.280 ;
        RECT 1828.230 3.670 1832.910 4.280 ;
        RECT 1833.750 3.670 1838.430 4.280 ;
        RECT 1839.270 3.670 1843.950 4.280 ;
        RECT 1844.790 3.670 1849.470 4.280 ;
        RECT 1850.310 3.670 1854.990 4.280 ;
        RECT 1855.830 3.670 1860.510 4.280 ;
        RECT 1861.350 3.670 1866.030 4.280 ;
        RECT 1866.870 3.670 1871.550 4.280 ;
        RECT 1872.390 3.670 1877.070 4.280 ;
        RECT 1877.910 3.670 1882.590 4.280 ;
        RECT 1883.430 3.670 1888.110 4.280 ;
        RECT 1888.950 3.670 1893.630 4.280 ;
        RECT 1894.470 3.670 1899.150 4.280 ;
        RECT 1899.990 3.670 1904.670 4.280 ;
        RECT 1905.510 3.670 1910.190 4.280 ;
        RECT 1911.030 3.670 1915.710 4.280 ;
        RECT 1916.550 3.670 1921.230 4.280 ;
        RECT 1922.070 3.670 1926.750 4.280 ;
        RECT 1927.590 3.670 1932.270 4.280 ;
        RECT 1933.110 3.670 1937.790 4.280 ;
        RECT 1938.630 3.670 1943.310 4.280 ;
        RECT 1944.150 3.670 1948.830 4.280 ;
        RECT 1949.670 3.670 1954.350 4.280 ;
        RECT 1955.190 3.670 1959.870 4.280 ;
        RECT 1960.710 3.670 1965.390 4.280 ;
        RECT 1966.230 3.670 1970.910 4.280 ;
        RECT 1971.750 3.670 1976.430 4.280 ;
        RECT 1977.270 3.670 1981.950 4.280 ;
        RECT 1982.790 3.670 1987.470 4.280 ;
        RECT 1988.310 3.670 1992.990 4.280 ;
        RECT 1993.830 3.670 1998.510 4.280 ;
        RECT 1999.350 3.670 2004.030 4.280 ;
        RECT 2004.870 3.670 2009.550 4.280 ;
        RECT 2010.390 3.670 2015.070 4.280 ;
        RECT 2015.910 3.670 2020.590 4.280 ;
        RECT 2021.430 3.670 2026.110 4.280 ;
        RECT 2026.950 3.670 2031.630 4.280 ;
        RECT 2032.470 3.670 2037.150 4.280 ;
        RECT 2037.990 3.670 2042.670 4.280 ;
        RECT 2043.510 3.670 2048.190 4.280 ;
        RECT 2049.030 3.670 2053.710 4.280 ;
        RECT 2054.550 3.670 2059.230 4.280 ;
        RECT 2060.070 3.670 2064.750 4.280 ;
        RECT 2065.590 3.670 2070.270 4.280 ;
        RECT 2071.110 3.670 2075.790 4.280 ;
        RECT 2076.630 3.670 2081.310 4.280 ;
        RECT 2082.150 3.670 2086.830 4.280 ;
        RECT 2087.670 3.670 2092.350 4.280 ;
        RECT 2093.190 3.670 2097.870 4.280 ;
        RECT 2098.710 3.670 2103.390 4.280 ;
        RECT 2104.230 3.670 2108.910 4.280 ;
        RECT 2109.750 3.670 2114.430 4.280 ;
        RECT 2115.270 3.670 2119.950 4.280 ;
        RECT 2120.790 3.670 2125.470 4.280 ;
        RECT 2126.310 3.670 2130.990 4.280 ;
        RECT 2131.830 3.670 2136.510 4.280 ;
        RECT 2137.350 3.670 2142.030 4.280 ;
        RECT 2142.870 3.670 2147.550 4.280 ;
        RECT 2148.390 3.670 2153.070 4.280 ;
        RECT 2153.910 3.670 2158.590 4.280 ;
        RECT 2159.430 3.670 2164.110 4.280 ;
        RECT 2164.950 3.670 2169.630 4.280 ;
        RECT 2170.470 3.670 2175.150 4.280 ;
        RECT 2175.990 3.670 2180.670 4.280 ;
        RECT 2181.510 3.670 2186.190 4.280 ;
        RECT 2187.030 3.670 2191.710 4.280 ;
        RECT 2192.550 3.670 2197.230 4.280 ;
        RECT 2198.070 3.670 2202.750 4.280 ;
        RECT 2203.590 3.670 2208.270 4.280 ;
        RECT 2209.110 3.670 2213.790 4.280 ;
        RECT 2214.630 3.670 2219.310 4.280 ;
        RECT 2220.150 3.670 2224.830 4.280 ;
        RECT 2225.670 3.670 2230.350 4.280 ;
        RECT 2231.190 3.670 2235.870 4.280 ;
        RECT 2236.710 3.670 2241.390 4.280 ;
        RECT 2242.230 3.670 2246.910 4.280 ;
        RECT 2247.750 3.670 2252.430 4.280 ;
        RECT 2253.270 3.670 2257.950 4.280 ;
        RECT 2258.790 3.670 2263.470 4.280 ;
        RECT 2264.310 3.670 2268.990 4.280 ;
        RECT 2269.830 3.670 2274.510 4.280 ;
        RECT 2275.350 3.670 2280.030 4.280 ;
        RECT 2280.870 3.670 2285.550 4.280 ;
        RECT 2286.390 3.670 2291.070 4.280 ;
        RECT 2291.910 3.670 2296.590 4.280 ;
        RECT 2297.430 3.670 2302.110 4.280 ;
        RECT 2302.950 3.670 2307.630 4.280 ;
        RECT 2308.470 3.670 2313.150 4.280 ;
        RECT 2313.990 3.670 2318.670 4.280 ;
        RECT 2319.510 3.670 2324.190 4.280 ;
        RECT 2325.030 3.670 2329.710 4.280 ;
        RECT 2330.550 3.670 2335.230 4.280 ;
        RECT 2336.070 3.670 2340.750 4.280 ;
        RECT 2341.590 3.670 2346.270 4.280 ;
        RECT 2347.110 3.670 2351.790 4.280 ;
        RECT 2352.630 3.670 2357.310 4.280 ;
        RECT 2358.150 3.670 2362.830 4.280 ;
        RECT 2363.670 3.670 2368.350 4.280 ;
        RECT 2369.190 3.670 2373.870 4.280 ;
        RECT 2374.710 3.670 2379.390 4.280 ;
        RECT 2380.230 3.670 2384.910 4.280 ;
        RECT 2385.750 3.670 2390.430 4.280 ;
        RECT 2391.270 3.670 2395.950 4.280 ;
        RECT 2396.790 3.670 2401.470 4.280 ;
        RECT 2402.310 3.670 2406.990 4.280 ;
        RECT 2407.830 3.670 2412.510 4.280 ;
        RECT 2413.350 3.670 2418.030 4.280 ;
        RECT 2418.870 3.670 2423.550 4.280 ;
        RECT 2424.390 3.670 2429.070 4.280 ;
        RECT 2429.910 3.670 2434.590 4.280 ;
        RECT 2435.430 3.670 2440.110 4.280 ;
        RECT 2440.950 3.670 2445.630 4.280 ;
        RECT 2446.470 3.670 2451.150 4.280 ;
        RECT 2451.990 3.670 2456.670 4.280 ;
        RECT 2457.510 3.670 2462.190 4.280 ;
        RECT 2463.030 3.670 2467.710 4.280 ;
        RECT 2468.550 3.670 2473.230 4.280 ;
        RECT 2474.070 3.670 2478.750 4.280 ;
        RECT 2479.590 3.670 2484.270 4.280 ;
        RECT 2485.110 3.670 2489.790 4.280 ;
        RECT 2490.630 3.670 2495.310 4.280 ;
        RECT 2496.150 3.670 2500.830 4.280 ;
        RECT 2501.670 3.670 2506.350 4.280 ;
        RECT 2507.190 3.670 2511.870 4.280 ;
        RECT 2512.710 3.670 2517.390 4.280 ;
        RECT 2518.230 3.670 2522.910 4.280 ;
        RECT 2523.750 3.670 2528.430 4.280 ;
        RECT 2529.270 3.670 2533.950 4.280 ;
        RECT 2534.790 3.670 2539.470 4.280 ;
        RECT 2540.310 3.670 2544.990 4.280 ;
        RECT 2545.830 3.670 2550.510 4.280 ;
        RECT 2551.350 3.670 2556.030 4.280 ;
        RECT 2556.870 3.670 2561.550 4.280 ;
        RECT 2562.390 3.670 2567.070 4.280 ;
        RECT 2567.910 3.670 2572.590 4.280 ;
        RECT 2573.430 3.670 2578.110 4.280 ;
        RECT 2578.950 3.670 2583.630 4.280 ;
        RECT 2584.470 3.670 2589.150 4.280 ;
        RECT 2589.990 3.670 2594.670 4.280 ;
        RECT 2595.510 3.670 2600.190 4.280 ;
        RECT 2601.030 3.670 2605.710 4.280 ;
        RECT 2606.550 3.670 2611.230 4.280 ;
        RECT 2612.070 3.670 2616.750 4.280 ;
        RECT 2617.590 3.670 2622.270 4.280 ;
        RECT 2623.110 3.670 2627.790 4.280 ;
        RECT 2628.630 3.670 2633.310 4.280 ;
        RECT 2634.150 3.670 2638.830 4.280 ;
        RECT 2639.670 3.670 2644.350 4.280 ;
        RECT 2645.190 3.670 2649.870 4.280 ;
        RECT 2650.710 3.670 2655.390 4.280 ;
        RECT 2656.230 3.670 2660.910 4.280 ;
        RECT 2661.750 3.670 2666.430 4.280 ;
        RECT 2667.270 3.670 2671.950 4.280 ;
        RECT 2672.790 3.670 2677.470 4.280 ;
        RECT 2678.310 3.670 2682.990 4.280 ;
        RECT 2683.830 3.670 2688.510 4.280 ;
        RECT 2689.350 3.670 2694.030 4.280 ;
        RECT 2694.870 3.670 2699.550 4.280 ;
        RECT 2700.390 3.670 2705.070 4.280 ;
        RECT 2705.910 3.670 2710.590 4.280 ;
        RECT 2711.430 3.670 2716.110 4.280 ;
        RECT 2716.950 3.670 2721.630 4.280 ;
        RECT 2722.470 3.670 2727.150 4.280 ;
        RECT 2727.990 3.670 2732.670 4.280 ;
        RECT 2733.510 3.670 2738.190 4.280 ;
        RECT 2739.030 3.670 2743.710 4.280 ;
        RECT 2744.550 3.670 2749.230 4.280 ;
        RECT 2750.070 3.670 2754.750 4.280 ;
        RECT 2755.590 3.670 2760.270 4.280 ;
        RECT 2761.110 3.670 2792.570 4.280 ;
      LAYER met3 ;
        RECT 3.990 1728.240 2796.000 1749.125 ;
        RECT 4.400 1726.840 2795.600 1728.240 ;
        RECT 3.990 1695.600 2796.000 1726.840 ;
        RECT 3.990 1694.200 2795.600 1695.600 ;
        RECT 3.990 1688.800 2796.000 1694.200 ;
        RECT 4.400 1687.400 2796.000 1688.800 ;
        RECT 3.990 1662.960 2796.000 1687.400 ;
        RECT 3.990 1661.560 2795.600 1662.960 ;
        RECT 3.990 1649.360 2796.000 1661.560 ;
        RECT 4.400 1647.960 2796.000 1649.360 ;
        RECT 3.990 1630.320 2796.000 1647.960 ;
        RECT 3.990 1628.920 2795.600 1630.320 ;
        RECT 3.990 1609.920 2796.000 1628.920 ;
        RECT 4.400 1608.520 2796.000 1609.920 ;
        RECT 3.990 1597.680 2796.000 1608.520 ;
        RECT 3.990 1596.280 2795.600 1597.680 ;
        RECT 3.990 1570.480 2796.000 1596.280 ;
        RECT 4.400 1569.080 2796.000 1570.480 ;
        RECT 3.990 1565.040 2796.000 1569.080 ;
        RECT 3.990 1563.640 2795.600 1565.040 ;
        RECT 3.990 1532.400 2796.000 1563.640 ;
        RECT 3.990 1531.040 2795.600 1532.400 ;
        RECT 4.400 1531.000 2795.600 1531.040 ;
        RECT 4.400 1529.640 2796.000 1531.000 ;
        RECT 3.990 1499.760 2796.000 1529.640 ;
        RECT 3.990 1498.360 2795.600 1499.760 ;
        RECT 3.990 1491.600 2796.000 1498.360 ;
        RECT 4.400 1490.200 2796.000 1491.600 ;
        RECT 3.990 1467.120 2796.000 1490.200 ;
        RECT 3.990 1465.720 2795.600 1467.120 ;
        RECT 3.990 1452.160 2796.000 1465.720 ;
        RECT 4.400 1450.760 2796.000 1452.160 ;
        RECT 3.990 1434.480 2796.000 1450.760 ;
        RECT 3.990 1433.080 2795.600 1434.480 ;
        RECT 3.990 1412.720 2796.000 1433.080 ;
        RECT 4.400 1411.320 2796.000 1412.720 ;
        RECT 3.990 1401.840 2796.000 1411.320 ;
        RECT 3.990 1400.440 2795.600 1401.840 ;
        RECT 3.990 1373.280 2796.000 1400.440 ;
        RECT 4.400 1371.880 2796.000 1373.280 ;
        RECT 3.990 1369.200 2796.000 1371.880 ;
        RECT 3.990 1367.800 2795.600 1369.200 ;
        RECT 3.990 1336.560 2796.000 1367.800 ;
        RECT 3.990 1335.160 2795.600 1336.560 ;
        RECT 3.990 1333.840 2796.000 1335.160 ;
        RECT 4.400 1332.440 2796.000 1333.840 ;
        RECT 3.990 1303.920 2796.000 1332.440 ;
        RECT 3.990 1302.520 2795.600 1303.920 ;
        RECT 3.990 1294.400 2796.000 1302.520 ;
        RECT 4.400 1293.000 2796.000 1294.400 ;
        RECT 3.990 1271.280 2796.000 1293.000 ;
        RECT 3.990 1269.880 2795.600 1271.280 ;
        RECT 3.990 1254.960 2796.000 1269.880 ;
        RECT 4.400 1253.560 2796.000 1254.960 ;
        RECT 3.990 1238.640 2796.000 1253.560 ;
        RECT 3.990 1237.240 2795.600 1238.640 ;
        RECT 3.990 1215.520 2796.000 1237.240 ;
        RECT 4.400 1214.120 2796.000 1215.520 ;
        RECT 3.990 1206.000 2796.000 1214.120 ;
        RECT 3.990 1204.600 2795.600 1206.000 ;
        RECT 3.990 1176.080 2796.000 1204.600 ;
        RECT 4.400 1174.680 2796.000 1176.080 ;
        RECT 3.990 1173.360 2796.000 1174.680 ;
        RECT 3.990 1171.960 2795.600 1173.360 ;
        RECT 3.990 1140.720 2796.000 1171.960 ;
        RECT 3.990 1139.320 2795.600 1140.720 ;
        RECT 3.990 1136.640 2796.000 1139.320 ;
        RECT 4.400 1135.240 2796.000 1136.640 ;
        RECT 3.990 1108.080 2796.000 1135.240 ;
        RECT 3.990 1106.680 2795.600 1108.080 ;
        RECT 3.990 1097.200 2796.000 1106.680 ;
        RECT 4.400 1095.800 2796.000 1097.200 ;
        RECT 3.990 1075.440 2796.000 1095.800 ;
        RECT 3.990 1074.040 2795.600 1075.440 ;
        RECT 3.990 1057.760 2796.000 1074.040 ;
        RECT 4.400 1056.360 2796.000 1057.760 ;
        RECT 3.990 1042.800 2796.000 1056.360 ;
        RECT 3.990 1041.400 2795.600 1042.800 ;
        RECT 3.990 1018.320 2796.000 1041.400 ;
        RECT 4.400 1016.920 2796.000 1018.320 ;
        RECT 3.990 1010.160 2796.000 1016.920 ;
        RECT 3.990 1008.760 2795.600 1010.160 ;
        RECT 3.990 978.880 2796.000 1008.760 ;
        RECT 4.400 977.520 2796.000 978.880 ;
        RECT 4.400 977.480 2795.600 977.520 ;
        RECT 3.990 976.120 2795.600 977.480 ;
        RECT 3.990 944.880 2796.000 976.120 ;
        RECT 3.990 943.480 2795.600 944.880 ;
        RECT 3.990 939.440 2796.000 943.480 ;
        RECT 4.400 938.040 2796.000 939.440 ;
        RECT 3.990 912.240 2796.000 938.040 ;
        RECT 3.990 910.840 2795.600 912.240 ;
        RECT 3.990 900.000 2796.000 910.840 ;
        RECT 4.400 898.600 2796.000 900.000 ;
        RECT 3.990 879.600 2796.000 898.600 ;
        RECT 3.990 878.200 2795.600 879.600 ;
        RECT 3.990 860.560 2796.000 878.200 ;
        RECT 4.400 859.160 2796.000 860.560 ;
        RECT 3.990 846.960 2796.000 859.160 ;
        RECT 3.990 845.560 2795.600 846.960 ;
        RECT 3.990 821.120 2796.000 845.560 ;
        RECT 4.400 819.720 2796.000 821.120 ;
        RECT 3.990 814.320 2796.000 819.720 ;
        RECT 3.990 812.920 2795.600 814.320 ;
        RECT 3.990 781.680 2796.000 812.920 ;
        RECT 4.400 780.280 2795.600 781.680 ;
        RECT 3.990 749.040 2796.000 780.280 ;
        RECT 3.990 747.640 2795.600 749.040 ;
        RECT 3.990 742.240 2796.000 747.640 ;
        RECT 4.400 740.840 2796.000 742.240 ;
        RECT 3.990 716.400 2796.000 740.840 ;
        RECT 3.990 715.000 2795.600 716.400 ;
        RECT 3.990 702.800 2796.000 715.000 ;
        RECT 4.400 701.400 2796.000 702.800 ;
        RECT 3.990 683.760 2796.000 701.400 ;
        RECT 3.990 682.360 2795.600 683.760 ;
        RECT 3.990 663.360 2796.000 682.360 ;
        RECT 4.400 661.960 2796.000 663.360 ;
        RECT 3.990 651.120 2796.000 661.960 ;
        RECT 3.990 649.720 2795.600 651.120 ;
        RECT 3.990 623.920 2796.000 649.720 ;
        RECT 4.400 622.520 2796.000 623.920 ;
        RECT 3.990 618.480 2796.000 622.520 ;
        RECT 3.990 617.080 2795.600 618.480 ;
        RECT 3.990 585.840 2796.000 617.080 ;
        RECT 3.990 584.480 2795.600 585.840 ;
        RECT 4.400 584.440 2795.600 584.480 ;
        RECT 4.400 583.080 2796.000 584.440 ;
        RECT 3.990 553.200 2796.000 583.080 ;
        RECT 3.990 551.800 2795.600 553.200 ;
        RECT 3.990 545.040 2796.000 551.800 ;
        RECT 4.400 543.640 2796.000 545.040 ;
        RECT 3.990 520.560 2796.000 543.640 ;
        RECT 3.990 519.160 2795.600 520.560 ;
        RECT 3.990 505.600 2796.000 519.160 ;
        RECT 4.400 504.200 2796.000 505.600 ;
        RECT 3.990 487.920 2796.000 504.200 ;
        RECT 3.990 486.520 2795.600 487.920 ;
        RECT 3.990 466.160 2796.000 486.520 ;
        RECT 4.400 464.760 2796.000 466.160 ;
        RECT 3.990 455.280 2796.000 464.760 ;
        RECT 3.990 453.880 2795.600 455.280 ;
        RECT 3.990 426.720 2796.000 453.880 ;
        RECT 4.400 425.320 2796.000 426.720 ;
        RECT 3.990 422.640 2796.000 425.320 ;
        RECT 3.990 421.240 2795.600 422.640 ;
        RECT 3.990 390.000 2796.000 421.240 ;
        RECT 3.990 388.600 2795.600 390.000 ;
        RECT 3.990 387.280 2796.000 388.600 ;
        RECT 4.400 385.880 2796.000 387.280 ;
        RECT 3.990 357.360 2796.000 385.880 ;
        RECT 3.990 355.960 2795.600 357.360 ;
        RECT 3.990 347.840 2796.000 355.960 ;
        RECT 4.400 346.440 2796.000 347.840 ;
        RECT 3.990 324.720 2796.000 346.440 ;
        RECT 3.990 323.320 2795.600 324.720 ;
        RECT 3.990 308.400 2796.000 323.320 ;
        RECT 4.400 307.000 2796.000 308.400 ;
        RECT 3.990 292.080 2796.000 307.000 ;
        RECT 3.990 290.680 2795.600 292.080 ;
        RECT 3.990 268.960 2796.000 290.680 ;
        RECT 4.400 267.560 2796.000 268.960 ;
        RECT 3.990 259.440 2796.000 267.560 ;
        RECT 3.990 258.040 2795.600 259.440 ;
        RECT 3.990 229.520 2796.000 258.040 ;
        RECT 4.400 228.120 2796.000 229.520 ;
        RECT 3.990 226.800 2796.000 228.120 ;
        RECT 3.990 225.400 2795.600 226.800 ;
        RECT 3.990 194.160 2796.000 225.400 ;
        RECT 3.990 192.760 2795.600 194.160 ;
        RECT 3.990 190.080 2796.000 192.760 ;
        RECT 4.400 188.680 2796.000 190.080 ;
        RECT 3.990 161.520 2796.000 188.680 ;
        RECT 3.990 160.120 2795.600 161.520 ;
        RECT 3.990 150.640 2796.000 160.120 ;
        RECT 4.400 149.240 2796.000 150.640 ;
        RECT 3.990 128.880 2796.000 149.240 ;
        RECT 3.990 127.480 2795.600 128.880 ;
        RECT 3.990 111.200 2796.000 127.480 ;
        RECT 4.400 109.800 2796.000 111.200 ;
        RECT 3.990 96.240 2796.000 109.800 ;
        RECT 3.990 94.840 2795.600 96.240 ;
        RECT 3.990 71.760 2796.000 94.840 ;
        RECT 4.400 70.360 2796.000 71.760 ;
        RECT 3.990 63.600 2796.000 70.360 ;
        RECT 3.990 62.200 2795.600 63.600 ;
        RECT 3.990 32.320 2796.000 62.200 ;
        RECT 4.400 30.960 2796.000 32.320 ;
        RECT 4.400 30.920 2795.600 30.960 ;
        RECT 3.990 29.560 2795.600 30.920 ;
        RECT 3.990 9.695 2796.000 29.560 ;
      LAYER met4 ;
        RECT 171.415 26.695 174.240 492.825 ;
        RECT 176.640 26.695 251.040 492.825 ;
        RECT 253.440 26.695 327.840 492.825 ;
        RECT 330.240 26.695 404.640 492.825 ;
        RECT 407.040 26.695 481.440 492.825 ;
        RECT 483.840 26.695 558.240 492.825 ;
        RECT 560.640 26.695 635.040 492.825 ;
        RECT 637.440 26.695 711.840 492.825 ;
        RECT 714.240 26.695 788.640 492.825 ;
        RECT 791.040 26.695 865.440 492.825 ;
        RECT 867.840 26.695 942.240 492.825 ;
        RECT 944.640 26.695 1019.040 492.825 ;
        RECT 1021.440 26.695 1065.065 492.825 ;
  END
END user_project_wrapper
END LIBRARY

